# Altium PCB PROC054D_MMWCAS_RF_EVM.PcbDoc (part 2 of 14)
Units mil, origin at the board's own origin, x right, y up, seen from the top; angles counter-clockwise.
Board outline 6299.21 x 5370.07 mil, 8 copper layers (L1 TOP, L2 GND, L3 SIGNAL 1, L4 GND, L5 SIGNAL 2, L6 SIGNAL 3, L7 GND, L8 BOTTOM), stack 53.5 mil thick; 775 components, 552 nets, 2648 pads, 7845 vias.

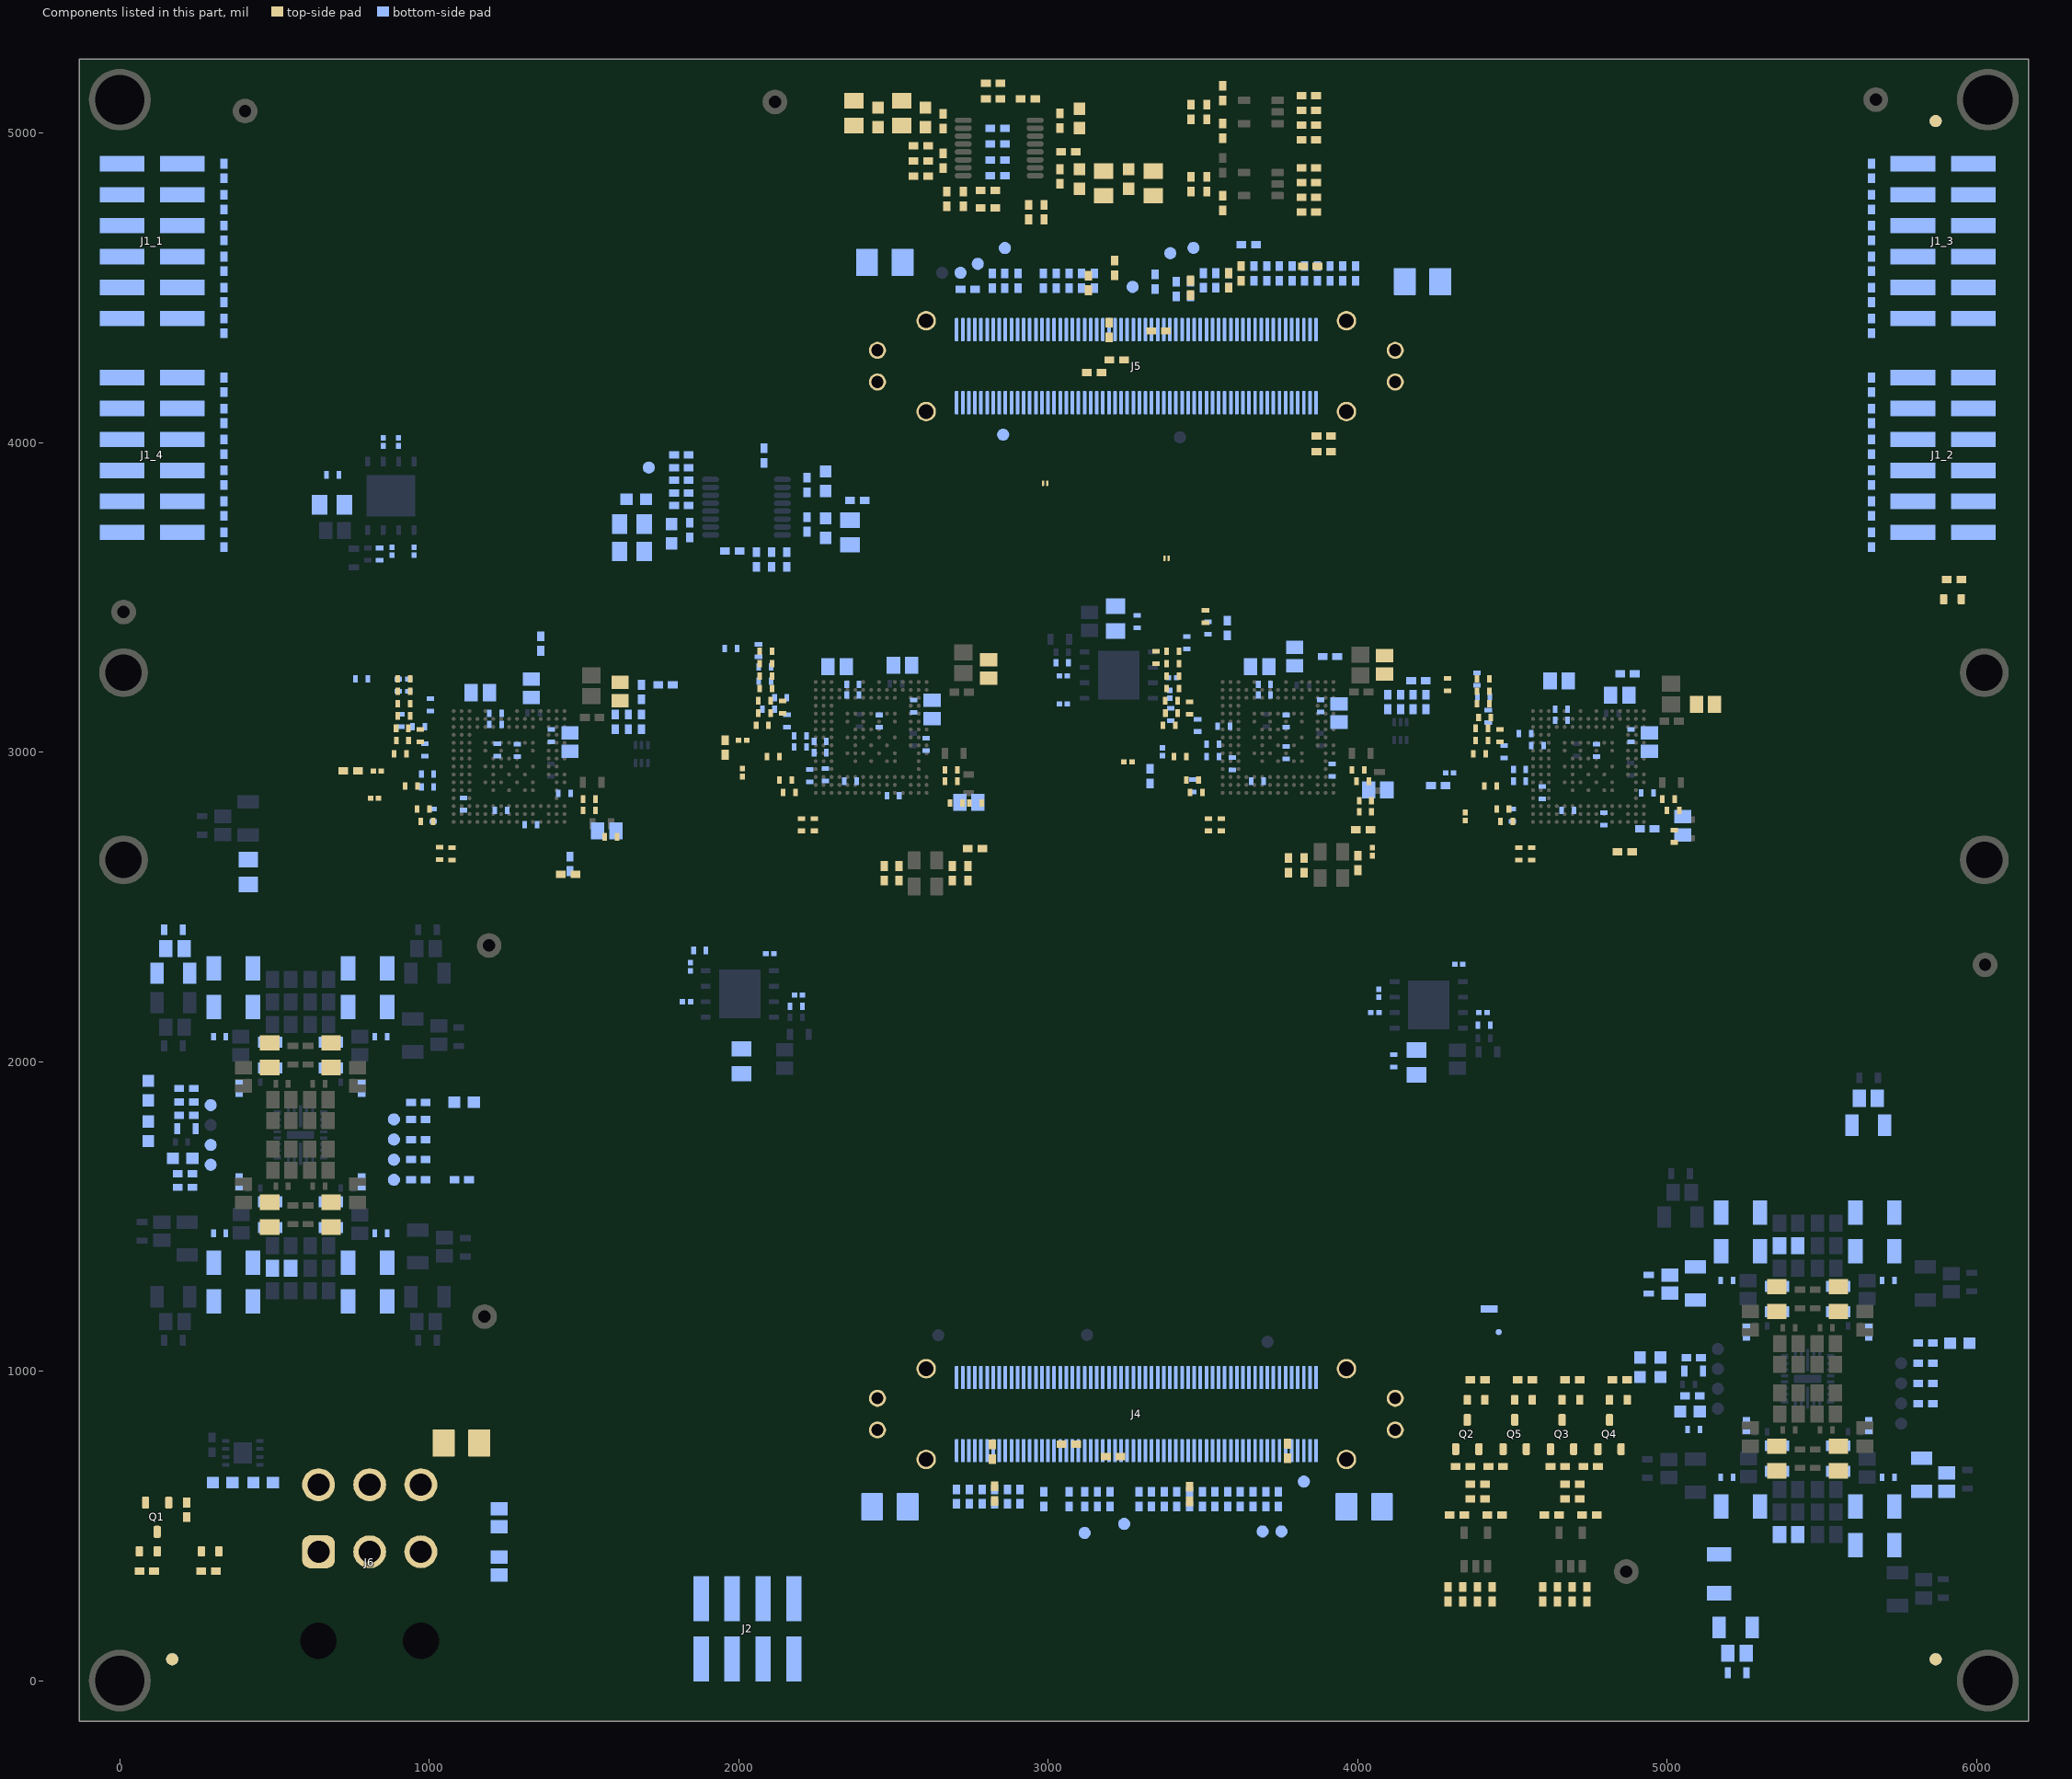
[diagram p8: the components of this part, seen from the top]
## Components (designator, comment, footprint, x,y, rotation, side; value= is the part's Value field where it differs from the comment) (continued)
C129_4 "GCM155R71C224KE02D" 0402S 1219.89,3007.69 r270 bottom locked value=0.22uF (schematic designator C129)
C130_1 "GCM21BR71A106KE22L" 0805L 2529.43,3280.8 r0 bottom locked value=10uF (schematic designator C130)
C130_2 "GCM21BR71A106KE22L" 0805L 4847.43,3183.8 r0 bottom locked value=10uF (schematic designator C130)
C130_3 "GCM21BR71A106KE22L" 0805L 3796.42,3308.91 r90 bottom locked value=10uF (schematic designator C130)
C130_4 "GCM21BR71A106KE22L" 0805L 1329.9,3206.33 r90 bottom locked value=10uF (schematic designator C130)
C131_1 "GCM155R71C224KE02D" 0402S 2686.84,2942.02 r0 top locked value=0.22uF (schematic designator C131)
C131_2 "GCM155R71C224KE02D" 0402S 5004.84,2848.02 r0 top locked value=0.22uF (schematic designator C131)
C131_3 "GCM155R71C224KE02D" 0402S 4016.84,2906.06 r0 top locked value=0.22uF (schematic designator C131)
C131_4 "GCM155R71C224KE02D" 0402S 1516.84,2848.02 r0 top locked value=0.22uF (schematic designator C131)
C132_1 "GCM155R71C224KE02D" 0402S 2686.84,2906.06 r0 top locked value=0.22uF (schematic designator C132)
C132_2 "GCM155R71C224KE02D" 0402S 5019.84,2812.06 r0 top locked value=0.22uF (schematic designator C132)
C132_3 "GCM155R71C224KE02D" 0402S 4001.84,2942.02 r0 top locked value=0.22uF (schematic designator C132)
C132_4 "GCM155R71C224KE02D" 0402S 1516.84,2812.06 r0 top locked value=0.22uF (schematic designator C132)
C133_1 "GCM21BR71A106KE22L" 0805L 2743.75,2837.89 r0 bottom locked value=10uF (schematic designator C133)
C133_2 "GCM21BR71A106KE22L" 0805L 5050.19,2762.16 r270 bottom locked value=10uF (schematic designator C133)
C133_3 "GCM21BR71A106KE22L" 0805L 4065.03,2878.26 r0 bottom locked value=10uF (schematic designator C133)
C133_4 "GCM21BR71A106KE22L" 0805L 1573.1,2745.99 r0 bottom locked value=10uF (schematic designator C133)
C134_1 "GCM155R71C224KE02D" 0402S 2605.98,3025.49 r90 bottom locked value=0.22uF (schematic designator C134)
C134_2 "GCM155R71C224KE02D" 0402S 4936.09,2868 r0 bottom locked value=0.22uF (schematic designator C134)
C134_3 "GCM155R71C224KE02D" 0402S 3918.09,2942 r270 bottom locked value=0.22uF (schematic designator C134)
C134_4 "GCM155R71C224KE02D" 0402S 1437.23,2867 r0 bottom locked value=0.22uF (schematic designator C134)
C135_1 "GCM155R71C224KE02D" 0402S 2361.3,2906 r180 bottom locked value=0.22uF (schematic designator C135)
C135_2 "GCM155R71C224KE02D" 0402S 4679.3,2812 r180 bottom locked value=0.22uF (schematic designator C135)
C135_3 "GCM155R71C224KE02D" 0402S 3676.3,2906 r180 bottom locked value=0.22uF (schematic designator C135)
C135_4 "GCM155R71C224KE02D" 0402S 1231.3,2812 r0 bottom locked value=0.22uF (schematic designator C135)
C136_1 "GCM155R71C224KE02D" 0402S 2454.38,3100.07 r270 bottom locked value=0.22uF (schematic designator C136)
C136_2 "GCM155R71C224KE02D" 0402S 4772.38,3006.07 r270 bottom locked value=0.22uF (schematic designator C136)
C136_3 "GCM155R71C224KE02D" 0402S 3769.38,3100.07 r270 bottom locked value=0.22uF (schematic designator C136)
C136_4 "GCM155R71C224KE02D" 0402S 1284.38,3006.07 r270 bottom locked value=0.22uF (schematic designator C136)
C137_1 "GCM155R71C224KE02D" 0402S 2369.09,3184.18 r180 bottom locked value=0.22uF (schematic designator C137)
C137_2 "GCM155R71C224KE02D" 0402S 4659,3103.53 r180 bottom locked value=0.22uF (schematic designator C137)
C137_3 "GCM155R71C224KE02D" 0402S 3699.09,3218.8 r180 bottom locked value=0.22uF (schematic designator C137)
C137_4 "GCM155R71C224KE02D" 0402S 1214.09,3090.18 r180 bottom locked value=0.22uF (schematic designator C137)
C138_1 "GCM155R71C224KE02D" 0402S 2369.09,3218.8 r180 bottom locked value=0.22uF (schematic designator C138)
C138_2 "GCM155R71C224KE02D" 0402S 4659,3138.15 r180 bottom locked value=0.22uF (schematic designator C138)
C138_3 "GCM155R71C224KE02D" 0402S 3699.09,3184.18 r180 bottom locked value=0.22uF (schematic designator C138)
C138_4 "GCM155R71C224KE02D" 0402S 1214.09,3124.8 r180 bottom locked value=0.22uF (schematic designator C138)
C139_1 "GCM21BR71A106KE22L" 0805L 2318.38,3275.59 r180 bottom locked value=10uF (schematic designator C139)
C139_2 "GCM21BR71A106KE22L" 0805L 4651.52,3229.77 r180 bottom locked value=10uF (schematic designator C139)
C139_3 "GCM21BR71A106KE22L" 0805L 3683.72,3276.04 r180 bottom locked value=10uF (schematic designator C139)
C139_4 "GCM21BR71A106KE22L" 0805L 1164.56,3192.04 r180 bottom locked value=10uF (schematic designator C139)
C140_1 "GCM155R71C224KE02D" 0402S 2564.98,3147.69 r270 bottom locked value=0.22uF (schematic designator C140)
C140_2 "GCM155R71C224KE02D" 0402S 4882.98,3053.69 r270 bottom locked value=0.22uF (schematic designator C140)
C140_3 "GCM155R71C224KE02D" 0402S 3879.98,3149.11 r270 bottom locked value=0.22uF (schematic designator C140)
C140_4 "GCM155R71C224KE02D" 0402S 1394.98,3053.69 r270 bottom locked value=0.22uF (schematic designator C140)
C141_1 "GCM21BR71A106KE22L" 0805L 2624.84,3138.16 r270 bottom locked value=10uF (schematic designator C141)
C141_2 "GCM21BR71A106KE22L" 0805L 4942.98,3032.5 r270 bottom locked value=10uF (schematic designator C141)
C141_3 "GCM21BR71A106KE22L" 0805L 3939.98,3126.5 r270 bottom locked value=10uF (schematic designator C141)
C141_4 "GCM21BR71A106KE22L" 0805L 1454.98,3032.5 r270 bottom locked value=10uF (schematic designator C141)
C142_1 "GCM155R71C224KE02D" 0402S 2141.49,3145.71 r90 top locked value=0.22uF (schematic designator C142)
C142_2 "GCM155R71C224KE02D" 0402S 4562,2671.58 r270 top locked value=0.22uF (schematic designator C142)
C142_3 "GCM155R71C224KE02D" 0402S 3457.49,3142.71 r90 top locked value=0.22uF (schematic designator C142)
C142_4 "GCM155R71C224KE02D" 0402S 971.49,3053.71 r90 top locked value=0.22uF (schematic designator C142)
C143_1 "GCM155R71C224KE02D" 0402S 2244,2765.58 r270 top locked value=0.22uF (schematic designator C143)
C143_2 "GCM155R71C224KE02D" 0402S 4459.99,3053.71 r90 top locked value=0.22uF (schematic designator C143)
C143_3 "GCM155R71C224KE02D" 0402S 3559,2765.58 r270 top locked value=0.22uF (schematic designator C143)
C143_4 "GCM155R71C224KE02D" 0402S 1074,2671.58 r270 top locked value=0.22uF (schematic designator C143)
C144_1 "GCM155R71C224KE02D" 0402S 2498.51,2859.53 r0 bottom locked value=0.22uF (schematic designator C144)
C144_2 "GCM155R71C224KE02D" 0402S 4596.3,2868.9 r270 bottom locked value=0.22uF (schematic designator C144)
C144_3 "GCM155R71C224KE02D" 0402S 3769.06,2998.27 r90 bottom locked value=0.22uF (schematic designator C144)
C144_4 "GCM155R71C224KE02D" 0402S 1110.64,2832.35 r270 bottom locked value=0.22uF (schematic designator C144)
C145_1 "GCM155R71C224KE02D" 0402S 2280.64,2926.35 r270 bottom locked value=0.22uF (schematic designator C145)
C145_2 "GCM155R71C224KE02D" 0402S 4796.51,2783.84 r270 bottom locked value=0.22uF (schematic designator C145)
C145_3 "GCM155R71C224KE02D" 0402S 3595.75,2962.9 r270 bottom locked value=0.22uF (schematic designator C145)
C145_4 "GCM155R71C224KE02D" 0402S 1328.51,2765.53 r0 bottom locked value=0.22uF (schematic designator C145)
C146_1 "GCM155R71C104KA55D" 0402S 2163.58,2870 r180 top locked value=0.1uF (schematic designator C146)
C146_2 "GCM155R71C104KA55D" 0402S 4481.58,2776 r180 top locked value=0.1uF (schematic designator C146)
C146_3 "GCM155R71C104KA55D" 0402S 3478.58,2870 r180 top locked value=0.1uF (schematic designator C146)
C146_4 "GCM155R71C104KA55D" 0402S 992.8,2776 r180 top locked value=0.1uF (schematic designator C146)
C147_1 "GCM155R71C104KA55D" 0402S 2203,2765.58 r270 top locked value=0.1uF (schematic designator C147)
C147_2 "GCM155R71C104KA55D" 0402S 4521,2671.58 r270 top locked value=0.1uF (schematic designator C147)
C147_3 "GCM155R71C104KA55D" 0402S 3518,2765.58 r270 top locked value=0.1uF (schematic designator C147)
C147_4 "GCM155R71C104KA55D" 0402S 1033,2673 r270 top locked value=0.1uF (schematic designator C147)
C148_1 "GCM155R71C224KE02D" 0402S 2229,2924.28 r270 bottom locked value=0.22uF (schematic designator C148)
C148_2 "GCM155R71C224KE02D" 0402S 4500,2795.58 r270 bottom locked value=0.22uF (schematic designator C148)
C148_3 "GCM155R71C224KE02D" 0402S 3466.95,2891 r270 bottom locked value=0.22uF (schematic designator C148)
C148_4 "GCM155R71C224KE02D" 0402S 1012,2795.58 r270 bottom locked value=0.22uF (schematic designator C148)
C149 "CGA2B3X7R1H104K050BB" 0402 3564.27,5129.3 r90 top locked value=0.1uF
C150 "GCM31CR71A226KE02" 1206_180L 173.03,2285.84 r180 bottom locked value=22uF
C151 "GCM21BR71A106KE22L" 0805L 178.04,2365.78 r180 bottom locked value=10uF
C152 "GCM188R71C105KA64J" 0603S 173.04,2425.94 r180 bottom locked value=1uF
C153 "GCM21BR71A106KE22L" 0805L 5393.06,471.95 r0 bottom locked value=10uF
C154 "GCM31CR71A226KE02" 1206_180L 5221.38,171.94 r0 bottom locked value=22uF
C155 "GCM21BR71A106KE22L" 0805L 5226.35,89.14 r0 bottom locked value=10uF
C156 "GCM188R71C105KA64J" 0603S 5226.35,25.17 r0 bottom locked value=1uF
C157 "GCM21BR71A106KE22L" 0805L 5393.06,1405.27 r0 bottom locked value=10uF
C158 "GCM31CR71A226KE02" 1206_180L 5091.39,1283.32 r270 bottom locked value=22uF
C159 "GCM21BR71A106KE22L" 0805L 5009.39,1281.05 r270 bottom locked value=10uF
C160 "GCM188R71C105KA64J" 0603S 4940.6,1280.76 r270 bottom locked value=1uF
C161 "GCM21BR71A106KE22L" 0805L 522.33,1332.8 r0 bottom locked value=10uF
C162 "GCM155R71C104KA55D" 0402 4320.97,535.63 r180 top locked value=0.1uF
C163 "GCM155R71C104KA55D" 0402 4627.42,535.63 r180 top locked value=0.1uF
C164 "GCM155R71C104KA55D" 0402 3564.27,4774.2 r270 top locked value=0.1uF
C165 "GCM155R71C104KA55D" 0402 3564.27,5007.25 r270 top locked value=0.1uF
C166 "GCM31CR71A226KE02" 1206_180L 5822.48,664.93 r90 bottom locked value=22uF
C167 "GJM1555C1H4R7BB01D" 0402 2690.4,2608.27 r90 top locked value=4.7pF
C168 "GJM1555C1H4R7BB01D" 0402 2518.3,2608.27 r90 top locked value=4.7pF
C169 "GCM21BR71A106KE22L" 0805_HV 2372.39,5064.49 r270 top locked value=10uF
C170 "GCM155R71C224KE02D" 0402 2660.57,5038.49 r90 top locked value=0.22uF
C171 "GCM188R70J225KE22D" 0603 2603.2,5050.47 r270 top locked value=2.2uF
C172 "GCM21BR71A106KE22L" 0805_HV 2526.41,5064.49 r90 top locked value=10uF
C173 "GJM1555C1H4R7BB01D" 0402 4001.11,2642 r90 top locked value=4.7pF
C174 "GJM1555C1H4R7BB01D" 0402 3826.93,2634.28 r270 top locked value=4.7pF
C175 "GCM21BR71A106KE22L" 0805_HV 3339.25,4837.72 r90 top locked value=10uF
C176 "GCM21BR71A106KE22L" 0805_HV 3178.88,4837.72 r270 top locked value=10uF
C177 "GCM155R71C224KE02D" 0402 3038.3,4859.61 r270 top locked value=0.22uF
C178 "GCM188R70J225KE22D" 0603 3100.57,5047.4 r270 top locked value=2.2uF
C179 "GCM155R71C224KE02D" 0402 3038.3,5039.53 r90 top locked value=0.22uF
C180 "GCM188R70J225KE22D" 0603 3100.57,4851.73 r90 top locked value=2.2uF
C181 "GCM21BR71A106KE22L" 0805_HV 1655.02,3648.2 r180 bottom locked value=10uF
C182 "GCM155R71C224KE02D" 0402 1841.77,3717.5 r270 bottom locked value=0.22uF
C183 "GCM188R70J225KE22D" 0603 1783.09,3705.52 r90 bottom locked value=2.2uF
C184 "GCM21BR71A106KE22L" 0805_HV 1655.02,3737.01 r180 bottom locked value=10uF
C185 "GCM21BR71A106KE22L" 0805_HV 2359.46,3709.7 r90 bottom locked value=10uF
C186 "GCM155R71C224KE02D" 0402 2220.98,3735.85 r90 bottom locked value=0.22uF
C187 "GCM188R70J225KE22D" 0603 2280.22,3723.87 r270 bottom locked value=2.2uF
C188 "GCM155R71C224KE02D" 0402 2220.98,3863.05 r90 bottom locked value=0.22uF
C189 "GCM188R70J225KE22D" 0603 2280.22,3875.03 r270 bottom locked value=2.2uF
C190 "T491B476K010AT" 3528-21 4021.54,561.82 r0 bottom locked value=47uF
C191 "T491B476K010AT" 3528-21 2488.3,561.82 r180 bottom locked value=47uF
C192 "T491B476K010AT" 3528-21 2472.09,4582.18 r180 bottom value=47uF
C193 "T491B476K010AT" 3528-21 4209.7,4520.2 r0 bottom value=47uF
C194 "T491B476K010AT" 3528-21 1103.88,767.73 r0 top locked value=47uF
C195 "C0402C103K4RACTU" 0402 1686.31,3097.83 r90 bottom locked value=0.01uF
C196 "CGA2B3X7R1H104K050BB" 0402 1643.31,3097.84 r90 bottom locked value=0.1uF
C197 "CGA2B3X7R1H104K050BB" 0402 1762.95,3217.44 r0 bottom locked value=0.1uF
C198 "CGA2B3X7R1H104K050BB" 0402 4196.84,3230.71 r180 bottom locked value=0.1uF
C199 "C0402C103K4RACTU" 0402 4138.47,3162.21 r90 bottom locked value=0.01uF
C200 "CGA2B3X7R1H104K050BB" 0402 4179.47,3162.21 r90 bottom locked value=0.1uF
C201 "GCM21BR71A106KE22L" 0805L 5904.25,641.77 r90 bottom locked value=10uF
C202 "GCM188R71C105KA64J" 0603 463.3,640.08 r180 bottom locked value=1uF
C203 "GCM188R71C105KA64J" 0603 332.14,640.15 r0 bottom locked value=1uF
C204 "GCM31CR71A226KE02" 1206_180L 5650.52,1794.57 r180 bottom locked value=22uF
C205 "CGA2B3X7R1H104K050BB" 0402 4443.02,535.63 r0 top locked value=0.1uF
C206 "CGA2B3X7R1H104K050BB" 0402 4749.46,535.63 r0 top locked value=0.1uF
C207 "GCM21BR71A106KE22L" 0805L 5650.43,1881.43 r180 bottom locked value=10uF
DS1 "TLMS1000-GS08" TLMx1000_Red 291.9,417.61 r0 top locked value=Red
DS2 "TLMS1000-GS08" TLMx1000_Red 5922.6,3493.76 r180 top locked value=Red
DS3 "TLMY1000-GS08" TLMx1000_Yellow 91.9,417.61 r0 top locked value=Yellow
DS4 "TLMY1000-GS08" TLMx1000_Yellow 4382.93,906.78 r180 top locked value=Yellow
DS5 "TLMY1000-GS08" TLMx1000_Yellow 4689.38,906.78 r180 top locked value=Yellow
DS6 "TLMY1000-GS08" TLMx1000_Yellow 4842.6,906.78 r180 top locked value=Yellow
DS7 "TLMY1000-GS08" TLMx1000_Yellow 4536.15,906.78 r180 top locked value=Yellow
FID1 "Fiducial" Fiducial10-20 5868,5039 r90 top locked
FID2 "Fiducial" Fiducial10-20 169,69 r90 top locked
FID3 "Fiducial" Fiducial10-20 5868,69 r90 top locked
FID4 "Fiducial" Fiducial10-20 169,69 r90 bottom locked
FID5 "Fiducial" Fiducial10-20 5868,69 r90 bottom locked
FID6 "Fiducial" Fiducial10-20 5868,5039 r90 bottom locked
J1_1 "TSM-106-01-L-DV" Samtec_TSM-106-01-x-DV 104.76,4650.95 r180 bottom locked (schematic designator J1)
J1_2 "TSM-106-01-L-DV" Samtec_TSM-106-01-x-DV 5892.24,3960.13 r0 bottom locked (schematic designator J1)
J1_3 "TSM-106-01-L-DV" Samtec_TSM-106-01-x-DV 5892.24,4650.95 r0 bottom locked (schematic designator J1)
J1_4 "TSM-106-01-L-DV" Samtec_TSM-106-01-x-DV 104.76,3960.13 r180 bottom locked (schematic designator J1)
J2 "TSM-104-01-L-DV" Samtec_TSM-104-01-x-DV 2028.45,167.06 r270 bottom locked
J3 "19S101-40ML5" 19S101_40ML5 4534.87,1201.17 r90 bottom locked
J4 "FX23-120P-0.5SV15" Hirose_FX23-120P-0_5SV15 3284.92,861.13 r270 bottom locked
J5 "FX23-120P-0.5SV15" Hirose_FX23-120P-0_5SV15 3284.92,4246.95 r270 bottom locked
J6 "0039300060" Molex_0039300060 807.36,128.84 r270 bottom locked
L1 "NLCV32T-R10M-EFRD" NLCV32 366.61,1225.32 r180 bottom locked value=100nH
L2 "NLCV32T-R10M-EFRD" NLCV32 366.61,2175.82 r180 bottom locked value=100nH
L3 "NLCV32T-R10M-EFRD" NLCV32 366.61,1350.1 r180 bottom locked value=100nH
L4 "NLCV32T-R10M-EFRD" NLCV32 800.47,1350.1 r0 bottom locked value=100nH
L5 "NLCV32T-R10M-EFRD" NLCV32 800.47,1225.32 r0 bottom locked value=100nH
L6 "NLCV32T-R10M-EFRD" NLCV32 366.61,2300.61 r180 bottom locked value=100nH
L7 "NLCV32T-R10M-EFRD" NLCV32 800.47,2300.61 r0 bottom locked value=100nH
L8 "NLCV32T-R10M-EFRD" NLCV32 800.47,2175.82 r0 bottom locked value=100nH
L9 "BLM21PG300SH1D" 0805_HV 682.81,1505.28 r90 top locked value="30 ohm"
L10 "BLM21PG300SH1D" 0805_HV 484.26,1505.28 r90 top locked value="30 ohm"
L11 "BLM21PG300SH1D" 0805_HV 682.81,2020.65 r270 top locked value="30 ohm"
L12 "BLM21PG300SH1D" 0805_HV 484.26,2020.65 r270 top locked value="30 ohm"
L13 "DFE252012PD-R47M" DFE252012P 681.93,1505.16 r270 bottom locked value=470nH
L14 "DFE252012PD-R47M" DFE252012P 485.15,1505.16 r270 bottom locked value=470nH
L15 "DFE252012PD-R47M" DFE252012P 681.93,2020.76 r90 bottom locked value=470nH
L16 "DFE252012PD-R47M" DFE252012P 485.15,2020.76 r90 bottom locked value=470nH
L17 "NLCV32T-R10M-EFRD" NLCV32 5237.33,562.25 r180 bottom locked value=100nH
L18 "NLCV32T-R10M-EFRD" NLCV32 5237.33,1512.75 r180 bottom locked value=100nH
L19 "NLCV32T-R10M-EFRD" NLCV32 5168.15,344.97 r270 bottom locked value=100nH
L20 "NLCV32T-R10M-EFRD" NLCV32 5671.19,437.46 r0 bottom locked value=100nH
L21 "NLCV32T-R10M-EFRD" NLCV32 5671.19,562.25 r0 bottom locked value=100nH
L22 "NLCV32T-R10M-EFRD" NLCV32 5237.33,1387.96 r180 bottom locked value=100nH
L23 "NLCV32T-R10M-EFRD" NLCV32 5671.19,1387.96 r0 bottom locked value=100nH
L24 "NLCV32T-R10M-EFRD" NLCV32 5671.19,1512.75 r0 bottom locked value=100nH
L25 "BLM21PG300SH1D" 0805_HV 5553.54,717.42 r90 top locked value="30 ohm"
L26 "BLM21PG300SH1D" 0805_HV 5354.99,717.42 r90 top locked value="30 ohm"
L27 "BLM21PG300SH1D" 0805_HV 5553.54,1232.79 r270 top locked value="30 ohm"
L28 "BLM21PG300SH1D" 0805_HV 5354.99,1232.79 r270 top locked value="30 ohm"
L29 "DFE252012PD-R47M" DFE252012P 5552.65,717.3 r270 bottom locked value=470nH
L30 "DFE252012PD-R47M" DFE252012P 5355.87,717.3 r270 bottom locked value=470nH
L31 "DFE252012PD-R47M" DFE252012P 5552.65,1232.91 r90 bottom locked value=470nH
L32 "DFE252012PD-R47M" DFE252012P 5355.87,1232.91 r90 bottom locked value=470nH
L33 "BLM18SG121TN1D" 0603 2450.31,5050.47 r270 top locked value="120 ohm"
L34 "BLM18SG121TN1D" 0603 3260.01,4851.73 r90 top locked value="120 ohm"
L35 "BLM18SG121TN1D" 0603 1669.04,3816.87 r0 bottom locked value="120 ohm"
Logo1 "CE MAWRk" CE_Mark_5mm 5859.14,4655.58 r0 top locked
Logo2 "Texas Instruments" TI_Stacked_Overlay_Small 3704.87,99.62 r0 top locked
Logo3 "FCC disclaimer" FCC_disclaimer 4988.06,6271.78 r0 top locked
Logo4 "WEEE logo" WEEE_Minimum 5859.14,4323.69 r0 top locked
Logo5 "ESD Susceptible" ESD_Overlay_Large 1902.61,792.81 r0 top locked
LOGO6 "CAUTION HOT SURFACE" IEC_HotSurface_Large 5623.06,1848.13 r0 top locked
Q1 "BSS123" SOT-23 120.44,527.89 r270 top locked value=100V
Q2 "BSS123" SOT-23 4354.39,795.2 r90 top locked value=100V
Q3 "BSS123" SOT-23 4660.83,795.2 r90 top locked value=100V
Q4 "BSS123" SOT-23 4814.06,795.2 r90 top locked value=100V
Q5 "BSS123" SOT-23 4507.61,795.2 r90 top locked value=100V
R1_1 "CRCW040233R2FKED" 0402S 2111.9,2985 r0 top locked value=33.2 (schematic designator R1)
R1_2 "CRCW040233R2FKED" 0402S 4429.9,2891 r0 top locked value=33.2 (schematic designator R1)
R1_3 "CRCW040233R2FKED" 0402S 3426.9,2985 r0 top locked value=33.2 (schematic designator R1)
R1_4 "CRCW040233R2FKED" 0402S 941.9,2891 r0 top locked value=33.2 (schematic designator R1)
R2_1 "CRCW040233R2FKED" 0402S 2702.88,2834.89 r180 top locked value=33.2 (schematic designator R2)
R2_2 "CRCW040233R2FKED" 0402S 5022.77,2728.4 r90 top locked value=33.2 (schematic designator R2)
R2_3 "CRCW040233R2FKED" 0402S 4024.71,2842.4 r180 top locked value=33.2 (schematic designator R2)
R2_4 "CRCW040233R2FKED" 0402S 1587.14,2726.23 r180 top locked value=33.2 (schematic designator R2)
R3_1 "CRCW040247K5FKED" 0402 1955.47,3015.03 r270 top locked value=47.5k (schematic designator R3)
R3_2 "CRCW040247K5FKED" 0402 4260.87,2891.34 r180 bottom locked value=47.5k (schematic designator R3)
R3_3 "CRCW040247K5FKED" 0402 3328.84,2922.71 r270 bottom locked value=47.5k (schematic designator R3)
R3_4 "CRCW040247K5FKED" 0402 745.96,2938.96 r180 top locked value=47.5k (schematic designator R3)
R4_1 "CRCW040233R2FKED" 0402S 2151,2910 r0 top locked value=33.2 (schematic designator R4)
R4_2 "CRCW040233R2FKED" 0402S 4469,2816 r0 top locked value=33.2 (schematic designator R4)
R4_3 "CRCW040233R2FKED" 0402S 3466,2910 r0 top locked value=33.2 (schematic designator R4)
R4_4 "CRCW040233R2FKED" 0402S 981,2816 r0 top locked value=33.2 (schematic designator R4)
R5_1 "CRCW040233R2FKED" 0402S 2263.7,3034.15 r0 bottom locked value=33.2 (schematic designator R5)
R5_2 "CRCW040233R2FKED" 0402S 4523.9,2943.53 r0 bottom locked value=33.2 (schematic designator R5)
R5_3 "CRCW040233R2FKED" 0402S 3531.46,3026.2 r0 bottom locked value=33.2 (schematic designator R5)
R5_4 "CRCW040233R2FKED" 0402S 994.55,2928.78 r0 bottom locked value=33.2 (schematic designator R5)
R6_1 "CRCW02010000Z0ED" 0201 2012.51,3038.66 r180 top locked value=0 (schematic designator R6)
R6_2 "CRCW02010000Z0ED" 0201 4297.49,2932.79 r180 bottom locked value=0 (schematic designator R6)
R6_3 "CRCW02010000Z0ED" 0201 3369.29,3001.01 r270 bottom locked value=0 (schematic designator R6)
R6_4 "CRCW02010000Z0ED" 0201 831.79,2938.96 r180 top locked value=0 (schematic designator R6)
R7_1 "CRCW02010000Z0ED" 0201 2012.41,2934.01 r270 top locked value=0 (schematic designator R7)
R7_2 "CRCW02010000Z0ED" 0201 4347.63,2791.93 r270 top locked value=0 (schematic designator R7)
R7_3 "CRCW02010000Z0ED" 0201 3258.01,2969 r180 top locked value=0 (schematic designator R7)
R7_4 "CRCW02010000Z0ED" 0201 823.23,2851.34 r180 top locked value=0 (schematic designator R7)
R8_1 "CRCW040233R2FKED" 0402S 2263.7,2998.15 r180 bottom locked value=33.2 (schematic designator R8)
R8_2 "CRCW040233R2FKED" 0402S 4523.9,2906 r180 bottom locked value=33.2 (schematic designator R8)
R8_3 "CRCW040233R2FKED" 0402S 3531.46,2985.2 r180 bottom locked value=33.2 (schematic designator R8)
R8_4 "CRCW040233R2FKED" 0402S 994.55,2887.78 r180 bottom locked value=33.2 (schematic designator R8)
R9_1 "ERJ-2GE0R00X" 0402S 2135.9,3176 r0 bottom locked value=0 (schematic designator R9)
R9_2 "ERJ-2GE0R00X" 0402S 4580.6,3020.95 r0 bottom locked value=0 (schematic designator R9)
R9_3 "ERJ-2GE0R00X" 0402S 3567.22,3084.16 r0 bottom locked value=0 (schematic designator R9)
R9_4 "ERJ-2GE0R00X" 0402S 965.9,3082 r0 bottom locked value=0 (schematic designator R9)
R10_1 "CRCW040233R2FKED" 0402S 2083,3126 r180 top locked value=33.2 (schematic designator R10)
R10_2 "CRCW040233R2FKED" 0402S 4400.91,3037 r180 top locked value=33.2 (schematic designator R10)
R10_3 "CRCW040233R2FKED" 0402S 3398.91,3126 r180 top locked value=33.2 (schematic designator R10)
R10_4 "CRCW040233R2FKED" 0402S 913,3037 r180 top locked value=33.2 (schematic designator R10)
R11_1 "CRCW040233R2FKED" 0402S 2084.31,3229 r0 bottom locked value=33.2 (schematic designator R11)
R11_2 "CRCW040233R2FKED" 0402S 4422.06,3115 r90 bottom locked value=33.2 (schematic designator R11)
R11_3 "CRCW040233R2FKED" 0402S 3516,3400.34 r270 bottom locked value=33.2 (schematic designator R11)
R11_4 "CRCW040233R2FKED" 0402S 1003.91,3152.94 r270 bottom value=33.2 (schematic designator R11)
R12_1 "CRCW040233R2FKED" 0402S 2083,3166 r180 top locked value=33.2 (schematic designator R12)
R12_2 "CRCW040233R2FKED" 0402S 4400.89,3077 r180 top locked value=33.2 (schematic designator R12)
R12_3 "CRCW040233R2FKED" 0402S 3398.89,3166 r180 top locked value=33.2 (schematic designator R12)
R12_4 "CRCW040233R2FKED" 0402S 912.89,3077 r180 top locked value=33.2 (schematic designator R12)
R13_1 "CRCW040233R2FKED" 0402S 2088,3326 r0 top locked value=33.2 (schematic designator R13)
R13_2 "CRCW040233R2FKED" 0402S 4405.9,3237 r0 top locked value=33.2 (schematic designator R13)
R13_3 "CRCW040233R2FKED" 0402S 3402.9,3326 r0 top locked value=33.2 (schematic designator R13)
R13_4 "CRCW040233R2FKED" 0402S 917.9,3237 r0 top locked value=33.2 (schematic designator R13)
R14_1 "CRCW040233R2FKED" 0402S 2088,3246 r0 top locked value=33.2 (schematic designator R14)
R14_2 "CRCW040233R2FKED" 0402S 4405.89,3157 r0 top locked value=33.2 (schematic designator R14)
R14_3 "CRCW040233R2FKED" 0402S 3402.89,3246 r0 top locked value=33.2 (schematic designator R14)
R14_4 "CRCW040233R2FKED" 0402S 917.89,3157 r0 top locked value=33.2 (schematic designator R14)
R15_1 "CRCW040233R2FKED" 0402S 2088,3206 r0 top locked value=33.2 (schematic designator R15)
R15_2 "CRCW040233R2FKED" 0402S 4410.9,3112 r0 top locked value=33.2 (schematic designator R15)
R15_3 "CRCW040233R2FKED" 0402S 3402.9,3206 r0 top locked value=33.2 (schematic designator R15)
R15_4 "CRCW040233R2FKED" 0402S 917.9,3117 r0 top locked value=33.2 (schematic designator R15)
R16_1 "CRCW040210K0FKED" 0402 2704.21,594.52 r90 bottom locked value=10.0k (schematic designator R16)
R16_2 "CRCW040210K0FKED" 0402 3539,586.8 r90 bottom locked value=10.0k (schematic designator R16)
R16_3 "CRCW040210K0FKED" 0402 3993,4546.63 r270 bottom locked value=10.0k (schematic designator R16)
R16_4 "CRCW040210K0FKED" 0402 3067,4522.59 r270 bottom locked value=10.0k (schematic designator R16)
R17_1 "CRCW040210K0FKED" 0402 2745.21,594.52 r90 bottom locked value=10.0k (schematic designator R17)
R17_2 "CRCW040210K0FKED" 0402 3580,586.8 r90 bottom locked value=10.0k (schematic designator R17)
R17_3 "CRCW040210K0FKED" 0402 3952,4546.63 r270 bottom locked value=10.0k (schematic designator R17)
R17_4 "CRCW040210K0FKED" 0402 3026,4522.59 r270 bottom locked value=10.0k (schematic designator R17)
R18_1 "CRCW040210K0FKED" 0402 2786.21,594.52 r90 bottom locked value=10.0k (schematic designator R18)
R18_2 "CRCW040210K0FKED" 0402 3621,586.8 r90 bottom locked value=10.0k (schematic designator R18)
R18_3 "CRCW040210K0FKED" 0402 3911,4546.63 r270 bottom locked value=10.0k (schematic designator R18)
R18_4 "CRCW040210K0FKED" 0402 2985,4522.59 r270 bottom locked value=10.0k (schematic designator R18)
R19 "PMR10EZPJ000" 0805L 1226.16,526.12 r270 bottom locked value=0
R20 "PMR10EZPJ000" 0805L 1226.16,370.14 r270 bottom locked value=0
R21_1 "CRCW04020000Z0ED" 0402 335.85,4877.33 r90 bottom locked value=0 (schematic designator R21)
R21_2 "CRCW04020000Z0ED" 0402 5661.15,3686.51 r90 bottom locked value=0 (schematic designator R21)
R21_3 "CRCW04020000Z0ED" 0402 5661.15,4377.33 r90 bottom locked value=0 (schematic designator R21)
R21_4 "CRCW04020000Z0ED" 0402 335.85,4186.51 r90 bottom locked value=0 (schematic designator R21)
R22_1 "CRCW04020000Z0ED" 0402 335.85,4777.33 r90 bottom locked value=0 (schematic designator R22)
R22_2 "CRCW04020000Z0ED" 0402 5661.15,3786.51 r90 bottom locked value=0 (schematic designator R22)
R22_3 "CRCW04020000Z0ED" 0402 5661.15,4477.33 r90 bottom locked value=0 (schematic designator R22)
R22_4 "CRCW04020000Z0ED" 0402 335.85,4086.51 r90 bottom locked value=0 (schematic designator R22)
R23_1 "CRCW04020000Z0ED" 0402 335.85,4677.33 r90 bottom locked value=0 (schematic designator R23)
R23_2 "CRCW04020000Z0ED" 0402 5661.15,3886.51 r90 bottom locked value=0 (schematic designator R23)
R23_3 "CRCW04020000Z0ED" 0402 5661.15,4577.33 r90 bottom locked value=0 (schematic designator R23)
R23_4 "CRCW04020000Z0ED" 0402 335.85,3986.51 r90 bottom locked value=0 (schematic designator R23)
R24_1 "CRCW04020000Z0ED" 0402 335.85,4577.33 r90 bottom locked value=0 (schematic designator R24)
R24_2 "CRCW04020000Z0ED" 0402 5661.15,3986.51 r90 bottom locked value=0 (schematic designator R24)
R24_3 "CRCW04020000Z0ED" 0402 5661.15,4677.33 r90 bottom locked value=0 (schematic designator R24)
R24_4 "CRCW04020000Z0ED" 0402 335.85,3886.51 r90 bottom locked value=0 (schematic designator R24)
R25_1 "CRCW04020000Z0ED" 0402 335.85,4477.33 r90 bottom locked value=0 (schematic designator R25)
R25_2 "CRCW04020000Z0ED" 0402 5661.15,4086.51 r90 bottom locked value=0 (schematic designator R25)
R25_3 "CRCW04020000Z0ED" 0402 5661.15,4777.33 r90 bottom locked value=0 (schematic designator R25)
R25_4 "CRCW04020000Z0ED" 0402 335.85,3786.51 r90 bottom locked value=0 (schematic designator R25)
R26_1 "CRCW04020000Z0ED" 0402 335.85,4377.33 r90 bottom locked value=0 (schematic designator R26)
R26_2 "CRCW04020000Z0ED" 0402 5661.15,4186.51 r90 bottom locked value=0 (schematic designator R26)
R26_3 "CRCW04020000Z0ED" 0402 5661.15,4877.33 r90 bottom locked value=0 (schematic designator R26)
R26_4 "CRCW04020000Z0ED" 0402 335.85,3686.51 r90 bottom locked value=0 (schematic designator R26)
R27_1 "CRCW040210K0FKED" 0402S 1874.26,2359.18 r180 bottom locked value=10.0k (schematic designator R27)
R27_2 "CRCW040210K0FKED" 0402S 4116.64,2002.51 r270 bottom locked value=10.0k (schematic designator R27)
R27_3 "CRCW040210K0FKED" 0402S 3287.73,3421.24 r90 bottom locked value=10.0k (schematic designator R27)
R27_4 "CRCW040210K0FKED" 0402S 688.22,3895.75 r180 bottom locked value=10.0k (schematic designator R27)
R28_1 "CRCW040210K0FKED" 0402S 2185.91,2178.18 r0 bottom locked value=10.0k (schematic designator R28)
R28_2 "CRCW040210K0FKED" 0402S 4408.64,2117.67 r0 bottom locked value=10.0k (schematic designator R28)
R28_3 "CRCW040210K0FKED" 0402S 3045.36,3289.27 r180 bottom locked value=10.0k (schematic designator R28)
R28_4 "CRCW040210K0FKED" 0402S 839.38,3639.4 r270 bottom locked value=10.0k (schematic designator R28)
R29_1 "CRCW08050000Z0EAHP" 0805_HV 2009.01,2000.95 r270 bottom locked value=0 (schematic designator R29)
R29_2 "CRCW08050000Z0EAHP" 0805_HV 4190.26,1997.32 r270 bottom locked value=0 (schematic designator R29)
R29_3 "CRCW08050000Z0EAHP" 0805_HV 3218.01,3431.29 r90 bottom locked value=0 (schematic designator R29)
R29_4 "CRCW08050000Z0EAHP" 0805_HV 685.87,3799.23 r180 bottom locked value=0 (schematic designator R29)
R30_1 "CRCW02010000Z0ED" 0201 2100.55,2349.27 r0 bottom locked value=0 (schematic designator R30)
R30_2 "CRCW02010000Z0ED" 0201 4327.2,2313.99 r0 bottom locked value=0 (schematic designator R30)
R30_3 "CRCW02010000Z0ED" 0201 3048.83,3156 r0 bottom locked value=0 (schematic designator R30)
R30_4 "CRCW02010000Z0ED" 0201 950.89,3648.97 r90 bottom locked value=0 (schematic designator R30)
R31_1 "CRCW02010000Z0ED" 0201 1831.26,2193.45 r0 bottom locked value=0 (schematic designator R31)
R31_2 "CRCW02010000Z0ED" 0201 4055.83,2158.17 r0 bottom locked value=0 (schematic designator R31)
R31_3 "CRCW02010000Z0ED" 0201 3402.09,3239.82 r180 bottom locked value=0 (schematic designator R31)
R31_4 "CRCW02010000Z0ED" 0201 850.89,4002.22 r270 bottom locked value=0 (schematic designator R31)
R32_1 "CRCW02010000Z0ED" 0201 1844.26,2306.44 r270 bottom locked value=0 (schematic designator R32)
R32_2 "CRCW02010000Z0ED" 0201 4068.82,2221.16 r270 bottom locked value=0 (schematic designator R32)
R32_3 "CRCW02010000Z0ED" 0201 3393.01,3186.88 r90 bottom locked value=0 (schematic designator R32)
R32_4 "CRCW02010000Z0ED" 0201 900.89,4002.22 r270 bottom locked value=0 (schematic designator R32)
R33_1 "CRCW02010000Z0ED" 0201 2192.91,2215.45 r180 bottom locked value=0 (schematic designator R33)
R33_2 "CRCW02010000Z0ED" 0201 4405.09,2158.17 r180 bottom locked value=0 (schematic designator R33)
R33_3 "CRCW02010000Z0ED" 0201 3048.83,3246 r0 bottom locked value=0 (schematic designator R33)
R33_4 "CRCW02010000Z0ED" 0201 878.89,3648.97 r90 bottom locked value=0 (schematic designator R33)
R34 "CRCW06031R00FKEA" 0603 92.28,1906.59 r90 bottom locked value=1.00
R35 "PMR10EZPJ000" 0805_HV 414.97,2612.47 r90 bottom locked value=0
R36 "CRCW06031K96FKEA" 0603 92.28,1774.54 r90 bottom locked value=1.96k
R37 "CRCW040210K0FKED" 0402 3512.69,4835.24 r270 top locked value=10.0k
R38 "MCS0402MD1000BE100" 0402 3841.88,4792.82 r180 top locked value=100
R39 "CRCW04023R90JNED" 0402S 781.41,1611.98 r270 bottom locked value=3.9
R40 "CRCW04023R90JNED" 0402S 385.66,1611.98 r270 bottom locked value=3.9
R41 "CRCW04023R90JNED" 0402S 781.41,1913.94 r90 bottom locked value=3.9
R42 "CRCW04023R90JNED" 0402S 385.66,1913.94 r90 bottom locked value=3.9
R43 "CRCW04020000Z0ED" 0402S 844.21,1445.28 r0 bottom locked value=0
R44 "MCT06030Z0000ZP500" 0603S 215.28,1783.21 r0 bottom locked value=0
R45 "CRCW04020000Z0ED" 0402S 322.87,1445.28 r180 bottom locked value=0
R46 "CRCW04024K70JNED" 0402 964.66,1683.21 r180 bottom locked value=4.7k
R47 "CRCW04024K70JNED" 0402 964.66,1748.23 r0 bottom locked value=4.7k
R48 "CRCW04020000Z0ED" 0402S 844.21,2080.64 r0 bottom locked value=0
R49 "CRCW040210K0FKED" 0402 964.66,1618.2 r0 bottom locked value=10.0k
R50 "CRCW040210K0FKED" 0402 215.19,1826.79 r180 bottom locked value=10.0k
R51 "CRCW040210K0FKED" 0402 215.19,1870.1 r180 bottom locked value=10.0k
R52 "CRCW04020000Z0ED" 0402S 322.87,2080.64 r180 bottom locked value=0
R53 "MCS0402MD1000BE100" 0402 3841.88,4840.22 r180 top locked value=100
R54 "CRCW040210K0FKED" 0402 211.08,1593.92 r180 bottom locked value=10.0k
R55 "CRCW040210K0FKED" 0402 1104.71,1618.2 r180 bottom locked value=10.0k
R56 "CRCW040210K0FKED" 0402 211.08,1637.22 r180 bottom locked value=10.0k
R57 "CRCW040210K0FKED" 0402 964.66,1813.25 r180 bottom locked value=10.0k
R58 "CRCW040210K0FKED" 0402 215.19,1913.4 r0 bottom locked value=10.0k
R59 "CRCW06031R00FKEA" 0603 4978.78,1012.69 r270 bottom locked value=1.00
R60 "CRCW06031K96FKEA" 0603 4912.9,1012.69 r90 bottom locked value=1.96k
R61 "CRCW040210K0FKED" 0402 3512.69,5068.29 r270 top locked value=10.0k
R62 "MCS0402MD1000BE100" 0402 3841.88,5025.87 r180 top locked value=100
R63 "CRCW04023R90JNED" 0402S 5652.14,824.13 r270 bottom locked value=3.9
R64 "CRCW04023R90JNED" 0402S 5256.39,824.13 r270 bottom locked value=3.9
R65 "CRCW04023R90JNED" 0402S 5652.14,1126.09 r90 bottom locked value=3.9
R66 "CRCW04023R90JNED" 0402S 5256.39,1126.09 r90 bottom locked value=3.9
R67 "CRCW04020000Z0ED" 0402S 5714.93,657.42 r0 bottom locked value=0
R68 "MCT06030Z0000ZP500" 0603S 5086.01,1000.35 r0 bottom locked value=0
R69 "CRCW04020000Z0ED" 0402S 5193.59,657.42 r180 bottom locked value=0
R70 "CRCW04024K70JNED" 0402 5835.38,895.36 r180 bottom locked value=4.7k
R71 "CRCW04024K70JNED" 0402 5835.38,960.38 r0 bottom locked value=4.7k
R72 "CRCW04020000Z0ED" 0402S 5714.93,1292.79 r0 bottom locked value=0
R73 "MCT06030Z0000ZP500" 0603 1112.58,1868.27 r180 bottom locked value=0
R74 "CRCW040210K0FKED" 0402 5085.91,1043.93 r180 bottom locked value=10.0k
R75 "MCT06030Z0000ZP500" 0603 5946.04,1090.42 r180 bottom locked value=0
R76 "CRCW04020000Z0ED" 0402S 5193.59,1292.79 r180 bottom locked value=0
R77 "MCS0402MD1000BE100" 0402 3841.88,5073.27 r180 top locked value=100
R78 "CRCW040210K0FKED" 0402S 5085.83,811.98 r180 bottom locked value=10.0k
R79 "CRCW040249R9FKED" 0402 4935.79,2752.44 r180 bottom locked value=49.9
R80 "CRCW040210K0FKED" 0402 5081.8,919.56 r180 bottom locked value=10.0k
R81 "CRCW040210K0FKED" 0402 5835.38,1025.4 r180 bottom locked value=10.0k
R82 "CRCW040249R9FKED" 0402 4871.88,3253.5 r0 bottom locked value=49.9
R83 "CRCW040249R9FKED" 0402 3910.28,3308.75 r0 bottom locked value=49.9
R84 "CRCW040249R9FKED" 0402 1454.53,2639.22 r270 bottom locked value=49.9
R85 "CRCW040249R9FKED" 0402 1360.26,3350.83 r90 bottom locked value=49.9
R86 "CRCW040210K0FKED" 0402 4434.39,279.21 r270 top locked value=10.0k
R87 "CRCW040210K0FKED" 0402 4292.19,279.21 r270 top locked value=10.0k
R88 "CRCW040210K0FKED" 0402 4740.84,279.21 r270 top locked value=10.0k
R89 "CRCW040210K0FKED" 0402 4598.64,279.21 r270 top locked value=10.0k
R90 "CRCW040210K0FKED" 0402 3841.88,4887.63 r0 top locked value=10.0k
R91 "CRCW040210K0FKED" 0402 3841.88,4745.42 r0 top locked value=10.0k
R92 "CRCW040210K0FKED" 0402 3841.88,5120.67 r0 top locked value=10.0k
R93 "CRCW040210K0FKED" 0402 3841.88,4978.47 r0 top locked value=10.0k
R94 "CRCW040210K0FKED" 0402 964.66,1868.27 r0 bottom locked value=10.0k
R95 "CRCW040210K0FKED" 0402 5835.38,1090.42 r0 bottom locked value=10.0k
R96 "MCT06030Z0000ZP500" 0603 203.2,1687.42 r0 bottom locked value=0
R97 "MCT06030Z0000ZP500" 0603 5073.93,869.37 r0 bottom locked value=0
R98 "CRCW04020000Z0EDHP" 0402S 2084.31,3275.06 r0 bottom locked value=0
R99 "CRCW04020000Z0EDHP" 0402S 1974.65,3335.1 r0 bottom locked value=0
R100 "CRCW04020000Z0EDHP" 0402S 4406.98,3179.22 r0 bottom locked value=0
R101 "CRCW04020000Z0EDHP" 0402S 4291.06,3218 r90 top locked value=0
R102 "CRCW04020000Z0EDHP" 0402S 3448.24,3353.71 r270 bottom locked value=0
R103 "CRCW040243R0JNED" 0402 2934.5,5110.83 r180 top locked value=43
R104 "CRCW040243R0JNED" 0402 2936.49,4744.94 r270 top locked value=43
R105 "ERJ-2RKF1152X" 0402 2837,4913.54 r0 bottom locked value=11.5k
R106 "CRCW040243R0JNED" 0402 3065.57,4939.13 r0 top locked value=43
R107 "ERJ-2GE0R00X" 0402 2588.37,4958.61 r0 top locked value=0
R108 "CRCW040243R0JNED" 0402 2986.58,4744.94 r270 top locked value=43
R109 "ERJ-2GE0R00X" 0402 2588.37,4909.65 r0 top locked value=0
R110 "ERJ-2RKF3091X" 0402 2837,4862.36 r180 bottom locked value=3.09k
R111 "ERJ-2RKF49R9X" 0402 2588.37,4860.7 r0 top locked value=49.9
R112 "CRCW04020000Z0EDHP" 0402S 3508.27,3437.99 r270 top locked value=0
R113 "CRCW04021K00FKED" 0402 2660.57,4910.51 r90 top locked value=1.00k
R114 "CRCW04020000Z0EDHP" 0402S 933.88,3215.9 r270 bottom locked value=0
R115 "ERJ-2GE0R00X" 0402 2822.43,5161.63 r180 top locked value=0
R116 "ERJ-2GE0R00X" 0402 2763.77,2687.68 r180 top locked value=0
R117 "ERJ-2GE0R00X" 0402 2822.43,5110.83 r180 top locked value=0
R118 "CRCW040210K0FKED" 0402 2805.64,4814.5 r0 top locked value=10.0k
R119 "CRCW040210K0FKED" 0402 2837,4964.72 r0 bottom locked value=10.0k
R120 "CRCW040210K0FKED" 0402 2837,5015.9 r0 bottom locked value=10.0k
R121 "ERJ-2GE0R00X" 0402 2740.15,2608.27 r90 top locked value=0
R122 "ERJ-2GE0R00X" 0402 2672.94,4787 r90 top locked value=0
R123 "ERJ-2GE0R00X" 0402 2725.57,4787 r90 top locked value=0
R124 "CRCW040210K0FKED" 0402 2805.64,4758.04 r180 top locked value=10.0k
R125 "CRCW04020000Z0EDHP" 0402S 781.74,3236.1 r0 bottom locked value=0
R126 "ERJ-2GE0R00X" 0402 4017.56,2749.57 r180 top locked value=0
R127 "CRCW02010000Z0ED" 0201 4047.24,2678.3 r90 top locked value=0
R128 "ERJ-2GE0R00X" 0402 2470.68,2608.27 r270 top locked value=0
R129 "ERJ-2GE0R00X" 0402 4863.64,2678.08 r180 top locked value=0
R130 "ERJ-2GE0R00X" 0402 3776.7,2634.28 r90 top locked value=0
R131 "ERJ-2GE0R00X" 0402 1448.73,2604.99 r180 top locked value=0
R132 "CRCW040243R0JNED" 0402 2106.16,3622.08 r270 bottom locked value=43
R133 "CRCW040243R0JNED" 0402 2155.48,3622.08 r270 bottom locked value=43
R134 "CRCW040243R0JNED" 0402 2382.92,3813.05 r0 bottom locked value=43
R135 "CRCW040243R0JNED" 0402 2081.68,3958.03 r90 bottom locked value=43
R136 "CH02016-100RGFT" 02016 3382.46,3626.25 r0 top locked value=100
R137 "CRCW040210K0FKED" 0402 2056.85,3622.08 r270 bottom locked value=10.0k
R138 "CRCW040210K0FKED" 0402 1979.32,3649.64 r0 bottom locked value=10.0k
R139 "CRCW040210K0FKED" 0402 1814.76,3878.29 r0 bottom locked value=10.0k
R140 "CH02016-100RGFT" 02016 2990.1,3868.26 r0 top locked value=100
R141 "CRCW040210K0FKED" 0402 1814.76,3796.29 r180 bottom locked value=10.0k
R142 "ERJ-2GE0R00X" 0402 1814.76,3960.29 r0 bottom locked value=0
R143 "ERJ-2GE0R00X" 0402 1814.76,3919.29 r0 bottom locked value=0
R144 "CRCW040210K0FKED" 0402 1814.76,3837.29 r0 bottom locked value=10.0k
R145 "ERJ-2GE0R00X" 0402 3501,4523.72 r270 bottom locked value=0
R146 "ERJ-2GE0R00X" 0402 3542,4523.72 r270 bottom locked value=0
R147 "CRCW040210K0FKED" 0402 3210.28,724 r180 top locked value=10.0k
R148 "CRCW040210K0FKED" 0402 3159,586.8 r90 bottom locked value=10.0k
R149 "CRCW040210K0FKED" 0402 3118,586.8 r90 bottom locked value=10.0k
R150 "CRCW040210K0FKED" 0402 2986,586.8 r270 bottom locked value=10.0k
R151 "CRCW040210K0FKED" 0402 3773.1,741.83 r270 top locked value=10.0k
R152 "CRCW040210K0FKED" 0402 3744,586.8 r90 bottom locked value=10.0k
R153 "CRCW040210K0FKED" 0402 3703,586.8 r90 bottom locked value=10.0k
R154 "CRCW04020000Z0EDHP" 0402S 2095.9,3139.1 r180 bottom locked value=0
R155 "CRCW040210K0FKED" 0402 3356.72,4360.87 r0 top locked value=10.0k
R156 "CRCW04020000Z0EDHP" 0402S 4540.6,3059.85 r180 bottom locked value=0
R157 "CRCW040210K0FKED" 0402 3414,4496.05 r270 bottom locked value=10.0k
R158 "CRCW04020000Z0EDHP" 0402S 3396.01,3122 r270 bottom locked value=0
R159 "CRCW040210K0FKED" 0402 3460,4499.97 r270 top locked value=10.0k
R160 "CRCW04020000Z0EDHP" 0402S 909,3102 r90 bottom locked value=0
R161 "CRCW040210K0FKED" 0402 2740.5,4495.09 r0 bottom locked value=10.0k
R162 "CRCW040210K0FKED" 0402 2819,4522.59 r270 bottom locked value=10.0k
R163 "CRCW040210K0FKED" 0402 2860,4522.59 r270 bottom locked value=10.0k
R164 "CRCW040210R0FKED" 0402 1686.31,3193.83 r270 bottom locked value=10.0
R165 "ERJ-2GE0R00X" 0402 1600.31,3097.85 r270 bottom locked value=0
R166 "CRCW04025K11FKED" 0402 3846.37,4570.25 r180 top locked value=5.11k
R167 "CRCW04025K11FKED" 0402 3647.62,4640.08 r0 bottom locked value=5.11k
R168 "CRCW04025K11FKED" 0402 3583,4523.63 r270 top locked value=5.11k
R169 "ERJ-2GE0R00X" 0402 3583,4523.63 r270 bottom locked value=0
R170 "ERJ-2GE0R00X" 0402 3624,4546.63 r270 top locked value=0
R171 "ERJ-2GE0R00X" 0402 3870,4546.63 r270 bottom locked value=0
R172 "ERJ-2GE0R00X" 0402 4097.47,3162.21 r270 bottom locked value=0
R173 "CRCW040210R0FKED" 0402 4220.47,3162.21 r270 bottom locked value=10.0
R174_1 "CRCW040210K0FKED" 0402 3200,586.8 r270 bottom locked value=10.0k (schematic designator R174)
R174_2 "CRCW040210K0FKED" 0402 3662,586.8 r270 bottom locked value=10.0k (schematic designator R174)
R174_3 "CRCW040210K0FKED" 0402 3346,4519.62 r90 bottom locked value=10.0k (schematic designator R174)
R174_4 "CRCW040210K0FKED" 0402 2903,4522.59 r90 bottom locked value=10.0k (schematic designator R174)
R175_1 "CRCW0402100KFKED" 0402 2827.21,594.52 r270 bottom locked value=100k (schematic designator R175)
R175_2 "CRCW0402100KFKED" 0402 3457,602.84 r270 top locked value=100k (schematic designator R175)
R175_3 "CRCW0402100KFKED" 0402 3747,4546.63 r90 bottom locked value=100k (schematic designator R175)
R175_4 "CRCW0402100KFKED" 0402 3130.51,4516.07 r90 top locked value=100k (schematic designator R175)
R176_1 "CRCW040210K0FKED" 0402 2827.21,604.52 r270 top locked value=10.0k (schematic designator R176)
R176_2 "CRCW040210K0FKED" 0402 3293,586.8 r270 bottom locked value=10.0k (schematic designator R176)
R176_3 "CRCW040210K0FKED" 0402 3829,4546.63 r90 bottom locked value=10.0k (schematic designator R176)
R176_4 "CRCW040210K0FKED" 0402 3215.4,4563.99 r90 top locked value=10.0k (schematic designator R176)
R177_1 "CRCW040210K0FKED" 0402S 2076.4,3086 r180 top locked value=10.0k (schematic designator R177)
R177_2 "CRCW040210K0FKED" 0402S 4394.4,2995 r180 top locked value=10.0k (schematic designator R177)
R177_3 "CRCW040210K0FKED" 0402S 3391.4,3086 r180 top locked value=10.0k (schematic designator R177)
R177_4 "CRCW040210K0FKED" 0402S 906.4,2995 r180 top locked value=10.0k (schematic designator R177)
R178_1 "CRCW0402100KFKED" 0402 3066.72,764 r0 top locked value=100k (schematic designator R178)
R178_2 "CRCW0402100KFKED" 0402 3498,586.8 r270 bottom locked value=100k (schematic designator R178)
R178_3 "CRCW0402100KFKED" 0402 3460,4496.05 r90 bottom locked value=100k (schematic designator R178)
R178_4 "CRCW0402100KFKED" 0402 3108,4522.59 r90 bottom locked value=100k (schematic designator R178)
R179_1 "CRCW0402100KFKED" 0402 3067,586.8 r270 bottom locked value=100k (schematic designator R179)
R179_2 "CRCW0402100KFKED" 0402 3457,586.8 r270 bottom locked value=100k (schematic designator R179)
R179_3 "CRCW0402100KFKED" 0402 3578.91,3400.96 r90 bottom locked value=100k (schematic designator R179)
R179_4 "CRCW0402100KFKED" 0402 3149,4522.59 r90 bottom locked value=100k (schematic designator R179)
R180_1 "CRCW04024K70JNED" 0402S 2088,3286 r180 top locked value=4.7k (schematic designator R180)
R180_2 "CRCW04024K70JNED" 0402S 4405.91,3197 r180 top locked value=4.7k (schematic designator R180)
R180_3 "CRCW04024K70JNED" 0402S 3402.91,3286 r180 top locked value=4.7k (schematic designator R180)
R180_4 "CRCW04024K70JNED" 0402S 917.91,3197 r180 top locked value=4.7k (schematic designator R180)
R181_1 "CRCW04024K70JNED" 0402S 2063.84,3328.23 r270 bottom locked value=4.7k (schematic designator R181)
R181_2 "CRCW04024K70JNED" 0402S 4386.19,3236.41 r270 bottom locked value=4.7k (schematic designator R181)
R181_3 "CRCW04024K70JNED" 0402S 3349.08,3306 r270 top locked value=4.7k (schematic designator R181)
R181_4 "CRCW04024K70JNED" 0402S 899.06,3215.9 r270 bottom locked value=4.7k (schematic designator R181)
R182_1 "CRCW0402100KFKED" 0402 2909.21,594.52 r90 bottom locked value=100k (schematic designator R182)
R182_2 "CRCW0402100KFKED" 0402 3416,586.8 r90 bottom locked value=100k (schematic designator R182)
R182_3 "CRCW0402100KFKED" 0402 3665,4546.63 r270 bottom locked value=100k (schematic designator R182)
R182_4 "CRCW0402100KFKED" 0402 3148.67,4226.15 r180 top locked value=100k (schematic designator R182)
R183_1 "CRCW0402100KFKED" 0402 2868.21,594.52 r90 bottom locked value=100k (schematic designator R183)
R183_2 "CRCW0402100KFKED" 0402 3375,586.8 r90 bottom locked value=100k (schematic designator R183)
R183_3 "CRCW0402100KFKED" 0402 3706,4546.63 r270 bottom locked value=100k (schematic designator R183)
R183_4 "CRCW0402100KFKED" 0402 3221.67,4267.15 r180 top locked value=100k (schematic designator R183)
R184_1 "CRCW040210K0FKED" 0402 2820,739.62 r270 top locked value=10.0k (schematic designator R184)
R184_2 "CRCW040210K0FKED" 0402 3334,586.8 r90 bottom locked value=10.0k (schematic designator R184)
R184_3 "CRCW040210K0FKED" 0402 3788,4546.63 r270 bottom locked value=10.0k (schematic designator R184)
R184_4 "CRCW040210K0FKED" 0402 3196.34,4363.65 r90 top locked value=10.0k (schematic designator R184)
R185_1 "CRCW040210K0FKED" 0402S 2155.9,3101 r270 bottom locked value=10.0k (schematic designator R185)
R185_2 "CRCW040210K0FKED" 0402S 4473.9,3001.05 r270 bottom locked value=10.0k (schematic designator R185)
R185_3 "CRCW040210K0FKED" 0402S 3482.96,3086.54 r270 bottom locked value=10.0k (schematic designator R185)
R185_4 "CRCW040210K0FKED" 0402S 985.9,3007 r270 bottom locked value=10.0k (schematic designator R185)
R186 "ERJ-2GE0R00X" 0402S 2765.21,2834.89 r0 top locked value=0
R187 "ERJ-2GE0R00X" 0402S 4024.71,2807.84 r180 top locked value=0
R188_1 "PMR10EZPJ000" 0805L 2807.55,3268.2 r270 top locked value=0 (schematic designator R188)
R188_2 "PMR10EZPJ000" 0805L 5124.3,3154.07 r0 top locked value=0 (schematic designator R188)
R188_3 "PMR10EZPJ000" 0805L 4087.03,3282.1 r90 top locked value=0 (schematic designator R188)
R188_4 "PMR10EZPJ000" 0805L 1616.77,3195.6 r270 top locked value=0 (schematic designator R188)
R189 "MCS0402MD1000BE100" 0402 4339.59,279.21 r90 top locked value=100
R190 "MCS0402MD1000BE100" 0402 4693.44,279.21 r90 top locked value=100
R191 "MCS0402MD1000BE100" 0402 4386.99,279.21 r90 top locked value=100
R192 "ERJ-2GEJ511X" 0402 286.98,353.83 r0 top locked value=510
R193 "ERJ-2GEJ361X" 0402 5927.52,3557.54 r180 top locked value=360
R194 "ERJ-2GEJ511X" 0402 86.98,353.83 r0 top locked value=510
R195 "ERJ-2GEJ511X" 0402 216.13,551.51 r270 top locked value=510
R196 "ERJ-2GEJ511X" 0402 4387.85,971.8 r180 top locked value=510
R197 "ERJ-2GEJ511X" 0402 4694.3,971.8 r180 top locked value=510
R198 "ERJ-2GEJ511X" 0402 4340.61,691.84 r0 top locked value=510
R199 "ERJ-2GEJ511X" 0402 4647.06,691.84 r0 top locked value=510
R200 "ERJ-2GEJ511X" 0402 4847.52,971.8 r180 top locked value=510
R201 "ERJ-2GEJ511X" 0402 4541.07,971.8 r180 top locked value=510
R202 "ERJ-2GEJ511X" 0402 4753.04,691.84 r180 top locked value=510
R203 "ERJ-2GEJ511X" 0402 4446.59,691.84 r180 top locked value=510
R204 "ERJ-2GE0R00X" 0402 3890.62,4020.74 r0 top locked value=0
R205 "ERJ-2GE0R00X" 0402 3890.62,3971.03 r0 top locked value=0
R206 "CRCW040210K0FKED" 0402 4387.85,587.15 r180 top locked value=10.0k
R207 "CRCW040210K0FKED" 0402 4694.3,587.15 r180 top locked value=10.0k
R208 "ERJ-2GE0R00X" 0402 4387.85,634.4 r180 top locked value=0
R209 "ERJ-2GE0R00X" 0402 4694.3,634.4 r180 top locked value=0
R210 "ERJ-2GE0R00X" 0402 3461.75,5068.29 r270 top locked value=0
R211 "ERJ-2GE0R00X" 0402 3461.75,4835.24 r270 top locked value=0
R212 "MCS0402MD1000BE100" 0402 4646.04,279.21 r90 top locked value=100
R213 "ERJ-2GE0R00X" 0402S 2198.59,3052.15 r180 bottom locked value=0
R214 "ERJ-2GE0R00X" 0402S 2198.59,3016.15 r180 bottom locked value=0
TP1_1 "TP_SM_1MM" TP_SM_1MM 1709.4,3919.29 r270 bottom locked (schematic designator TP1)
TP1_2 "TP_SM_1MM" TP_SM_1MM 3754,481.94 r90 bottom locked (schematic designator TP1)
TP1_3 "TP_SM_1MM" TP_SM_1MM 3394.61,4611.81 r270 bottom locked (schematic designator TP1)
TP1_4 "TP_SM_1MM" TP_SM_1MM 2772.45,4577.44 r90 bottom locked (schematic designator TP1)
TP2_1 "TP_SM_1MM" TP_SM_1MM 885.78,1813.25 r90 bottom locked (schematic designator TP2)
TP2_2 "TP_SM_1MM" TP_SM_1MM 3693,481.94 r90 bottom locked (schematic designator TP2)
TP2_3 "TP_SM_1MM" TP_SM_1MM 3469.4,4629.14 r90 bottom locked (schematic designator TP2)
TP2_4 "TP_SM_1MM" TP_SM_1MM 2860,4628.72 r90 bottom locked (schematic designator TP2)
TP3_1 "TP_SM_1MM" TP_SM_1MM 3245.73,506.43 r90 bottom locked (schematic designator TP3)
TP3_2 "TP_SM_1MM" TP_SM_1MM 3826.26,643.17 r90 bottom locked (schematic designator TP3)
TP3_3 "TP_SM_1MM" TP_SM_1MM 3272.86,4503.14 r90 bottom locked (schematic designator TP3)
TP3_4 "TP_SM_1MM" TP_SM_1MM 2716.88,4548.68 r90 bottom locked (schematic designator TP3)
TP4 "TP_SM_1MM" TP_SM_1MM 293.43,1859.32 r0 bottom locked
TP5 "TP_SM_1MM" TP_SM_1MM 3118,477.19 r270 bottom locked
TP6 "TP_SM_1MM" TP_SM_1MM 885.78,1618.2 r180 bottom locked
TP7 "TP_SM_1MM" TP_SM_1MM 293.43,1666.6 r0 bottom locked
TP8 "TP_SM_1MM" TP_SM_1MM 2854.35,4025.61 r90 bottom locked
TP9 "TP_SM_1MM" TP_SM_1MM 885.78,1748.23 r180 bottom locked
TP10 "TP_SM_1MM" TP_SM_1MM 885.78,1683.21 r180 bottom locked
TP11 "TP_SM_1MM" TP_SM_1MM 293.43,1730.84 r0 bottom locked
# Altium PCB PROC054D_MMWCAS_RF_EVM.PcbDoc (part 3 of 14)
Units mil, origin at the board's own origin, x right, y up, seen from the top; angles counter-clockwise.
Board outline 6299.21 x 5370.07 mil, 8 copper layers (L1 TOP, L2 GND, L3 SIGNAL 1, L4 GND, L5 SIGNAL 2, L6 SIGNAL 3, L7 GND, L8 BOTTOM), stack 53.5 mil thick; 775 components, 552 nets, 2648 pads, 7845 vias.

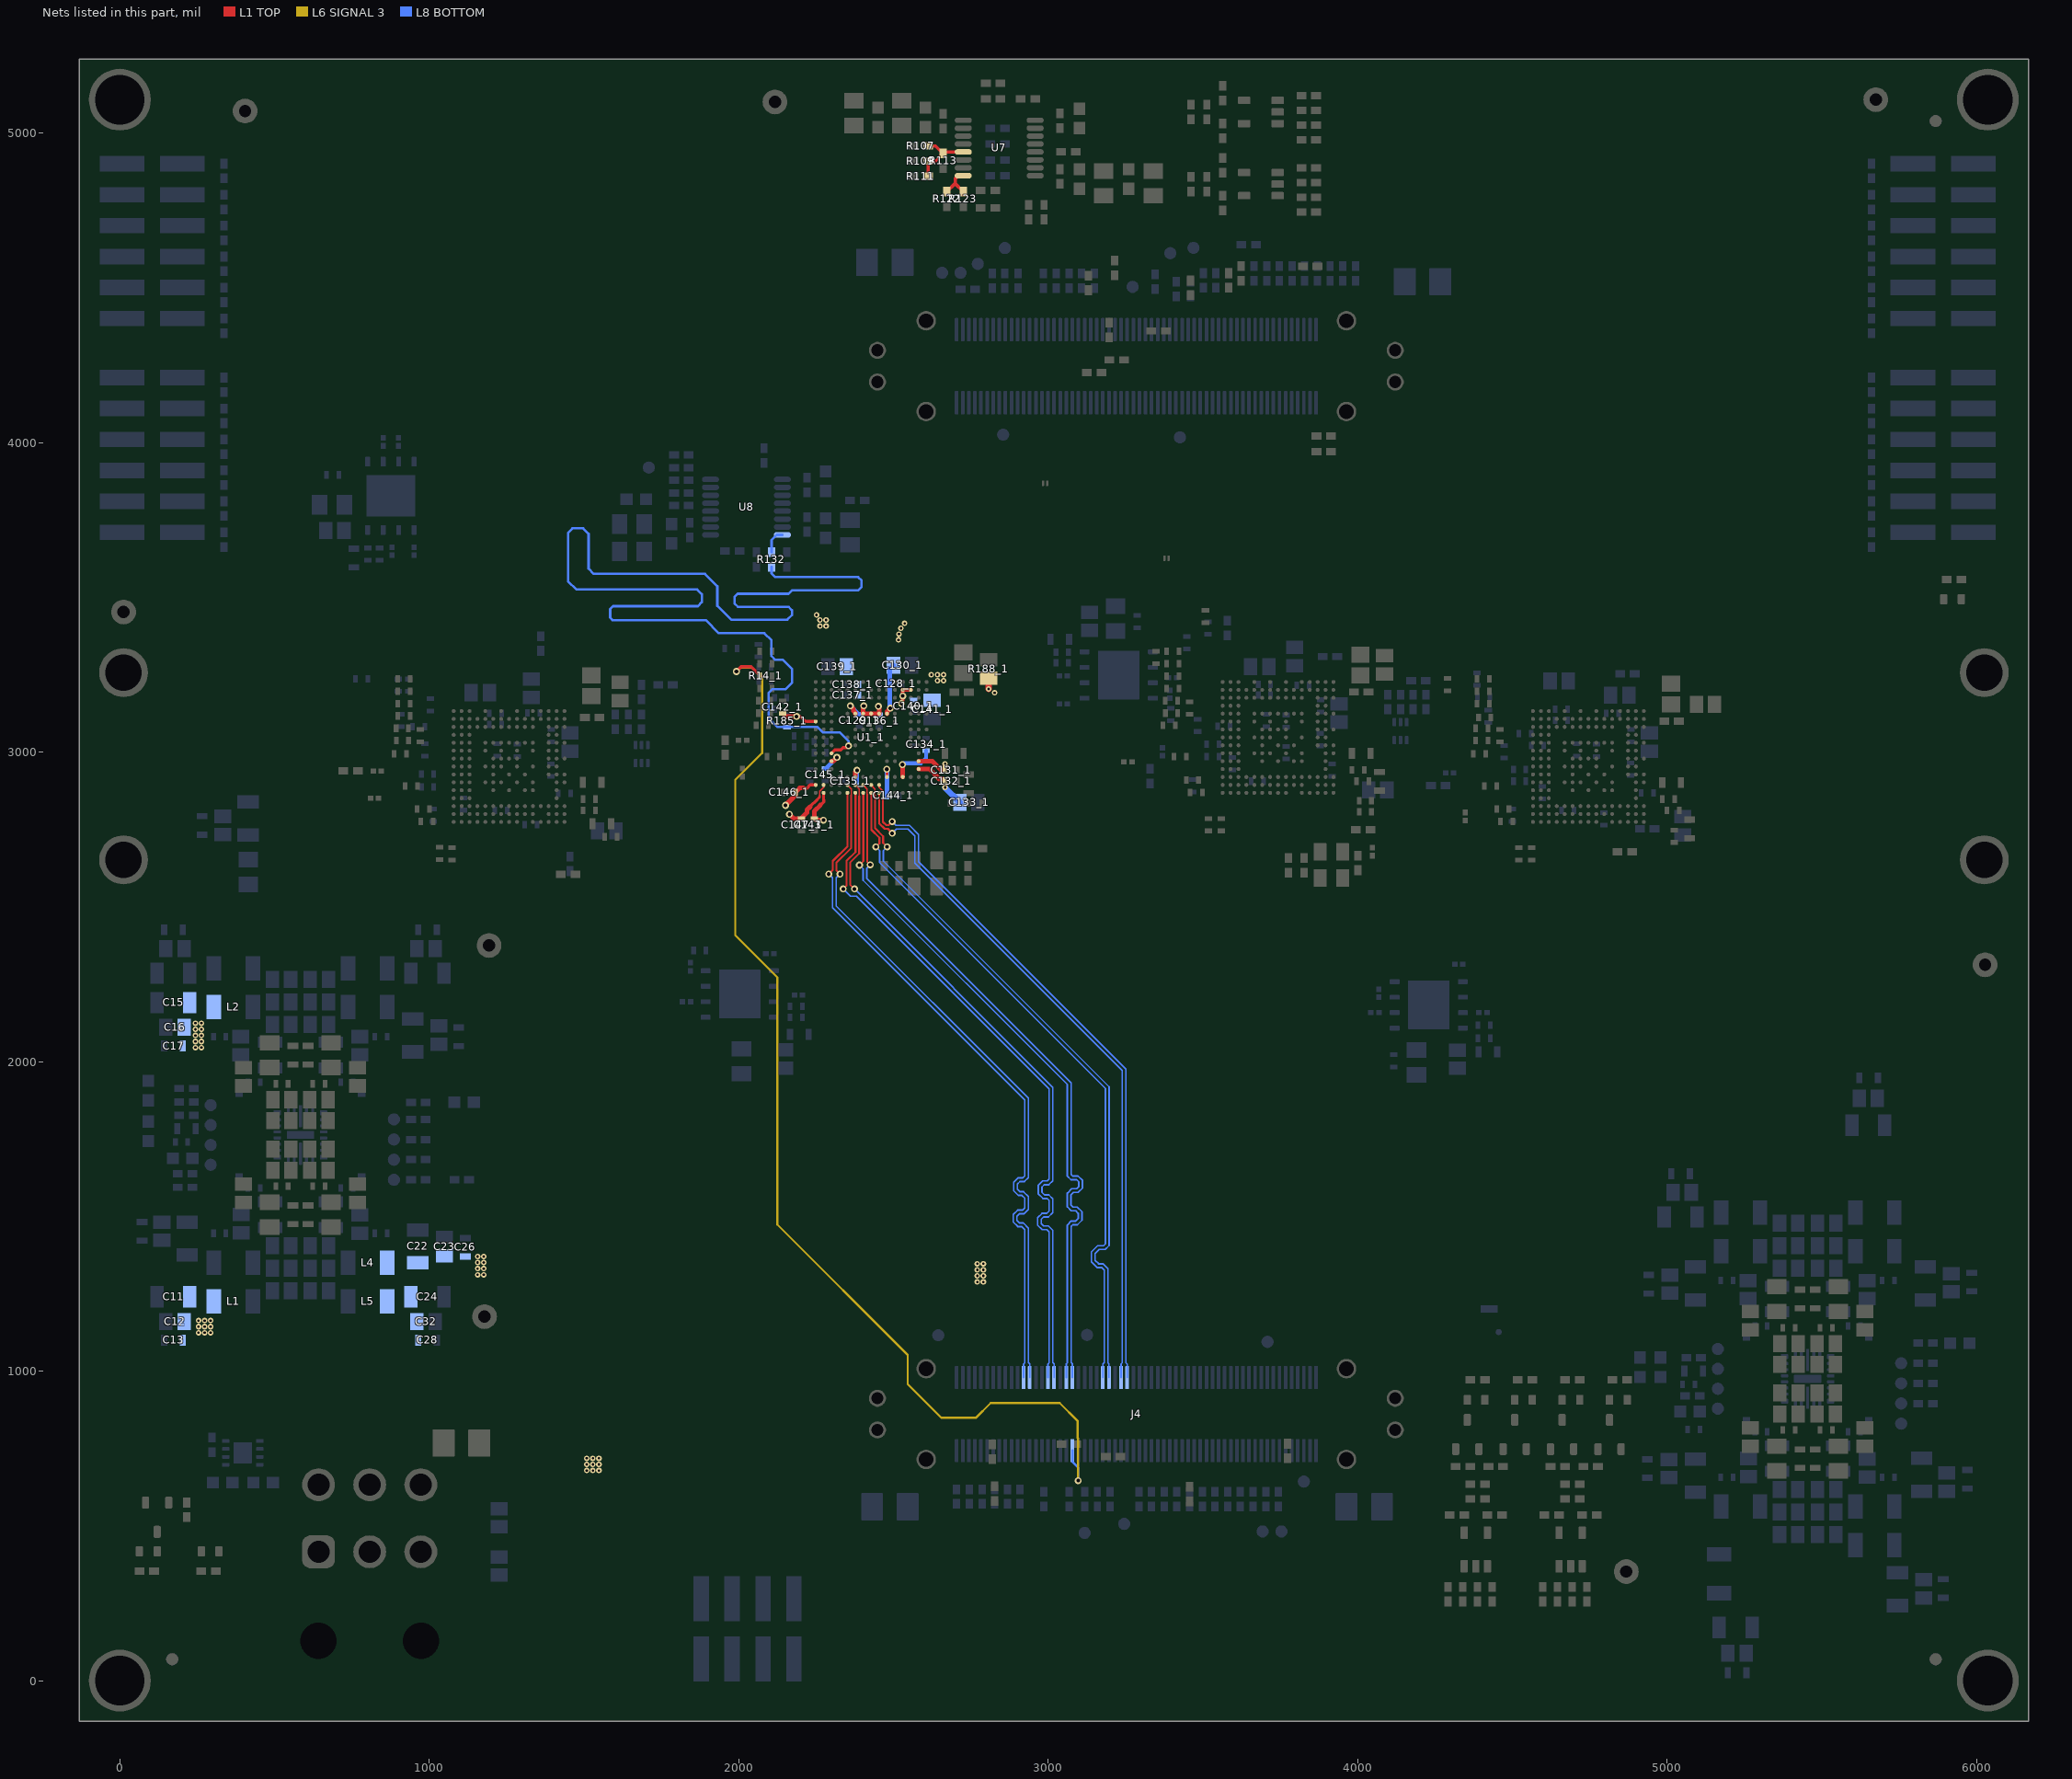
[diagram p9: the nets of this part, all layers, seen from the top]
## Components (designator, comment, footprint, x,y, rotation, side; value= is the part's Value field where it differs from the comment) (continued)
TP12 "TP_SM_1MM" TP_SM_1MM 3125.61,1116.7 r90 bottom locked
TP13 "TP_SM_1MM" TP_SM_1MM 3425.79,4016.95 r90 bottom locked
TP14 "TP_SM_1MM" TP_SM_1MM 293.43,1795.08 r90 bottom locked
TP15 "TP_SM_1MM" TP_SM_1MM 3709,1094.73 r90 bottom locked
TP16 "5001" Keystone5001 12.11,3452.63 r90 bottom
TP17 "5001" Keystone5001 2117.05,5100.49 r90 bottom
TP18 "5001" Keystone5001 6027.77,2312.91 r90 bottom
TP19 "5001" Keystone5001 1193.1,2375.16 r180 bottom locked
TP20 "5001" Keystone5001 4868.23,352.27 r90 bottom locked
TP21 "TP_SM_1MM" TP_SM_1MM 5164.16,1071.47 r0 bottom locked
TP22 "TP_SM_1MM" TP_SM_1MM 5756.51,1025.4 r180 bottom locked
TP23 "TP_SM_1MM" TP_SM_1MM 5756.51,830.34 r0 bottom locked
TP24 "TP_SM_1MM" TP_SM_1MM 5164.16,878.74 r0 bottom locked
TP25 "5001" Keystone5001 1178.5,1176.1 r90 bottom locked
TP26 "TP_SM_1MM" TP_SM_1MM 5756.51,960.38 r0 bottom locked
TP27 "TP_SM_1MM" TP_SM_1MM 5756.51,895.36 r90 bottom locked
TP28 "TP_SM_1MM" TP_SM_1MM 5164.16,942.99 r180 bottom locked
TP29 "5001" Keystone5001 404.68,5071.3 r90 bottom locked
TP30 "5001" Keystone5001 5674.54,5108 r90 bottom locked
TP31 "TP_SM_1MM" TP_SM_1MM 5164.16,1007.23 r0 bottom locked
TP32 "TP_SM_1MM" TP_SM_1MM 2645.03,1115.91 r90 bottom locked
TP33 "TP_SM_1MM" TP_SM_1MM 2657.29,4548.68 r270 bottom locked
U1_1 "XA2243PBGABL" ABL0161A 2427.89,3047.5 r270 top locked (schematic designator U1)
U1_2 "XA2243PBGABL" ABL0161A 4745.89,2953.5 r270 top locked (schematic designator U1)
U1_3 "XA2243PBGABL" ABL0161A 3742.89,3047.5 r270 top locked (schematic designator U1)
U1_4 "XA2243PBGABL" ABL0161A 1257.89,2953.5 r270 top locked (schematic designator U1)
U2_1 "MX25V1635FZNQ" WSON-8L_6x5MM_EP 2003.3,2218.45 r0 bottom locked (schematic designator U2)
U2_2 "MX25V1635FZNQ" WSON-8L_6x5MM_EP 4229.96,2183.17 r0 bottom locked (schematic designator U2)
U2_3 "MX25V1635FZNQ" WSON-8L_6x5MM_EP 3227.96,3249 r180 bottom locked (schematic designator U2)
U2_4 "MX25V1635FZNQ" WSON-8L_6x5MM_EP 875.89,3828.1 r270 bottom locked (schematic designator U2)
U3 "LP87524PRNFTQ1" RNF0026C 583.54,1762.96 r180 bottom locked
U4 "LP87524PRNFTQ1" RNF0026C 5454.26,975.11 r180 bottom locked
U5 "TPS73733QDRBRQ1" DRB0008A 397.12,735.77 r0 bottom locked
U6 "SN74LVC1G08QDBVRQ1" DBV0005A_N 4381.99,423.71 r90 top locked
U7 "LMK00804BPW" PW0016A_N 2841.71,4951.93 r0 top locked
U8 "LMK00804BPW" PW0016A_N 2025.04,3791.39 r0 bottom locked
U9 "TMP112AIDRLR" DRL0006A 1686.3,2993.69 r90 bottom locked
U10 "TMP112AIDRLR" DRL0006A 4138.46,3067.69 r90 bottom locked
U11 "SN74LVC1G08QDBVRQ1" DBV0005A_N 4688.44,423.71 r90 top locked
U12 "SN74LVC1G08QDBVRQ1" DBV0005A_N 3687.37,4835.22 r180 top locked
U13 "SN74LVC1G08QDBVRQ1" DBV0005A_N 3687.37,5068.27 r180 top locked
Y1 "CX3225SA40000D0PTWCC" Kyocera_CX3225SA 2603.53,2608 r0 top locked
Y2 "CX3225SA40000D0PTWCC" Kyocera_CX3225SA 3915.34,2635.31 r0 top locked
ZZ1 "These assemblies AWRe ESD sensitive, ESD precautions shall be observed." AssemblyNote 450,6075 r0 top
ZZ2 "These assemblies must be clean and free from flux and all contaminants. Use of no clean flux is not acceptable." AssemblyNote 450,5975 r0 top
ZZ3 "These assemblies must comply with workmanship standAWRds IPC-A-610 Class 2, unless otherwise specified." AssemblyNote 450,5875 r0 top
ZZ4 "R136/R140 require special attention due to no solder-mask RF construction. For any questions, please contact TI design team." AssemblyNote 450,5775 r0 top

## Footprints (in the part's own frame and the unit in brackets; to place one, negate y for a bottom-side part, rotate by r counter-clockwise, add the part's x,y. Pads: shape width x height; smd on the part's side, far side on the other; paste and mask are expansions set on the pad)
19S101_40ML5 [mil] "Connector, RF 50 Ohm Impedance"
  rect 23.62x55.12 smd: 1(0,-110.24)
  round 20 smd: 2(-75,-79)
  L1 TOP region: -102.36,102.36 102.36,102.36 102.36,-102.36 39.37,-102.36 39.37,-69.5 39.04,-69.08 66.35,-43.44 78.82,-8.13 73.67,28.97 52.05,59.55 18.79,76.77 -18.66,76.79 -51.93,59.59 -73.58,29.03 -78.76,-8.07 -66.31,-43.39 -39.03,-69.05 -39.03,-69.05 -39.37,-69.05 -39.37,-102.36 -102.36,-102.36
  body extent -98,-98 98,98, height 161
0201 [mm] "Data from Kemet datasheet CC101_COM dated 7/28/11"
  rect 0.46x0.42 smd: 1(-0.33,0) 2(0.33,0)
  body extent -0.31,-0.16 0.31,0.16, height 0.26
0402 [mm] "0402 from SM-752 data"
  rect 0.8x0.6 smd: 1(-0.6,0) 2(0.6,0)
  silkscreen extent -1.22,-0.52 1.22,0.52, body extent -0.55,-0.3 0.55,0.3, height 0.6
0402S [mil] "Based on C0402S footprint from PADS legacy"
  rect 15x24 smd: 1(-20,0) 2(20,0)
  body extent -22,-12 22,12, height 24
0603 [mm] "0603 from SM-752 data"
  rect 1x0.95 smd: 1(-0.8,0) 2(0.8,0)
  silkscreen extent -1.52,-0.69 1.52,0.69, body extent -0.87,-0.47 0.87,0.47, height 1
0603S [mil]
  rect 20x35 smd: 1(-30,0) 2(30,0)
  body extent -34,-19 34,19, height 39
0805 [mm] "0805 from SM-752 data"
  rect 1.3x1.5 smd: 1(-0.85,0) 2(0.85,0)
  silkscreen extent -1.72,-0.97 1.72,0.97, body extent -1.1,-0.72 1.1,0.72, height 1.45
0805_HV [mil] "0805 with 30mil clearance between pads"
  rect 50x63 smd: 1(-40,0) 2(40,0)
  silkscreen extent -74,-40 74,40, body extent -43,-29 43,29, height 57
0805L [mm] "0805 from SM-752 data"
  rect 1.1x1.4 smd: 1(-0.75,0) 2(0.75,0)
  body extent -1.1,-0.72 1.1,0.72, height 1.45
1206_180L [mm] "1206_180"
  rect 1.1x1.75 smd: 1(-1.35,0) 2(1.35,0)
  silkscreen extent -0.4,-0.77 0.4,0.77, body extent -1.75,-0.95 1.75,0.95, height 1.8
02016 [mm] "SMD, 2-Leads, Body 0.48x0.39mm"
  rrect53% 0.19x0.44 smd: 1(-0.17,0) 2(0.17,0)
  body extent -0.29,-0.25 0.29,0.25, height 0.55
3528-21 [mm] "Medium Density IPC, based on Kemet datasheet 2016-10-20"
  rrect6% 1.8x2.23 smd: 1(-1.46,0) 2(1.46,0)
  silkscreen extent -2.29,-1.5 0.76,1.5, body extent -1.85,-1.5 1.85,1.5, height 2.12
ABL0161A [mm] "BGA, 161-Balls, Body 10.4x10.4mm, Pitch 0.65mm"
  round 0.32 smd mask+0.05: A1(-4.55,4.55) A2(-3.9,4.55) A3(-3.25,4.55) A5(-1.95,4.55) A7(-0.65,4.55) A9(0.65,4.55) A10(1.3,4.55) A13(3.25,4.55) A14(3.9,4.55) A15(4.55,4.55) B1(-4.55,3.9) B2(-3.9,3.9) B3(-3.25,3.9) B4(-2.6,3.9) B5(-1.95,3.9) B6(-1.3,3.9) B7(-0.65,3.9) B8(0,3.9) B9(0.65,3.9) B10(1.3,3.9) B11(1.95,3.9) B12(2.6,3.9) B13(3.25,3.9) B14(3.9,3.9) B15(4.55,3.9) C1(-4.55,3.25) C2(-3.9,3.25) C3(-3.25,3.25) C4(-2.6,3.25) C5(-1.95,3.25) C6(-1.3,3.25) C7(-0.65,3.25) C8(0,3.25) C9(0.65,3.25) C13(3.25,3.25) C14(3.9,3.25) C15(4.55,3.25) D1(-4.55,2.6) D2(-3.9,2.6) D13(3.25,2.6) D15(4.55,2.6) E1(-4.55,1.95) E2(-3.9,1.95) E3(-3.25,1.95) E5(-1.95,1.95) E6(-1.3,1.95) E8(0,1.95) E10(1.3,1.95) E11(1.95,1.95) E13(3.25,1.95) E14(3.9,1.95) E15(4.55,1.95) F2(-3.9,1.3) F3(-3.25,1.3) F5(-1.95,1.3) F9(0.65,1.3) F11(1.95,1.3) F13(3.25,1.3) F14(3.9,1.3) G1(-4.55,0.65) G2(-3.9,0.65) G3(-3.25,0.65) G5(-1.95,0.65) G6(-1.3,0.65) G7(-0.65,0.65) G8(0,0.65) G10(1.3,0.65) G13(3.25,0.65) G14(3.9,0.65) G15(4.55,0.65) H2(-3.9,0) H3(-3.25,0) H5(-1.95,0) H7(-0.65,0) H9(0.65,0) H11(1.95,0) H13(3.25,0) H14(3.9,0) H15(4.55,0) J1(-4.55,-0.65) J2(-3.9,-0.65) J3(-3.25,-0.65) J5(-1.95,-0.65) J6(-1.3,-0.65) J7(-0.65,-0.65) J8(0,-0.65) J10(1.3,-0.65) J13(3.25,-0.65) J14(3.9,-0.65) J15(4.55,-0.65) K2(-3.9,-1.3) K3(-3.25,-1.3) K5(-1.95,-1.3) K7(-0.65,-1.3) K8(0,-1.3) K9(0.65,-1.3) K10(1.3,-1.3) K11(1.95,-1.3) K13(3.25,-1.3) K14(3.9,-1.3) K15(4.55,-1.3) L1(-4.55,-1.95) L2(-3.9,-1.95) L3(-3.25,-1.95) L5(-1.95,-1.95) L6(-1.3,-1.95) L8(0,-1.95) L10(1.3,-1.95) L13(3.25,-1.95) L14(3.9,-1.95) L15(4.55,-1.95) M2(-3.9,-2.6) M3(-3.25,-2.6) M13(3.25,-2.6) M14(3.9,-2.6) M15(4.55,-2.6) N1(-4.55,-3.25) N2(-3.9,-3.25) N3(-3.25,-3.25) N4(-2.6,-3.25) N5(-1.95,-3.25) N6(-1.3,-3.25) N7(-0.65,-3.25) N8(0,-3.25) N9(0.65,-3.25) N10(1.3,-3.25) N11(1.95,-3.25) N12(2.6,-3.25) N13(3.25,-3.25) N14(3.9,-3.25) N15(4.55,-3.25) P1(-4.55,-3.9) P2(-3.9,-3.9) P3(-3.25,-3.9) P4(-2.6,-3.9) P5(-1.95,-3.9) P6(-1.3,-3.9) P7(-0.65,-3.9) P8(0,-3.9) P9(0.65,-3.9) P10(1.3,-3.9) P11(1.95,-3.9) P12(2.6,-3.9) P13(3.25,-3.9) P14(3.9,-3.9) P15(4.55,-3.9) R1(-4.55,-4.55) R2(-3.9,-4.55) R3(-3.25,-4.55) R4(-2.6,-4.55) R5(-1.95,-4.55) R6(-1.3,-4.55) R7(-0.65,-4.55) R8(0,-4.55) R9(0.65,-4.55) R10(1.3,-4.55) R11(1.95,-4.55) R12(2.6,-4.55) R13(3.25,-4.55) R14(3.9,-4.55) R15(4.55,-4.55)
  silkscreen extent -5.3,-5.3 5.3,5.3, body extent -5.2,-5.2 5.2,5.2, height 0.62
AssemblyNote [mil] "Assembly Note"
CE_Mark_5mm [mil] "Minimum text height for CE Mark"
  silkscreen extent -138,-98 138,98
DBV0005A_N [mm] "SOT23, 5-Leads, Body 2.9x1.6mm, Pitch 0.95mm, Lead Span 2.8mm, IPC Medium Density"
  rrect17% 1x0.6 smd: 1(-1.375,0.95) 2(-1.375,0) 3(-1.375,-0.95) 4(1.375,-0.95) 5(1.375,0.95)
  silkscreen extent -0.25,-1.55 0.25,1.55, body extent -1.42,-1.46 1.42,1.46, height 1.09
DFE252012P [mm] "TOKO, Pad sizes increased as per request"
  rect 0.9x2 smd: 1(-1.05,0) 2(1.05,0)
  silkscreen extent -0.3,-1.2 0.3,1.2, body extent -1.35,-1.1 1.35,1.1, height 1.2
DRB0008A [mm] "SON, 8-Leads, Body 3x3mm, Pitch 0.65mm, Thermal Pad 1.75x1.5mm, TI Recommended"
  rrect33% 0.6x0.3 smd: 1(-1.4,0.975) 2(-1.4,0.325) 3(-1.4,-0.325) 4(-1.4,-0.975) 5(1.4,-0.975) 6(1.4,-0.325) 7(1.4,0.325) 8(1.4,0.975)
  rrect7% 1.5x1.75 smd paste-0.75: 9(0,0)
  L1 TOP region: -0.465,-1.5 -0.465,-0.875 -0.75,-0.875 -0.75,0.875 -0.465,0.875 -0.465,1.5 -0.185,1.5 -0.185,0.875 0.185,0.875 0.185,1.5 0.465,1.5 0.465,0.875 0.75,0.875 0.75,-0.875 0.465,-0.875 0.465,-1.5 0.185,-1.5 0.185,-0.875 -0.185,-0.875 -0.185,-1.5
  silkscreen extent -1.73,-1.73 1.73,1.73, body extent -1.58,-1.57 1.57,1.58, height 1.01
DRL0006A [mm] "SOTFL, 6-Flat Leads, Body 1.2x1.6x0.6mm, Pitch 0.5mm, TI recommended"
  rrect33% 0.67x0.3 smd: 1(-0.74,0.5) 2(-0.74,0) 3(-0.74,-0.5) 4(0.74,-0.5) 5(0.74,0) 6(0.74,0.5)
  silkscreen extent -0.9,-0.95 0.5,0.95, body extent -0.8,-0.8 0.8,0.8, height 0.61
ESD_Overlay_Large [mil]
  silkscreen extent -254,-219 250,219
FCC_disclaimer [mil]
Fiducial10-20 [mm]
  round 1 smd mask+0.5: 1(0,0)
  L1 TOP keep-out circle w1.178: c0,0 r0.5
Hirose_FX23-120P-0_5SV15 [mm] "Header(shrouded), 0.5mm, 60x2, SMT"
  rrect33% 1.9x0.3 smd: 1(-3,14.75) 2(-3,14.25) 3(-3,13.75) 4(-3,13.25) 5(-3,12.75) 6(-3,12.25) 7(-3,11.75) 8(-3,11.25) 9(-3,10.75) 10(-3,10.25) 11(-3,9.75) 12(-3,9.25) 13(-3,8.75) 14(-3,8.25) 15(-3,7.75) 16(-3,7.25) 17(-3,6.75) 18(-3,6.25) 19(-3,5.75) 20(-3,5.25) 21(-3,4.75) 22(-3,4.25) 23(-3,3.75) 24(-3,3.25) 25(-3,2.75) 26(-3,2.25) 27(-3,1.75) 28(-3,1.25) 29(-3,0.75) 30(-3,0.25) 31(-3,-0.25) 32(-3,-0.75) 33(-3,-1.25) 34(-3,-1.75) 35(-3,-2.25) 36(-3,-2.75) 37(-3,-3.25) 38(-3,-3.75) 39(-3,-4.25) 40(-3,-4.75) 41(-3,-5.25) 42(-3,-5.75) 43(-3,-6.25) 44(-3,-6.75) 45(-3,-7.25) 46(-3,-7.75) 47(-3,-8.25) 48(-3,-8.75) 49(-3,-9.25) 50(-3,-9.75) 51(-3,-10.25) 52(-3,-10.75) 53(-3,-11.25) 54(-3,-11.75) 55(-3,-12.25) 56(-3,-12.75) 57(-3,-13.25) 58(-3,-13.75) 59(-3,-14.25) 60(-3,-14.75) 61(3,14.75) 62(3,14.25) 63(3,13.75) 64(3,13.25) 65(3,12.75) 66(3,12.25) 67(3,11.75) 68(3,11.25) 69(3,10.75) 70(3,10.25) 71(3,9.75) 72(3,9.25) 73(3,8.75) 74(3,8.25) 75(3,7.75) 76(3,7.25) 77(3,6.75) 78(3,6.25) 79(3,5.75) 80(3,5.25) 81(3,4.75) 82(3,4.25) 83(3,3.75) 84(3,3.25) 85(3,2.75) 86(3,2.25) 87(3,1.75) 88(3,1.25) 89(3,0.75) 90(3,0.25) 91(3,-0.25) 92(3,-0.75) 93(3,-1.25) 94(3,-1.75) 95(3,-2.25) 96(3,-2.75) 97(3,-3.25) 98(3,-3.75) 99(3,-4.25) 100(3,-4.75) 101(3,-5.25) 102(3,-5.75) 103(3,-6.25) 104(3,-6.75) 105(3,-7.25) 106(3,-7.75) 107(3,-8.25) 108(3,-8.75) 109(3,-9.25) 110(3,-9.75) 111(3,-10.25) 112(3,-10.75) 113(3,-11.25) 114(3,-11.75) 115(3,-12.25) 116(3,-12.75) 117(3,-13.25) 118(3,-13.75) 119(3,-14.25) 120(3,-14.75)
  round 1.4 hole 1: MH1(-1.3,21.25) MH1(1.3,21.25) MH2(-1.3,-21.25) MH2(1.3,-21.25)
  round 1.6 hole 1.2: P1(-3.725,17.25) P2(-3.725,-17.25) P3(3.725,17.25) P4(3.725,-17.25)
  body extent -4.6,-22 4.6,22, height 13.15
IEC_HotSurface_Large [mil]
  silkscreen extent -435,-375 435,378
Keystone5001 [mil] "For Keystone 500x miniature loop terminals"
  round 80 hole 40: 1(0,0)
  silkscreen extent -52,-52 52,52, body extent -49,-49 49,49, height 182
Kyocera_CX3225SA [mm] "SMD, 4-Leads, Body 3.2x2.5mm"
  rrect10% 1.05x1.45 smd: 1(-0.925,1.075) 2(-0.925,-1.075) 3(0.925,-1.075) 4(0.925,1.075)
  silkscreen extent -1.86,1.09 -1.74,1.21, body extent -1.3,-1.65 1.3,1.65, height 0.9
Molex_0039300060 [mm] "Header(shrouded), 4.2mm, 3x2, R/A, TH"
  rrect50% 2.7x2.7 hole 1.8: 1(-7.3,4.2)
  round 2.7 hole 1.8: 2(-7.3,0) 3(-7.3,-4.2) 4(-12.8,4.2) 5(-12.8,0) 6(-12.8,-4.2)
  round 2.7 hole 3 unplated mask+0.102: ALIGN1(0,4.2) ALIGN2(0,-4.2)
  body extent -13.33,-6.9 6.6,7.3, height 11.4
NLCV32 [mm] "TDK"
  rect 1.2x2 smd: 1(-1.6,0) 2(1.6,0)
  silkscreen extent -0.9,-1.4 0.9,1.4, body extent -1.7,-1.35 1.7,1.35, height 2.4
PW0016A_N [mm] "TSOP, 16-Leads, Body 5x4.4mm, Pitch 0.65mm, IPC Medium Density"
  oval 1.4x0.45 smd: 1(-2.95,2.275) 2(-2.95,1.625) 3(-2.95,0.975) 4(-2.95,0.325) 5(-2.95,-0.325) 6(-2.95,-0.975) 7(-2.95,-1.625) 8(-2.95,-2.275) 9(2.95,-2.275) 10(2.95,-1.625) 11(2.95,-0.975) 12(2.95,-0.325) 13(2.95,0.325) 14(2.95,0.975) 15(2.95,1.625) 16(2.95,2.275)
  silkscreen extent -3.5,-2.55 1.85,2.75, body extent -3.21,-2.5 3.21,2.5, height 1
RNF0026C [mm] "QFN, 26-Leads, Body 4x4.5mm, Pitch 0.5mm"
  rrect25% 0.6x0.4 smd paste-0.3: 1(-1.9,1.825) 8(-1.9,-1.825) 14(1.9,-1.825) 21(1.9,1.825)
  rrect40% 0.6x0.25 smd paste+0: 2(-1.9,1.25) 3(-1.9,0.75) 4(-1.9,0.25) 5(-1.9,-0.25) 6(-1.9,-0.75) 7(-1.9,-1.25) 15(1.9,-1.25) 16(1.9,-0.75) 17(1.9,-0.25) 18(1.9,0.25) 19(1.9,0.75) 20(1.9,1.25)
  rrect40% 0.25x1.82 smd paste-1: 9(-1,-1.54) 10(-0.5,-1.54) 11(0,-1.54) 12(0.5,-1.54) 13(1,-1.54) 22(1,1.54) 23(0.5,1.54) 24(0,1.54) 25(-0.5,1.54) 26(-1,1.54)
  rrect15% 2.24x0.66 smd paste-1: 27(0,0)
  rrect33% 0.6x0.3 on Bottom Paste: ""(-1.9,-1.775) ""(-1.9,1.775) ""(1.9,-1.775) ""(1.9,1.775)
  rrect33% 0.3x0.825 on Bottom Paste: ""(-1.575,-2.037) ""(-1.575,2.037) ""(1.575,-2.037) ""(1.575,2.037)
  rrect40% 0.25x0.81 on Bottom Paste: ""(-1,-2.045) ""(-1,-1.035) ""(-1,1.035) ""(-1,2.045) ""(-0.5,-2.045) ""(-0.5,-1.035) ""(-0.5,1.035) ""(-0.5,2.045) ""(0,-2.045) ""(0,-1.035) ""(0,1.035) ""(0,2.045) ""(0.5,-2.045) ""(0.5,-1.035) ""(0.5,1.035) ""(0.5,2.045) ""(1,-2.045) ""(1,-1.035) ""(1,1.035) ""(1,2.045)
  rrect15% 0.98x0.66 on Bottom Paste: ""(-0.59,0) ""(0.59,0)
  L1 TOP region: -1.775,-2.4 -1.775,-1.675 -1.771,-1.656 -1.76,-1.64 -1.744,-1.629 -1.725,-1.625 -1.725,-1.625 -1.475,-1.625 -1.456,-1.629 -1.44,-1.64 -1.429,-1.656 -1.425,-1.675 -1.425,-1.675 -1.425,-2.4 -1.429,-2.419 -1.44,-2.435 -1.456,-2.446 -1.475,-2.45 -1.475,-2.45 -1.725,-2.45 -1.744,-2.446 -1.76,-2.435 -1.771,-2.419 -1.775,-2.4
  L1 TOP region: 1.425,-2.4 1.425,-1.675 1.429,-1.656 1.44,-1.64 1.456,-1.629 1.475,-1.625 1.475,-1.625 1.725,-1.625 1.744,-1.629 1.76,-1.64 1.771,-1.656 1.775,-1.675 1.775,-1.675 1.775,-2.4 1.771,-2.419 1.76,-2.435 1.744,-2.446 1.725,-2.45 1.725,-2.45 1.475,-2.45 1.456,-2.446 1.44,-2.435 1.429,-2.419 1.425,-2.4
  L1 TOP region: 1.425,1.675 1.425,2.4 1.429,2.419 1.44,2.435 1.456,2.446 1.475,2.45 1.475,2.45 1.725,2.45 1.744,2.446 1.76,2.435 1.771,2.419 1.775,2.4 1.775,2.4 1.775,1.675 1.771,1.656 1.76,1.64 1.744,1.629 1.725,1.625 1.725,1.625 1.475,1.625 1.456,1.629 1.44,1.64 1.429,1.656 1.425,1.675
  L1 TOP region: -1.775,1.675 -1.775,2.4 -1.771,2.419 -1.76,2.435 -1.744,2.446 -1.725,2.45 -1.725,2.45 -1.475,2.45 -1.456,2.446 -1.44,2.435 -1.429,2.419 -1.425,2.4 -1.425,2.4 -1.425,1.675 -1.429,1.656 -1.44,1.64 -1.456,1.629 -1.475,1.625 -1.475,1.625 -1.725,1.625 -1.744,1.629 -1.76,1.64 -1.771,1.656 -1.775,1.675
  silkscreen extent -2.45,-2.7 2.45,2.7, body extent -2,-2.25 2,2.25, height 0.9
Samtec_TSM-104-01-x-DV [mm] "Header, 2.54mm, 4x2, SMT"
  rect 3.68x1.27 smd: 1(-2.475,3.81) 2(2.475,3.81) 3(-2.475,1.27) 4(2.475,1.27) 5(-2.475,-1.27) 6(2.475,-1.27) 7(-2.475,-3.81) 8(2.475,-3.81)
  silkscreen extent -1.65,-5.08 1.65,5.22, body extent -3.85,-5.08 3.85,5.08, height 9.65
Samtec_TSM-106-01-x-DV [mm] "Header, 2.54mm, 6x2, SMT"
  rect 3.68x1.27 smd: 1(-2.475,6.35) 2(2.475,6.35) 3(-2.475,3.81) 4(2.475,3.81) 5(-2.475,1.27) 6(2.475,1.27) 7(-2.475,-1.27) 8(2.475,-1.27) 9(-2.475,-3.81) 10(2.475,-3.81) 11(-2.475,-6.35) 12(2.475,-6.35)
  silkscreen extent -1.65,-7.62 1.65,7.76, body extent -3.85,-7.62 3.85,7.62, height 9.65
SOT-23 [mm] "SOT23, 3-Leads, Body 2.9x1.3mm, Pitch 0.95mm, Lead Span 2.5mm, IPC Medium Density"
  rrect50% 1x0.6 smd: 1(-1.2,0.95) 2(-1.2,-0.95) 3(1.2,0)
  silkscreen extent -1.62,-1.5 0.7,1.5, body extent -1.16,-1.45 1.21,1.45, height 1
TI_Stacked_Overlay_Small [mil]
  silkscreen extent -418,-98 418,98
TLMx1000_Red [mm] "SMD, 2-Leads, Body 1.6x0.8mm"
  rrect17% 0.6x0.8 smd: 1(-0.725,0) 2(0.725,0)
  silkscreen extent -0.97,-0.8 1.6,0.8, body extent -0.85,-0.45 0.85,0.45, height 0.65
TLMx1000_Yellow [mm] "SMD, 2-Leads, Body 1.6x0.8mm"
  rrect17% 0.6x0.8 smd: 1(-0.725,0) 2(0.725,0)
  silkscreen extent -0.97,-0.8 1.6,0.8, body extent -0.85,-0.45 0.85,0.45, height 0.65
TP_SM_1MM [mm] "1mm Test Point, SMT"
  round 1 smd paste-0.5: 1(0,0)
WEEE_Minimum [mil] "WEEElie bin"
  silkscreen extent -95,-172 99,104
WSON-8L_6x5MM_EP [mm] "SMD, 8-Leads, Body 6x5mm, Pitch 1.27mm"
  rrect25% 0.8x0.4 smd: 1(-2.8,1.905) 2(-2.8,0.635) 3(-2.8,-0.635) 4(-2.8,-1.905) 5(2.8,-1.905) 6(2.8,-0.635) 7(2.8,0.635) 8(2.8,1.905)
  rrect3% 3.4x4 smd paste-3: 9(0,0)
  rrect7% 1.468x1.698 on Bottom Paste: ""(-0.834,-0.949) ""(-0.834,0.949) ""(0.834,-0.949) ""(0.834,0.949)
  silkscreen extent -3.2,-2.7 3.2,2.7, body extent -3.05,-2.55 3.05,2.55, height 0.8

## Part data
C1_1 C1_2 C1_3 C1_4 C3_1 C3_2 C3_3 C3_4 C7_1 C7_2 C7_3 C7_4: library part CMP-0007136-5, "CAP, CERM, 1 uF, 16 V, +/- 10%, X7R, AEC-Q200 Grade 1, 0603", Cap_Case=0603, Manufacturer=MuRata, Supplier Part Number 1=490-5241-6-ND, TempCo=X7R, Tolerance_%=10%, Value1=Unknown, Value2=16V, ValueDisplayed=1uF
C2_1 C2_2 C2_3 C2_4 C4_1 C4_2 C4_3 C4_4 C128_1 C128_2 C128_3 C128_4 C129_1 C129_2 C129_3 C129_4 C131_1 C131_2 C131_3 C131_4 C132_1 C132_2 C132_3 C132_4 C134_1 C134_2 C134_3 C134_4 C135_1 C135_2 C135_3 C135_4 C136_1 C136_2 C136_3 C136_4 C137_1 C137_2 C137_3 C137_4 C138_1 C138_2 C138_3 C138_4 C140_1 C140_2 C140_3 C140_4 C142_1 C142_2 C142_3 C142_4 C143_1 C143_2 C143_3 C143_4 C144_1 C144_2 C144_3 C144_4 C145_1 C145_2 C145_3 C145_4 C148_1 C148_2 C148_3 C148_4 C170 C177 C179 C182 C186 C188: library part CMP-0078265-1, "CAP, CERM, 0.22 µF, 16 V,+/- 10%, X7R, AEC-Q200 Grade 1, 0402", Cap_Case=0402, Manufacturer=MuRata, Supplier Part Number 1=490-10671-1-ND, TempCo=X7R, Tolerance_%=10%, Value2=16V, ValueDisplayed=0.22µF
C5_1 C5_2 C5_3 C5_4 C6_1 C6_2 C6_3 C6_4 C10 C12 C14 C16 C19 C23 C25 C27 C29 C31 C32 C33 C35 C70 C72 C74 C76 C80 C82 C84 C86 C88 C89 C90 C92 C130_1 C130_2 C130_3 C130_4 C133_1 C133_2 C133_3 C133_4 C139_1 C139_2 C139_3 C139_4 C141_1 C141_2 C141_3 C141_4 C151 C153 C155 C157 C159 C161 C169 C172 C175 C176 C181 C184 C185 C201 C207: library part CMP-0008017-2, "CAP, CERM, 10 uF, 10 V, +/- 10%, X7R, 0805", Cap_Case=0805, Manufacturer=MuRata, Supplier Part Number 1=490-10674-1-ND, TempCo=X7R, Tolerance_%=10%, Value1=Unknown, Value2=10V, ValueDisplayed=10uF
C8_1 C8_2 C8_3 C8_4 C94 C149 C196 C197 C198 C200 C205 C206: library part CMP-0006325-2, "CAP, CERM, 0.1 uF, 50 V, +/- 10%, X7R, AEC-Q200 Grade 1, 0402", Cap_Case=0402, Manufacturer=TDK, Supplier Part Number 1=445-6899-1-ND, TempCo=X7R, Tolerance_%=10%, Value1="0.039064 ohm", Value2=50V, ValueDisplayed=0.1uF
C9 C146_1 C146_2 C146_3 C146_4 C147_1 C147_2 C147_3 C147_4 C162 C163 C164 C165: library part CMP-0006351-2, "CAP, CERM, 0.1 uF, 16 V, +/- 10%, X7R, 0402", Cap_Case=0402, Manufacturer=MuRata, Supplier Part Number 1=490-4759-2-ND, TempCo=X7R, Tolerance_%=10%, Value1=Unknown, Value2=16V, ValueDisplayed=0.1uF
C11 C15 C18 C21 C22 C24 C30 C71 C75 C79 C81 C87 C150 C154 C158 C166 C204: library part CMP-0008811-2, "CAP, CERM, 22 uF, 10 V, +/- 10%, X7R, AEC-Q200 Grade 1, 1206", Cap_Case=1206, Manufacturer=MuRata, TempCo=X7R, Tolerance_%=10%, Value1=Unknown, Value2=10V, ValueDisplayed=22uF
C13 C17 C20 C26 C28 C34 C36 C73 C77 C78 C83 C85 C91 C93 C152 C156 C160 C202 C203: library part CMP-0079154-1, "CAP, CERM, 1 µF, 16 V,+/- 10%, X7R, AEC-Q200 Grade 1, 0603", Cap_Case=0603, Manufacturer=MuRata, Supplier Part Number 1=490-12657-1-ND, TempCo=X7R, Tolerance_%=10%, Value2=16V, ValueDisplayed=1µF
C37 C38 C49 C50 C95 C96 C107 C108: library part CMP-0080703-2, "CAP, CERM, 390 pF, 50 V,+/- 10%, X7R, AEC-Q200 Grade 1, 0402", Cap_Case=0402, Manufacturer=MuRata, Supplier Part Number 1=81-GCM155R71H391KA7D, TempCo=X7R, Tolerance_%=10%, Value2=50V, ValueDisplayed=390pF
C39 C44 C51 C56 C97 C102 C109 C114: library part CMP-0860888-1, "CAP, CERM, 6800 pF, 100 V,+/- 10%, X7R, AEC-Q200 Grade 1, 0603", Cap_Case=0603, Manufacturer=MuRata, TempCo=X7R, Tolerance_%=10%, Value2=100V, ValueDisplayed=6800pF
C40 C41 C45 C46 C52 C53 C57 C58 C98 C99 C103 C104 C110 C111 C115 C116: library part CMP-0008280-2, "CAP, CERM, 100 uF, 6.3 V, +/- 20%, X5R, 0805", Cap_Case=0805, Manufacturer=MuRata, TempCo=X5R, Tolerance_%=20%, Value1=Unknown, Value2=6.3V, ValueDisplayed=100uF
C42 C47 C54 C59 C63 C100 C105 C112 C117 C121: library part CMP-0080702-1, "CAP, CERM, 0.1 µF, 16 V,+/- 5%, X7R, AEC-Q200 Grade 1, 0402", Cap_Case=0402, Manufacturer=MuRata, Supplier Part Number 1=490-16433-1-ND, TempCo=X7R, Tolerance_%=5%, Value2=16V, ValueDisplayed=0.1µF
C43 C48 C55 C60 C101 C106 C113 C118: library part CMP-0081849-1, "CAP, CERM, 10 µF,  V,+/- 10%, X7R, 0805", Cap_Case=0805, Manufacturer=MuRata, Supplier Part Number 1=490-10516-2-ND, TempCo=X7R, Tolerance_%=10%, ValueDisplayed=10µF
C61 C62 C64 C65 C66 C67 C68 C69 C119 C120 C122 C123 C124 C125 C126 C127: library part CMP-0007890-1, "CAP, CERM, 22 uF, 10 V, +/- 20%, X7S, 0805", Cap_Case=0805, Manufacturer=TDK, Supplier Part Number 1=445-14560-1-ND, TempCo=X7S, Tolerance_%=20%, Value1="0.00205 ohm", Value2=10V, ValueDisplayed=22uF
C167 C168 C173 C174: library part CMP-0006367-2, "CAP, CERM, 4.7 pF, 50 V, +/- 2%, C0G/NP0, 0402", Cap_Case=0402, Manufacturer=MuRata, Supplier Part Number 1=490-8102-1-ND, TempCo=C0G/NP0, Tolerance_%=2%, Value1=Unknown, Value2=50V, ValueDisplayed=4.7pF
C171 C178 C180 C183 C187 C189: library part CMP-0007134-5, "CAP, CERM, 2.2 uF, 6.3 V, +/- 10%, X7R, AEC-Q200 Grade 1, 0603", Cap_Case=0603, Manufacturer=MuRata, Supplier Part Number 1=490-5316-1-ND, TempCo=X7R, Tolerance_%=10%, Value1=Unknown, Value2=6.3V, ValueDisplayed=2.2uF
C190 C191 C192 C193 C194: library part CMP-0078216-1, "CAP, TA, 47 µF, 10 V, +/- 10%, SMD", Cap_Case=3528-21, Manufacturer=Kemet, Supplier Part Number 1=399-9728-1-ND, Tolerance_%=10%, Value2=10V, ValueDisplayed=47µF
C195 C199: library part CMP-0078218-1, "CAP, CERM, 0.01 µF, 16 V,+/- 10%, X7R, 0402", Cap_Case=0402, Manufacturer=Kemet, Supplier Part Number 1=399-1038-1-ND, TempCo=X7R, Tolerance_%=10%, Value2=16V, ValueDisplayed=0.01µF
DS1 DS2: library part CMP-0078197-1, "LED, Red, SMD", Color=Red, Manufacturer=Vishay-Semiconductor, Power_TotalModule=40mW, Supplier Part Number 1=TLMS1000-GS08CT-ND, Value1=.04W, Value2=1.8V
DS3 DS4 DS5 DS6 DS7: library part CMP-0078196-1, "LED, Yellow, SMD", Color=yellow, Manufacturer=Vishay-Semiconductor, Power_TotalModule=40mW, Supplier Part Number 1=TLMY1000-GS08CT-ND, Value1=.04W, Value2=1.8V
FID1 FID2 FID3 FID4 FID5 FID6: library part CMP-0077181-1, "Fiducial mark.  There is nothing to buy or mount.", Manufacturer=N/A
J1_1 J1_2 J1_3 J1_4: library part CMP-0075594-2, "Header, 2.54mm, 6x2, Gold, SMT", Color=Black, Current_A=4.9A, Manufacturer=Samtec, Supplier Part Number 1=TSM-106-01-L-DV-ND, Voltage_V=475V
J2: library part CMP-0075593-2, "Header, 2.54mm, 4x2, Gold, SMT", Color=Black, Current_A=4.9A, Manufacturer=Samtec, Supplier Part Number 1=TSM-104-01-L-DV-ND, Voltage_V=475V
J3: library part CMP-0055458-1, "Connector, RF 50 Ohms, SMT", Manufacturer=Rosenberger
J4 J5: library part CMP-0081853-1, "Header(shrouded), 0.5mm, 60x2, Gold, SMT", Color=Black, Manufacturer="Hirose Electric Co. Ltd.", Supplier Part Number 1=H125039-ND
J6: library part CMP-0082107-1, "Header(shrouded), 4.2mm, 3x2, Tin, R/A, TH", Color=Natural, Current_A=13A, Manufacturer=Molex, Supplier Part Number 1=WM21353-ND, Voltage_V=600V
L1 L2 L3 L4 L5 L6 L7 L8 L17 L18 L19 L20 L21 L22 L23 L24: library part CMP-0083745-1, "Inductor, Wirewound, Ferrite, 100 nH, 2.85 A, 0.024 ohm, AEC-Q200 Grade 1, SMD", Manufacturer=TDK, Value1="0.024 ohm", Value2=2.85A, ValueDisplayed=100nH
L9 L10 L11 L12 L25 L26 L27 L28: library part CMP-0003364-1, "Ferrite Bead, 30 ohm @ 100 MHz, 4 A, 0805", Manufacturer=MuRata, Supplier Part Number 1=490-11049-1-ND, Value1="0.014 ohm", Value2=4A, ValueDisplayed="30 ohm"
L13 L14 L15 L16 L29 L30 L31 L32: library part CMP-0058944-1, "Inductor, Shielded, 470 nH, 4.7 A, 0.021 ohm, SMD", Manufacturer="MuRata Toko", Value1="0.021 ohm", Value2=4.7A, ValueDisplayed=470nH
L33 L34 L35: library part CMP-0003352-2, "Ferrite Bead, 120 ohm @ 100 MHz, 3 A, 0603", Manufacturer=MuRata, Supplier Part Number 1=490-3996-1-ND, Value1="0.025 ohm", Value2=3A, ValueDisplayed="120 ohm"
Logo1: library part CMP-0074844-1, "CE Mark"
Logo2: library part CMP-0074838-1, "Texas Instrument Corporate Signature"
Logo3: library part CMP-0074847-1, "FCC_disclaimer"
Logo4: library part CMP-0074769-1
Logo5: library part CMP-0074840-1, "ESD Susceptible Symbol"
LOGO6: library part CMP-0074837-1, "IEC 61010-1 Hot Surface Warning"
Q1 Q2 Q3 Q4 Q5: library part CMP-0000947-2, "MOSFET, N-CH, 100 V, 0.17 A, SOT-23", Alternate Manufacturer=None, Manufacturer="Fairchild Semiconductor", Supplier Part Number 1=BSS123NCT-ND, Value1=1, Value2="1.8 nC"
R1_1 R1_2 R1_3 R1_4 R2_1 R2_2 R2_3 R2_4 R4_1 R4_2 R4_3 R4_4 R5_1 R5_2 R5_3 R5_4 R8_1 R8_2 R8_3 R8_4 R10_1 R10_2 R10_3 R10_4 R11_1 R11_2 R11_3 R11_4 R12_1 R12_2 R12_3 R12_4 R13_1 R13_2 R13_3 R13_4 R14_1 R14_2 R14_3 R14_4 R15_1 R15_2 R15_3 R15_4: library part CMP-0026299-2, "RES, 33.2, 1%, 0.063 W, AEC-Q200 Grade 0, 0402", Manufacturer=Vishay-Dale, Power_W=63mW, Supplier Part Number 1=541-33.2LCT-ND, TempCo="100 ppm/C", Tolerance_%=1%, Value2=0.063W, Value_Code=33R2, ValueDisplayed=33.2
R3_1 R3_2 R3_3 R3_4: library part CMP-0026395-2, "RES, 47.5 k, 1%, 0.063 W, AEC-Q200 Grade 0, 0402", Manufacturer=Vishay-Dale, Power_W=63mW, Supplier Part Number 1=541-47.5KLCT-ND, TempCo="100 ppm/C", Tolerance_%=1%, Value2=0.063W, Value_Code=47k5, ValueDisplayed=47.5k
R6_1 R6_2 R6_3 R6_4 R7_1 R7_2 R7_3 R7_4 R30_1 R30_2 R30_3 R30_4 R31_1 R31_2 R31_3 R31_4 R32_1 R32_2 R32_3 R32_4 R33_1 R33_2 R33_3 R33_4 R127: library part CMP-0027008-4, "RES, 0, 5%, 0.05 W, 0201", Manufacturer=Vishay-Dale, Power_W=50mW, Supplier Part Number 1=72M6743, TempCo=ppm/C, Tolerance_%=5%, Value2=0.05W, Value_Code=0000, ValueDisplayed=0
R9_1 R9_2 R9_3 R9_4 R107 R109 R115 R116 R117 R121 R122 R123 R126 R128 R129 R130 R131 R142 R143 R145 R146 R165 R169 R170 R171 R172 R186 R187 R204 R205 R208 R209 R210 R211 R213 R214: library part CMP-0026992-3, "RES, 0, 5%, 0.1 W, AEC-Q200 Grade 0, 0402", Manufacturer=Panasonic, Power_W=100mW, Supplier Part Number 1=P0.0JCT-ND, TempCo="600 ppm/C", Tolerance_%=5%, Value2=0.1W, Value_Code=0000, ValueDisplayed=0
R16_1 R16_2 R16_3 R16_4 R17_1 R17_2 R17_3 R17_4 R18_1 R18_2 R18_3 R18_4 R27_1 R27_2 R27_3 R27_4 R28_1 R28_2 R28_3 R28_4 R37 R49 R50 R51 R54 R55 R56 R57 R58 R61 R74 R78 R80 R81 R86 R87 R88 R89 R90 R91 R92 R93 R94 R95 R118 R119 R120 R124 R137 R138 R139 R141 R144 R147 R148 R149 R150 R151 R152 R153 R155 R157 R159 R161 R162 R163 R174_1 R174_2 R174_3 R174_4 R176_1 R176_2 R176_3 R176_4 R177_1 R177_2 R177_3 R177_4 R184_1 R184_2 R184_3 R184_4 R185_1 R185_2 R185_3 R185_4 R206 R207: library part CMP-0025958-3, "RES, 10.0 k, 1%, 0.063 W, AEC-Q200 Grade 0, 0402", Manufacturer=Vishay-Dale, Power_W=63mW, Supplier Part Number 1=541-10.0KLCT-ND, TempCo="100 ppm/C", Tolerance_%=1%, Value2=0.063W, Value_Code=10k0, ValueDisplayed=10.0k
R19 R20 R35 R188_1 R188_2 R188_3 R188_4: library part CMP-0081857-1, "RES, 0, 0%,  W, AEC-Q200 Grade 0, 0805", Manufacturer=Rohm, Supplier Part Number 1=755-PMR10EZPJ000, Tolerance_%=0%, Value2=W, Value_Code=0
R21_1 R21_2 R21_3 R21_4 R22_1 R22_2 R22_3 R22_4 R23_1 R23_2 R23_3 R23_4 R24_1 R24_2 R24_3 R24_4 R25_1 R25_2 R25_3 R25_4 R26_1 R26_2 R26_3 R26_4 R43 R45 R48 R52 R67 R69 R72 R76: library part CMP-0026822-3, "RES, 0, 5%, 0.063 W, AEC-Q200 Grade 0, 0402", Manufacturer=Vishay-Dale, Power_W=63mW, Supplier Part Number 1=541-0.0JCT-ND, TempCo="200 ppm/C", Tolerance_%=5%, Value2=0.063W, Value_Code=0000, ValueDisplayed=0
R29_1 R29_2 R29_3 R29_4: library part CMP-0020443-3, "RES, 0, 5%, 0.333 W, AEC-Q200 Grade 0, 0805", Manufacturer=Vishay-Dale, Power_W=333mW, Supplier Part Number 1=541-0.0TBCT-ND, TempCo="200 ppm/C", Tolerance_%=5%, Value2=0.333W, Value_Code=0000, ValueDisplayed=0
R34 R59: library part CMP-0022170-4, "RES, 1.00, 1%, 0.1 W, AEC-Q200 Grade 0, 0603", Manufacturer=Vishay-Dale, Power_W=100mW, Supplier Part Number 1=52K8059, TempCo="100 ppm/C", Tolerance_%=1%, Value2=0.1W, Value_Code=1R00, ValueDisplayed=1.00
R36 R60: library part CMP-0022137-4, "RES, 1.96 k, 1%, 0.1 W, AEC-Q200 Grade 0, 0603", Manufacturer=Vishay-Dale, Power_W=100mW, Supplier Part Number 1=541-1.96KHCT-ND, TempCo="100 ppm/C", Tolerance_%=1%, Value2=0.1W, Value_Code=1k96, ValueDisplayed=1.96k
R38 R53 R62 R77 R189 R190 R191 R212: library part CMP-0026794-1, "RES, 100, 0.1%, 0.1 W, AEC-Q200 Grade 0, 0402", Manufacturer=Vishay/Beyschlag, Power_W=100mW, Supplier Part Number 1=MCS0402-100-MBCT-ND, TempCo="25 ppm/C", Tolerance_%=0.1%, Value2=0.1W, Value_Code=100R, ValueDisplayed=100
R39 R40 R41 R42 R63 R64 R65 R66: library part CMP-0026928-3, "RES, 3.9, 5%, 0.063 W, AEC-Q200 Grade 0, 0402", Manufacturer=Vishay-Dale, Power_W=63mW, Supplier Part Number 1=541-3.9JCT-ND, TempCo="200 ppm/C", Tolerance_%=5%, Value2=0.063W, Value_Code=3R90, ValueDisplayed=3.9
R44 R68 R73 R75 R96 R97: library part CMP-0025884-3, "RES, 0, 5%, 0.125 W, 0603", Manufacturer=Vishay/Beyschlag, Power_W=125mW, Supplier Part Number 1=MCT0603-0.0-ZZCT-ND, TempCo=ppm/C, Tolerance_%=5%, Value2=0.125W, Value_Code=0000, ValueDisplayed=0
R46 R47 R70 R71 R180_1 R180_2 R180_3 R180_4 R181_1 R181_2 R181_3 R181_4: library part CMP-0026938-5, "RES, 4.7 k, 5%, 0.063 W, AEC-Q200 Grade 0, 0402", Manufacturer=Vishay-Dale, Power_W=63mW, Supplier Part Number 1=541-4.7KJCT-ND, TempCo="200 ppm/C", Tolerance_%=5%, Value2=0.063W, Value_Code=4k70, ValueDisplayed=4.7k
R79 R82 R83 R84 R85: library part CMP-0026404-2, "RES, 49.9, 1%, 0.063 W, AEC-Q200 Grade 0, 0402", Manufacturer=Vishay-Dale, Power_W=63mW, Supplier Part Number 1=541-49.9LCT-ND, TempCo="100 ppm/C", Tolerance_%=1%, Value2=0.063W, Value_Code=49R9, ValueDisplayed=49.9
R98 R99 R100 R101 R102 R112 R114 R125 R154 R156 R158 R160: library part CMP-0081856-1, "RES, 0, 0%, 0.2 W, AEC-Q200 Grade 0, 0402", Manufacturer=Vishay-Dale, Power_W=200mW, Supplier Part Number 1=541-0.0YBTR-ND, Tolerance_%=0%, Value2=0.2W, Value_Code=0
R103 R104 R106 R108 R132 R133 R134 R135: library part CMP-0026932-3, "RES, 43, 5%, 0.063 W, AEC-Q200 Grade 0, 0402", Manufacturer=Vishay-Dale, Power_W=63mW, Supplier Part Number 1=541-43JCT-ND, TempCo="200 ppm/C", Tolerance_%=5%, Value2=0.063W, Value_Code=43R0, ValueDisplayed=43
R105: library part CMP-0082348-1, "RES, 11.5 k, 1%, 0.1 W, AEC-Q200 Grade 0, 0402", Manufacturer=Panasonic, Power_W=100mW, TempCo="100 ppm/C", Tolerance_%=1%, Value2=0.1W, Value_Code=11k5, ValueDisplayed=11.5k
R110: library part CMP-0082349-1, "RES, 3.09 k, 1%, 0.1 W, AEC-Q200 Grade 0, 0402", Manufacturer=Panasonic, Power_W=100mW, TempCo="100 ppm/C", Tolerance_%=1%, Value2=0.1W, Value_Code=3k09, ValueDisplayed=3.09k
R111: library part CMP-0026703-1, "RES, 49.9, 1%, 0.1 W, AEC-Q200 Grade 0, 0402", Manufacturer=Panasonic, Power_W=100mW, Supplier Part Number 1=P49.9LCT-ND, TempCo="100 ppm/C", Tolerance_%=1%, Value2=0.1W, Value_Code=49R9, ValueDisplayed=49.9
R113: library part CMP-0026071-3, "RES, 1.00 k, 1%, 0.063 W, AEC-Q200 Grade 0, 0402", Manufacturer=Vishay-Dale, Power_W=63mW, Supplier Part Number 1=541-1.00KLCT-ND, TempCo="100 ppm/C", Tolerance_%=1%, Value2=0.063W, Value_Code=1k00, ValueDisplayed=1.00k
R136: library part CMP-0083872-1, "RES, 100, 2%, 0.03 W, 02016", Manufacturer=Vishay-Semiconductor, Power_W=30mW, TempCo="100 ppm/C", Tolerance_%=5%, Value1=2%, Value2=0.03W, Value_Code=100R, ValueDisplayed=100
R140: library part CMP-0083872-1, "RES, 100, 2%, 0.03 W, 02016", Manufacturer=Vishay-Semiconductor, Power_W=30mW, TempCo="100 ppm/C", Tolerance_%=2%, Value1=5%, Value2=0.03W, Value_Code=100R, ValueDisplayed=100
R164 R173: library part CMP-0025963-3, "RES, 10.0, 1%, 0.063 W, AEC-Q200 Grade 0, 0402", Manufacturer=Vishay-Dale, Power_W=63mW, Supplier Part Number 1=541-10.0LCT-ND, TempCo="100 ppm/C", Tolerance_%=1%, Value2=0.063W, Value_Code=10R0, ValueDisplayed=10.0
R166 R167 R168: library part CMP-0026463-2, "RES, 5.11 k, 1%, 0.063 W, AEC-Q200 Grade 0, 0402", Manufacturer=Vishay-Dale, Power_W=63mW, Supplier Part Number 1=541-5.11KLCT-ND, TempCo="100 ppm/C", Tolerance_%=1%, Value2=0.063W, Value_Code=5k11, ValueDisplayed=5.11k
R175_1 R175_2 R175_3 R175_4 R178_1 R178_2 R178_3 R178_4 R179_1 R179_2 R179_3 R179_4 R182_1 R182_2 R182_3 R182_4 R183_1 R183_2 R183_3 R183_4: library part CMP-0025950-3, "RES, 100 k, 1%, 0.063 W, AEC-Q200 Grade 0, 0402", Manufacturer=Vishay-Dale, Power_W=63mW, Supplier Part Number 1=541-100KLCT-ND, TempCo="100 ppm/C", Tolerance_%=1%, Value2=0.063W, Value_Code=100k
R192 R194 R195 R196 R197 R198 R199 R200 R201 R202 R203: library part CMP-0078212-1, "RES, 510, 5%, 0.1 W, AEC-Q200 Grade 0, 0402", Manufacturer=Panasonic, Power_W=100mW, Supplier Part Number 1=P510JCT-ND, TempCo="200 ppm/C", Tolerance_%=5%, Value2=0.1W, Value_Code=510R, ValueDisplayed=510
R193: library part CMP-0078194-1, "RES, 360, 5%, 0.1 W, AEC-Q200 Grade 0, 0402", Manufacturer=Panasonic, Power_W=100mW, Supplier Part Number 1=P360JCT-ND, TempCo="200 ppm/C", Tolerance_%=5%, Value2=0.1W, Value_Code=360R, ValueDisplayed=360
TP1_1 TP1_2 TP1_3 TP1_4 TP2_1 TP2_2 TP2_3 TP2_4 TP3_1 TP3_2 TP3_3 TP3_4 TP4 TP5 TP6 TP7 TP8 TP9 TP10 TP11 TP12 TP13 TP14 TP15 TP21 TP22 TP23 TP24 TP26 TP27 TP28 TP31 TP32 TP33: library part CMP-0003825-1, "1mm Test Point, SMT", Manufacturer=Any
TP16 TP17 TP18 TP19 TP20 TP25 TP29 TP30: library part CMP-0055138-1, "Test Point, Miniature, Black, TH", Color=Black, Manufacturer=Keystone, Supplier Part Number 1=36-5001-ND
U1_1 U1_2 U1_3 U1_4: library part CMP-0082537-1, "Single Chip 77 and 79 GHz FMCW Transceiver, ABL0161A (FCBGA-161)", Alternate Manufacturer="Texas Instruments", Rating=Automotive
U2_1 U2_2 U2_3 U2_4: library part CMP-0079267-1, "2.3V-3.6V, 16M-BIT [x 1/x 2/x 4] CMOS FLASH Memory, WSON-8", Manufacturer="Macronix International Co., LTD", Supplier Part Number 1=1092-1211-ND
U3 U4: library part CMP-0083823-1, "4-A + 2.5-A + Two 1.5-A Buck Converters With Integrated Switches, RNF0026C (VQFN-HR-26)", Alternate Manufacturer="Texas Instruments", Alternate PartNumber=LP87524PRNFRQ1, Rating=Automotive
U5: library part CMP-0036354-2, "Single Output Automotive LDO, 1 A, Fixed 3.3 V Output, 2.2 to 5.5 V Input, with Reverse Current Protection, 8-pin SON (DRB), -40 to 125 degC, Green (RoHS & no Sb/Br)", Manufacturer="Texas Instruments", Rating=Automotive
U6 U11 U12 U13: library part CMP-0051570-2, "Automotive Catalog Single 2-Input Positive-AND Gate, DBV0005A, LARGE T&R", Alternate Manufacturer="Texas Instruments", F @ Nom Voltage(Max)(Mhz)=150, Generic Part Number=SN74LVC1G08-Q1, ICC @ Nom Voltage(Max)(mA)=0.01, Operating Temperature Range(C)="-40 to 125,-40 to 85", Rating=Automotive, tpd @ Nom Voltage(Max)(ns)=8,5.5,4.5,4, Voltage(Nom)(V)=1.8,2.5,3.3,5
U7 U8: library part CMP-0065663-1, "Low Skew, 1-to-4 Multiplexed Differential/LVCMOS-to-LVCMOS/TTL Fanout Buffer, PW0016A (TSSOP-16)", Alternate Manufacturer="Texas Instruments"
U9 U10: library part CMP-0067397-2, "1.4V-Capable +/-0.5degC Temperature Sensor with Alert Function and I2C/SMBus interface in SOT-563, DRL0006A (SOT-OTHER-6)", Alternate Manufacturer="Texas Instruments", Alternate PartNumber=TMP112AIDRLT
Y1 Y2: library part CMP-0004694-3, "Crystal, 40 MHz, 8pF, SMD", Frequency_Fixed=40MHz, Frequency Stability=+/-200ppm, Manufacturer=Kyocera, Supplier Part Number 1=581-CX3225SA40D0PTWC
ZZ1: library part CMP-0077236-1, "These assemblies are ESD sensitive, ESD precautions shall be observed."
ZZ2: library part CMP-0077237-1
ZZ3: library part CMP-0077238-1, "These assemblies must comply with workmanship standards IPC-A-610 Class 2, unless otherwise specified."
ZZ4: library part CMP-0077238-1

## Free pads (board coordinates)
  round 200 hole 160: ""(0,0) ""(0,5108) ""(6037,0) ""(6037,5108)
  round 158.11 hole 118.11: ""(12,2652) ""(12,3257) ""(6025.21,2652) ""(6025.21,3257)

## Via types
v1: diameter 13.77/15.74 (per signal layer), hole 5.9, L1 TOP to L2 GND, tented both sides, 5522 vias
v2: diameter 22.4, hole 12.2, L1 TOP to L8 BOTTOM, tented both sides, 1522 vias
v3: diameter 18, hole 8, L1 TOP to L8 BOTTOM, tented both sides, 727 vias
v4: diameter 18, hole 7.87, L1 TOP to L8 BOTTOM, tented top, 50 vias
v5: diameter 24, hole 12, L1 TOP to L8 BOTTOM, tented both sides, 13 vias
v6: diameter 19.68, hole 7.87, L1 TOP to L8 BOTTOM, tented top, 10 vias
v7: diameter 13.77/15.74 (per signal layer), hole 5.9, L1 TOP to L2 GND, tented top, 1 vias

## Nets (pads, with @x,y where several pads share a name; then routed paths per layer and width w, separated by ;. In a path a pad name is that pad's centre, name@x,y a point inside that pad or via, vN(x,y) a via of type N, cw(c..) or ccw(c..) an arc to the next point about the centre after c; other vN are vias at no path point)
40M_BUF_IN_PRIMAWRY: R107.2 R109.2 R111.2 R113.2 U7.5 | length 233.5
  L1 TOP w10.5: R111.2@2611.99,4860.7 R109.2@2611.99,4909.65 2636.09,4909.65 R113.2@2660.57,4934.13 ; R107.2@2611.99,4958.61 2636.09,4958.61 R113.2@2660.57,4934.13 ; U7.5@2725.57,4939.13 2665.57,4939.13 R113.2@2660.57,4934.13
40M_BUF_IN_SECONDAWRY: R122.2 R123.2 U7.8 | length 120.2
  L1 TOP w10.5: R122.2@2672.94,4810.62 2699.26,4836.94 ; R123.2@2725.57,4810.62 2699.26,4836.94 ; U7.8@2725.57,4862.36 2709.45,4862.36 2699.26,4852.17 2699.26,4836.94
AWR_1_1V0_RF1_FILT: C22.1 C23.1 C26.1 C136_1.1 C137_1.1 C138_1.1 C139_1.1 L4.2 U1_1.G5 U1_1.H5 U1_1.J5 | length 101.7
  L1 TOP w15: v2(2404.09,3149.57) 2402.3,3147.78 U1_1.J5@2402.3,3124.27 U1_1.G5@2453.48,3124.27 2453.48,3145.69 v2(2451.34,3147.83)
  other v3: 1156.05,1311.3 1175.74,1311.3 1156.05,1330.98 1175.74,1330.98 1156.05,1350.67 1175.74,1350.67 1156.05,1370.35 1175.74,1370.35 2262.53,3407.18 2282.21,3407.18 2262.53,3426.86 2282.21,3426.86 2251.51,3443.1
AWR_1_1V0_RF2_FILT: C24.1 C28.1 C32.1 C140_1.1 C141_1.1 L5.2 R188_1.2 U1_1.C2 U1_1.D2 | length 106
  L1 TOP w12: v2(2526.49,3156.98) 2530.25,3160.74 U1_1.D2@2530.26,3201.04 U1_1.C2@2555.85,3201.04
  L1 TOP w20: v3(2807.55,3203.9) R188_1.2@2807.55,3238.67
  other v2: 2530.26,3181.14
  other v3: 1508.89,678.8 1528.58,678.8 1548.26,678.8 1508.89,698.48 1528.58,698.48 1548.26,698.48 1508.89,718.17 1528.58,718.17 1548.26,718.17 2770.85,1288.01 2790.54,1288.01 2770.85,1307.69 2790.54,1307.69 2770.85,1327.38 2790.54,1327.38 2770.85,1347.06 2790.54,1347.06 2826.71,3191.75 2642,3230.61 2661.69,3230.61 2622.32,3250.3 2642,3250.3 2661.69,3250.3
AWR_1_1V2_FILT: C11.1 C12.1 C13.1 C142_1.1 C143_1.1 C144_1.1 C145_1.1 C146_1.1 C147_1.1 L1.2 U1_1.F13 U1_1.N11 U1_1.P14 U1_1.P15 U1_1.R6 U1_1.R14 | length 742.4
  L1 TOP w4: 2261.5,2857.69 2261.5,2873.5 2274.35,2886.35 U1_1.P14@2274.35,2893.95
  L1 TOP w8: 2253.43,2846.28 2261.5,2854.35 2261.5,2857.69 ; 2274.35,2845.01 U1_1.P15@2274.35,2868.36
  L1 TOP w10: v2@2188,3114 2200,3114 2215,3099 2227,3099 2227.32,3098.68 U1_1.R6@2248.76,3098.68 ; 2209,2884 2221,2884 2230.96,2893.96 U1_1.R14@2248.76,2893.95 ; 2230.75,2823.6 2253.43,2846.28 ; 2264.25,2828.86 2274.35,2838.95 2274.35,2845.01 ; v2(2478.51,2944.72) 2479.07,2944.16 U1_1.F13@2479.07,2919.55
  L1 TOP w15: C142_1.1@2141.49,3125.71 2152.2,3115 v2(2187,3115) v2@2188,3114 ; v2(2151,2828) 2183.58,2860.58 C146_1.1@2183.58,2870 2197.58,2884 2209,2884 ; v2(2164,2798.99) 2177.42,2785.57 C147_1.1@2203,2785.58 ; C147_1.1@2203,2787 2220,2804 2220,2812.85 2230.75,2823.6 ; 2264.25,2828.86 2244,2808.6 C143_1.1@2244,2785.58 2249.58,2780 v2(2274,2780) ; U1_1.N11@2299.94,2970.72 2305.02,2970.73 v2(2317.19,2982.9)
  L8 BOTTOM w15: C145_1.1@2280.64,2946.35 v2(2317.19,2982.9) ; C144_1.1@2478.51,2859.53 v2(2478.51,2944.72)
  other v3: 254.07,1123.95 273.75,1123.95 293.44,1123.95 254.07,1143.64 273.75,1143.64 293.44,1143.64 254.07,1163.32 273.75,1163.32 293.44,1163.32
AWR_1_1V8_FILT: C15.1 C16.1 C17.1 C128_1.1 C129_1.1 C130_1.1 C131_1.1 C132_1.1 C133_1.1 C134_1.1 C135_1.1 L2.2 U1_1.B11 U1_1.B12 U1_1.D13 U1_1.F5 U1_1.K5 U1_1.K13 | length 757.4
  L1 TOP w15: v2(2360.39,3149.45) 2371.19,3138.65 2371.19,3132.45 2376.71,3126.93 U1_1.K5@2376.71,3124.27 ; U1_1.K13@2376.71,2919.55 2376.71,2935.82 v2(2382.03,2941.14) ; U1_1.F5@2479.07,3124.27 2479.07,3130.78 v2(2489.99,3141.7) ; v2(2529,2959.6) 2530.25,2958.35 U1_1.D13@2530.25,2919.55 ; U1_1.B12@2581.44,2945.13 2616.49,2945.13 2648.59,2913.04 2659.87,2913.04 C132_1.1@2666.84,2906.06 v3(2666.84,2885.69) ; U1_1.B11@2581.44,2970.72 2625.64,2970.72 2654.35,2942.02 C131_1.1@2666.84,2942.02 v3(2666.84,2962.39)
  L8 BOTTOM w12: v2(2529,2959.6) 2533.4,2964 2589.32,2964 2605.98,2980.66 C134_1.1@2605.98,3005.49
  L8 BOTTOM w15: v2(2360.39,3149.45) 2388.15,3121.69 C129_1.1@2389.89,3121.69 ; C135_1.1@2381.3,2906 2381.3,2940.41 v2(2382.03,2941.14) ; v2(2489.99,3141.7) 2487.72,3143.97 C128_1.1@2487.72,3221.01 2487.72,3268.62 C130_1.1@2499.9,3280.8
  L8 BOTTOM w20: v3(2666.84,2885.69) 2666.84,2885.27 C133_1.1@2714.22,2837.89
  other v3: 243.93,2045.24 263.62,2045.24 243.93,2064.92 263.62,2064.92 243.93,2084.61 263.62,2084.61 243.93,2104.29 263.62,2104.29 243.93,2123.98 263.62,2123.98 2516.21,3362.33 2517.58,3381.47 2524.35,3400.18 2536.26,3416.1
AWR_1_BSS_LOGGER: J4.80 R14_1.1 | length 3684.5
  L1 TOP w10.5: v2(1992.5,3260.5) 2008,3276 2040.2,3276 R14_1.1@2070.2,3246
  L6 SIGNAL 3 w6.9: v2(1992.5,3260.5) 2005.31,3273.31 2042.89,3273.31 2075.28,3240.92 2075.28,2996.77 1988.89,2910.38 1988.89,2408.16 2124.57,2272.48 2124.57,1473.4 2545.97,1052 2545.97,958.13 2655.1,849 2766.24,849 2814.44,897.2 3037.13,897.2 3094.78,839.56 3094.78,784.49 3097,782.27 v2(3097,646)
  L8 BOTTOM w7.75: J4.80@3078.23,743.02 3078.23,706.77 3097,688 v2(3097,646)
AWR_1_CSI2_CLK_N: J4.20 U1_1.J14 | length 2300.2
  L1 TOP w4: U1_1.J14@2402.3,2893.95 2414.89,2881.37 2414.89,2862.68
  L1 TOP w6.5: 2414.89,2862.68 2414.89,2646.11 v2@2425,2636
  L8 BOTTOM w5.25: v2(2425,2635.88) 2414,2624.88 2414,2590.87 3074,1930.87 3074,1637.36 3074,1634.99 3078.66,1630.33 3096.58,1630.33 3111.09,1615.83 3111.09,1591.62 3096.77,1577.31 3081.29,1577.31 3073.95,1569.96 3073.95,1535.72 3079.79,1529.88 3093.88,1529.88 3109.15,1514.6 3109.15,1487.56 3094.42,1472.83 3079.61,1472.83 3074,1467.21 3074,1027.79 3078.23,1023.56 J4.20@3078.23,979.12
AWR_1_CSI2_CLK_P: J4.19 U1_1.J15 | length 2270.9
  L1 TOP w6.5: v2@2390,2635 2402.89,2647.89 2402.89,2867.78 U1_1.J15@2402.3,2868.36
  L8 BOTTOM w5.25: v2(2390,2634.88) 2402,2622.88 2402,2585.9 3062,1925.9 3062,1632.39 3062,1630.02 3073.68,1618.33 3091.61,1618.33 3099.09,1610.86 3099.09,1596.59 3091.8,1589.31 3076.32,1589.31 3061.95,1574.93 3061.95,1530.75 3074.82,1517.88 3088.91,1517.88 3097.15,1509.63 3097.15,1492.53 3089.45,1484.83 3074.64,1484.83 3062,1472.18 3062,1027.03 3058.54,1023.57 J4.19@3058.54,979.12
AWR_1_CSI2_TX0_N: J4.29 U1_1.G14 | length 2300.4
  L1 TOP w4: U1_1.G14@2453.48,2893.95 2453.48,2886.52 2466.07,2873.93 2466.07,2854
  L1 TOP w6.5: 2466.07,2854 2466.07,2774.57 2476.64,2764 2484.2,2764 v2@2496,2775.8
  L8 BOTTOM w5.25: v2(2496,2775.68) 2508.42,2763.26 2551.94,2763.26 2581.13,2734.07 2581.13,2645.92 3251,1976.05 3251,1026.88 3255.39,1022.49 J4.29@3255.39,979.12
AWR_1_CSI2_TX0_P: J4.28 U1_1.G15 | length 2270.7
  L1 TOP w6.5: U1_1.G15@2453.48,2868.36 2454.07,2867.78 2454.07,2769.59 2471.66,2752 2482,2752 v2@2496,2738
  L8 BOTTOM w5.25: v2(2496,2737.88) 2509.38,2751.26 2546.97,2751.26 2569.13,2729.1 2569.13,2640.95 3239,1971.08 3239,1026.86 3235.71,1023.57 J4.28@3235.71,979.12
AWR_1_CSI2_TX1_N: J4.26 U1_1.H14 | length 2300.4
  L1 TOP w4: U1_1.H14@2427.89,2893.95 2440.48,2881.37 2440.48,2860.89
  L1 TOP w6.5: 2440.48,2860.89 2440.48,2754.25 2466.72,2728.01 2466.72,2707.06 v2@2479.72,2694.06
  L8 BOTTOM w5.25: v2(2479.72,2693.94) 2467.32,2681.54 2467.32,2648.16 3197,1918.48 3197,1405.8 3184.13,1392.92 3164.76,1392.92 3151.89,1380.05 3151.89,1357.89 3162.99,1346.79 3177.31,1346.79 3193,1331.1 3193,1026.9 3196.34,1023.56 J4.26@3196.34,979.12
AWR_1_CSI2_TX1_P: J4.25 U1_1.H15 | length 2269.4
  L1 TOP w6.5: U1_1.H15@2427.89,2868.36 2428.48,2867.78 2428.48,2749.27 2454.72,2723.03 2454.72,2705.46 v2@2443.32,2694.06
  L8 BOTTOM w5.25: v2(2443.32,2693.94) 2455.32,2681.94 2455.32,2643.19 3185,1913.51 3185,1410.77 3179.16,1404.92 3159.79,1404.92 3139.89,1385.03 3139.89,1352.91 3158.02,1334.79 3172.34,1334.79 3181,1326.13 3181,1027.92 3176.65,1023.57 J4.25@3176.65,979.12
AWR_1_CSI2_TX2_N: J4.17 U1_1.K14 | length 2300.3
  L1 TOP w4: U1_1.K14@2376.71,2893.95 2389.3,2881.37 2389.3,2858
  L1 TOP w6.5: v2@2373.96,2558 2360,2571.96 2360,2643 2389.3,2672.3 2389.3,2858
  L8 BOTTOM w5.25: v2@2374.13,2557.88 v2(2373.96,2557.88) 3015.04,1916.8 3015.04,1615.09 3002.34,1602.4 2987.54,1602.4 2979.84,1594.69 2979.84,1577.6 2988.08,1569.35 3002.17,1569.35 3015.04,1556.48 3015.04,1512.29 3000.67,1497.92 2985.19,1497.92 2977.9,1490.63 2977.9,1476.37 2985.38,1468.89 3000.93,1468.89 3015,1454.82 3015,1027.91 3019.17,1023.74 J4.17@3019.17,979.12
AWR_1_CSI2_TX2_P: J4.16 U1_1.K15 | length 2289.3
  L1 TOP w6.5: v2@2337.56,2558 2348,2568.44 2348,2647.98 2377.3,2677.28 2377.3,2867.78 U1_1.K15@2376.71,2868.36
  L8 BOTTOM w5.25: v2(2337.56,2557.88) 2361.15,2534.29 2380.58,2534.29 3003.04,1911.83 3003.04,1620.07 2997.37,1614.4 2982.57,1614.4 2967.84,1599.66 2967.84,1572.63 2983.11,1557.35 2997.2,1557.35 3003.04,1551.51 3003.04,1517.26 2995.7,1509.92 2980.22,1509.92 2965.9,1495.6 2965.9,1471.4 2980.41,1456.89 2995.96,1456.89 3003,1449.85 3003,1027.08 2999.49,1023.57 J4.16@2999.49,979.12
AWR_1_CSI2_TX3_N: J4.13 U1_1.L14 | length 2300.5
  L1 TOP w4: U1_1.L14@2351.12,2893.95 2363.71,2881.37 2363.71,2860
  L1 TOP w6.5: v2@2327.4,2606 2316,2617.4 2316,2643 2363.71,2690.71 2363.71,2860
  L8 BOTTOM w5.25: v2(2327.4,2605.88) 2315,2593.48 2315,2502.7 2936,1881.7 2936,1625.23 2923.3,1612.53 2908.5,1612.53 2900.79,1604.83 2900.79,1587.73 2909.04,1579.48 2920.59,1579.48 2936,1564.08 2936,1522.42 2921.63,1508.05 2906.14,1508.05 2898.86,1500.76 2898.86,1486.5 2906.34,1479.03 2918.92,1479.03 2936,1461.95 2936,1028 2940.43,1023.57 J4.13@2940.43,979.12
AWR_1_CSI2_TX3_P: J4.12 U1_1.L15 | length 2269.9
  L1 TOP w6.5: v2@2291,2606 2304,2619 2304,2647.98 2351.71,2695.69 2351.71,2867.78 U1_1.L15@2351.12,2868.36
  L8 BOTTOM w5.25: v2(2291,2605.88) 2303,2593.88 2303,2497.73 2924,1876.73 2924,1630.2 2918.33,1624.53 2903.53,1624.53 2888.79,1609.8 2888.79,1582.76 2904.07,1567.48 2915.62,1567.48 2924,1559.11 2924,1527.39 2916.66,1520.05 2901.17,1520.05 2886.86,1505.74 2886.86,1481.53 2901.37,1467.03 2913.95,1467.03 2924,1456.98 2924,1026.82 2920.75,1023.57 J4.12@2920.75,979.12
AWR_1_DIG_SYNCIN: R132.2 R185_1.2 U1_1.N10 | length 4196.1
  L1 TOP w10.5: U1_1.N10@2299.94,2996.31 2310.89,3007.27 2329.83,3007.27 2337.45,3014.89 2349.34,3014.89 v2(2354.59,3020.14)
  L8 BOTTOM w7.75: R132.2@2106.16,3598.46 2106.16,3577.2 2118.01,3565.36 2386.17,3565.36 2397.11,3554.41 2397.11,3533.37 2386.26,3522.52 2172.07,3522.52 2161.09,3511.54 1996.75,3511.54 1986.13,3500.92 1986.13,3480.23 1997.12,3469.24 2161.5,3469.24 2172.22,3458.53 2172.22,3442.5 2157.38,3427.66 1975.83,3427.66 1930.95,3472.54 1930.95,3535.95 1890.81,3576.09 1531.25,3576.09 1514.6,3592.74 1514.6,3705.29 1496.89,3723.01 1462.89,3723.01 1448.29,3708.4 1448.29,3552.41 1475.43,3525.27 1865.92,3525.27 1880.97,3510.22 1880.97,3484.74 1867.74,3471.51 1593.91,3471.51 1584.5,3462.1 1584.5,3434.16 1592.1,3426.56 1893.39,3426.56 1935.83,3384.12 2082.62,3384.12 2105.88,3360.86 2105.88,3310.23 2117.18,3298.92 2142.14,3298.92 2171.95,3269.11 2171.95,3223.59 2151.38,3203.01 2107.87,3203.01 2096.11,3191.25 2096.11,3110.71 2125.82,3081 R185_1.2@2155.9,3081 2254.44,3081 2271.84,3063.6 2326.4,3063.6 2354.59,3035.41 v2(2354.59,3020.14)
AWR_1_DIG_SYNCIN_RS: R132.1 U8.16 | length 81.4
  L8 BOTTOM w7.75: R132.1@2106.16,3645.7 2106.16,3685.25 2122.73,3701.82 U8.16@2141.18,3701.82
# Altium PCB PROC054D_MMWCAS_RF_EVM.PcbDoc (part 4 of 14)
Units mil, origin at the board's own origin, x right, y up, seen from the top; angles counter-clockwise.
Board outline 6299.21 x 5370.07 mil, 8 copper layers (L1 TOP, L2 GND, L3 SIGNAL 1, L4 GND, L5 SIGNAL 2, L6 SIGNAL 3, L7 GND, L8 BOTTOM), stack 53.5 mil thick; 775 components, 552 nets, 2648 pads, 7845 vias.

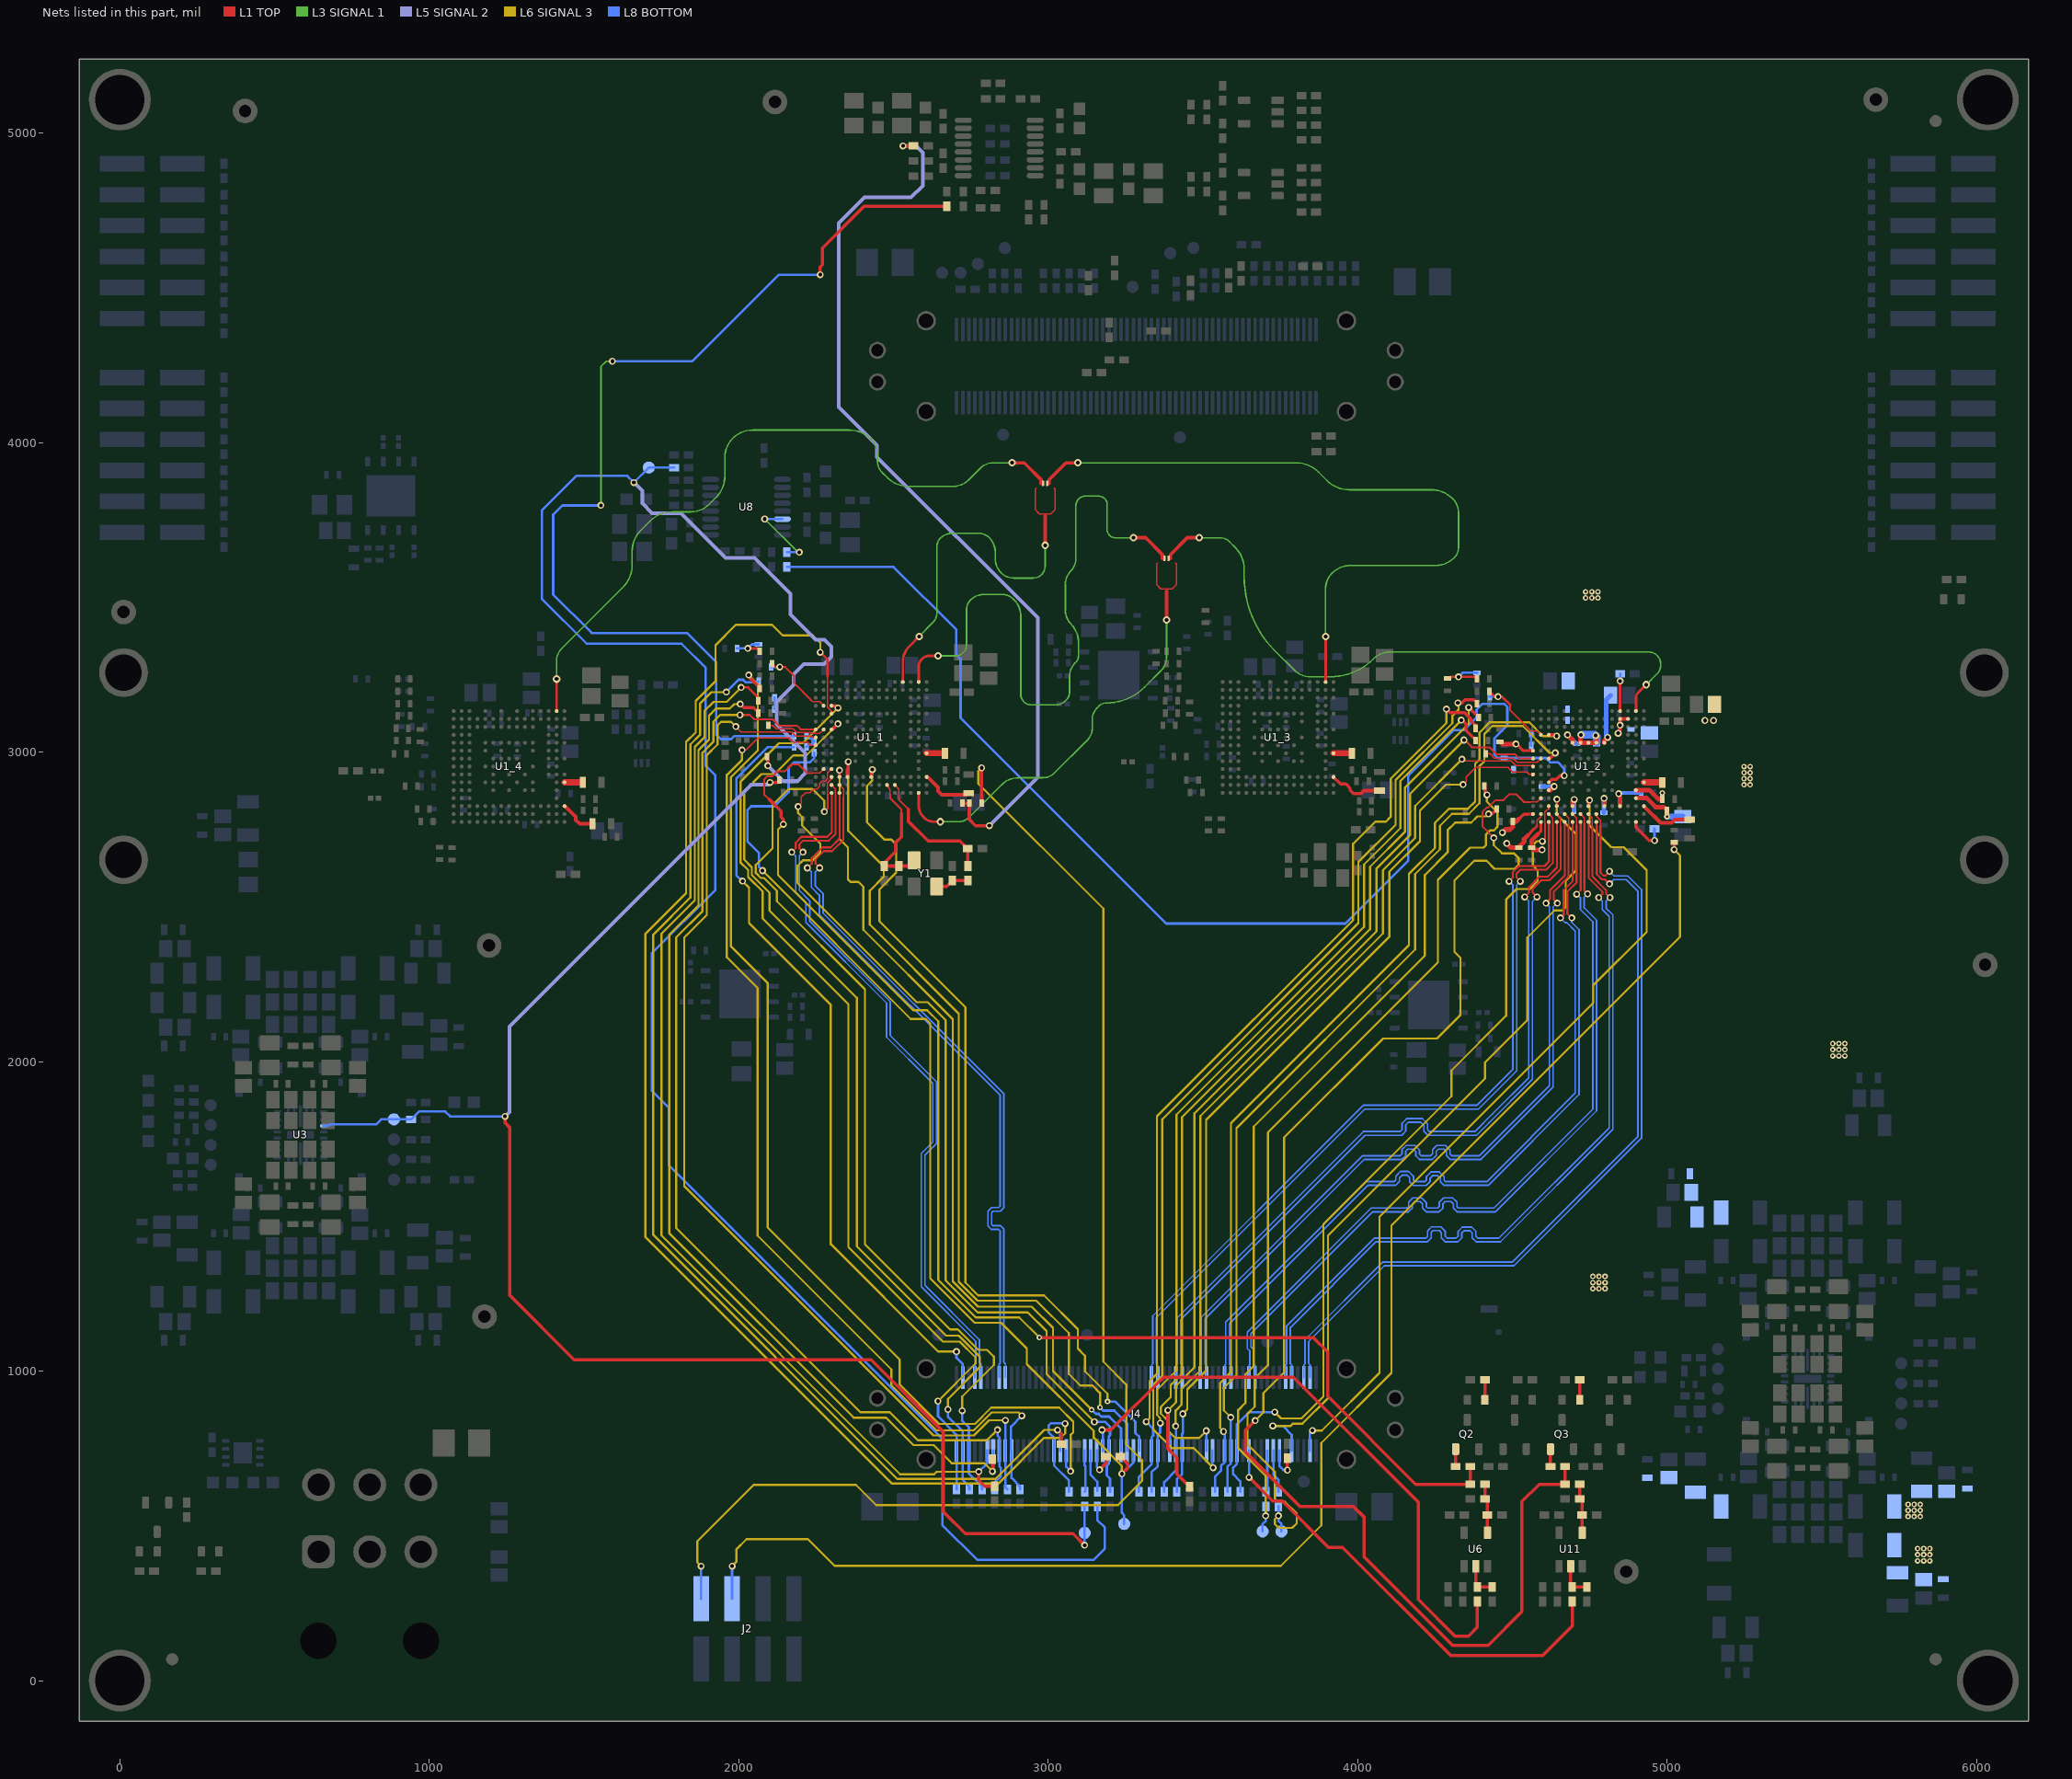
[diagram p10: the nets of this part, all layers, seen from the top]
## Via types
v1: diameter 13.77/15.74 (per signal layer), hole 5.9, L1 TOP to L2 GND, tented both sides, 5522 vias
v2: diameter 22.4, hole 12.2, L1 TOP to L8 BOTTOM, tented both sides, 1522 vias
v3: diameter 18, hole 8, L1 TOP to L8 BOTTOM, tented both sides, 727 vias
v4: diameter 18, hole 7.87, L1 TOP to L8 BOTTOM, tented top, 50 vias
v5: diameter 24, hole 12, L1 TOP to L8 BOTTOM, tented both sides, 13 vias
v6: diameter 19.68, hole 7.87, L1 TOP to L8 BOTTOM, tented top, 10 vias
v7: diameter 13.77/15.74 (per signal layer), hole 5.9, L1 TOP to L2 GND, tented top, 1 vias

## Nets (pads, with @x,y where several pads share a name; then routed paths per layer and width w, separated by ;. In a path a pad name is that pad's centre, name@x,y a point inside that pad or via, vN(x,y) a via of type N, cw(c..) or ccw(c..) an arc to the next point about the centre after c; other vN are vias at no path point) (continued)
AWR_1_DIG_SYNCOUT: R1_1.1 R143.1 R148.1 TP1_1.1 | length 7059.6
  L1 TOP w10.5: v2(2094.1,2956) R1_1.1@2094.1,2985
  L5 SIGNAL 2 w12: v2(1661.14,3871.03) 1687.95,3844.22 1687.95,3803.71 1719.74,3771.92 1812.76,3771.92 1957.32,3627.36 2051.28,3627.36 2167.72,3510.93 2167.72,3445 2249.33,3363.39 2277.09,3363.39 2299.47,3341 2299.47,3307.75 2275.27,3283.54 2209.86,3283.54 2177.83,3251.51 2177.83,3217.8 2123.08,3163.05 2123.08,3089.41 2214.93,2997.55 2214.93,2931.98 2188.96,2906.01 2144.09,2906.01 v2(2094.1,2956)
  L8 BOTTOM w7.75: R143.1@1791.14,3919.29 TP1_1.1@1709.4,3919.29 v2(1661.14,3871.03) 1639.93,3892.23 1474.96,3892.23 1421.71,3838.99 1363.59,3780.87 1363.59,3495.41 1508.63,3350.37 1814.84,3350.37 1893.44,3271.77 1893.44,2955.42 1924.27,2924.58 1924.27,2555.16 1718.61,2349.5 1718.61,1906.97 1773.88,1851.7 1773.88,1665.42 2658.2,781.1 2658.2,502.93 2771.23,389.9 3145.86,389.9 3183.2,427.24 3183.2,494.47 3159,518.67 R148.1@3159,563.18
AWR_1_FMCW_CLKOUT: R136.1 R136.2 U1_1.B1 U1_1.B15 U1_2.B1 | length 5817.5
  L1 TOP w5.08: 3353.17,3610.43 3350.56,3607.82 3350.56,3541.35 3364.37,3527.54 3382.46,3527.54 3382.46,3519.25 ; 3382.48,3527.56 3400.57,3527.56 3414.38,3541.37 3414.38,3607.84 3411.77,3610.45
  L1 TOP w8.4: U1_1.B15@2581.44,2868.36 2581.43,2828.39 ccw(c2635.68,2828.39) 2597.32,2790.03 2600.15,2787.2 ccw(c2629.12,2816.17) 2629.12,2775.2 v5(2651.3,2775.2) ; U1_1.B1@2581.44,3226.63 2581.43,3275.9 cw(c2616.53,3275.9) 2616.53,3311 v5(2644,3311) ; U1_2.B1@4899.44,3132.63 4899.43,3174.07 cw(c4924.44,3174.06) 4906.76,3191.75 v5(4933,3218)
  L1 TOP w11.26: v5(3276.3,3692.56) 3315.28,3692.56 3369.47,3638.37 3369.47,3626.25 ; v5(3382.46,3426.29) 3382.46,3519.25 ; 3395.45,3626.25 3395.45,3638.37 3449.62,3692.54 v5(3488.62,3692.54)
  L3 SIGNAL 1 w5: v5(2644,3311) 2704.19,3311 ccw(c2704.19,3337) 2722.57,3318.62 2725.29,3321.34 ccw(c2698.54,3348.09) 2736.38,3348.09 2736.38,3461.86 ; v5(2651.3,2775.2) 2710.97,2775.2 ccw(c2710.96,2821.62) 2743.79,2788.8 2849.7,2894.71 cw(c2903.65,2840.76) 2903.65,2917.06 2984.15,2917.06 ccw(c2984.15,2965.89) 3018.68,2931.36 3127.37,3040.05 ccw(c3090.91,3076.51) 3142.47,3076.51 3142.47,3105.45 cw(c3194.85,3105.45) 3157.8,3142.48 3164.16,3148.83 cw(c3188.71,3124.28) 3188.71,3159 ccw(c3188.71,3332.22) 3311.19,3209.74 3363.93,3262.47 ccw(c3319.18,3307.21) 3382.46,3307.21 v5(3382.46,3426.29) ; 2736.38,3462.57 cw(c2775.58,3461.86) 2747.86,3489.58 2750.81,3492.53 cw(c2791.26,3452.08) 2791.26,3509.28 2852.74,3509.28 cw(c2852.74,3462.35) 2885.93,3495.54 2890.2,3491.26 cw(c2839.11,3440.18) 2911.36,3440.18 2911.36,3187.1 ccw(c2946.31,3187.1) 2921.6,3162.39 ccw(c2944.46,3185.25) 2944.46,3152.92 3025.78,3152.92 ccw(c3025.78,3192.93) 3054.07,3164.64 3060.5,3171.07 ccw(c3039.54,3192.03) 3069.18,3192.03 3069.18,3245.78 cw(c3128.25,3245.78) 3086.48,3287.55 3090.49,3291.56 ccw(c3072.66,3309.38) 3097.88,3309.38 3097.88,3355.08 ccw(c3014.55,3355.08) 3073.47,3414 cw(c3116.89,3457.42) 3055.49,3457.42 3055.49,3542.68 cw(c3114.99,3542.68) 3072.91,3584.76 ccw(c3032.71,3624.96) 3089.57,3624.96 3089.57,3795.47 cw(c3122.17,3795.47) 3099.11,3818.53 cw(c3119.67,3797.97) 3119.67,3827.04 3162.01,3827.04 cw(c3162.01,3796.65) 3183.5,3818.14 cw(c3166.34,3800.98) 3190.61,3800.98 3190.61,3716.26 ccw(c3210.46,3716.26) 3196.42,3702.23 3198.89,3699.75 ccw(c3216.26,3717.12) 3216.26,3692.56 v5(3276.3,3692.56) ; v5(3488.62,3692.54) 3554.81,3692.54 cw(c3554.81,3648.07) 3586.25,3679.53 ; 3586.25,3679.52 3605.04,3660.73 cw(c3536.37,3592.07) 3633.48,3592.07 3633.48,3567.36 ccw(c3973.24,3567.36) 3732.99,3327.12 3794.92,3265.19 ; 3794.93,3265.18 ccw(c3847.65,3317.92) 3847.65,3243.35 3911.53,3243.35 ccw(c3911.53,3440.85) 4051.19,3301.19 cw(c4105.11,3247.27) 4105.11,3323.53 4940.44,3323.53 cw(c4940.44,3284.01) 4968.38,3311.96 cw(c4942.16,3285.74) 4979.24,3285.74 4979.24,3279.71 cw(c4941.91,3279.71) 4968.31,3253.31 v5(4933,3218)
AWR_1_FMCW_SYNCOUT: R140.1 R140.2 U1_1.D1 U1_3.B1 U1_4.B1 | length 6029
  L1 TOP w5.08: 2960.81,3852.44 2958.2,3849.83 2958.2,3783.36 2972.01,3769.55 2990.1,3769.55 ; 2990.1,3761.26 2990.1,3769.55 ; 3019.41,3852.46 3022.02,3849.85 3022.02,3783.38 3008.21,3769.57 2990.12,3769.57
  L1 TOP w8.4: U1_4.B1@1411.44,3132.63 v5(1411.43,3236) ; U1_1.D1@2530.26,3226.63 2530.25,3291 cw(c2603.3,3290.99) 2551.65,3342.65 v5(2583,3374.01) ; U1_3.B1@3896.44,3226.63 v5(3896.43,3374)
  L1 TOP w11.26: v5(2883.94,3934.57) 2922.92,3934.57 2977.11,3880.38 2977.11,3868.26 ; v5(2990.1,3668.3) 2990.1,3761.26 ; 3003.09,3868.26 3003.09,3880.38 3057.26,3934.55 v5(3096.26,3934.55)
  L3 SIGNAL 1 w5: v5(1411.43,3236) 1411.43,3296.01 cw(c1465.58,3296.01) 1427.29,3334.3 1550.53,3457.53 1626.31,3533.31 ccw(c1555.6,3604.02) 1655.6,3604.02 1655.6,3648.17 cw(c1753.2,3648.17) 1684.18,3717.19 1714.06,3747.06 cw(c1784.51,3676.62) 1784.51,3776.24 1845.64,3776.24 ccw(c1845.64,3858.84) 1904.04,3800.44 1925.98,3822.38 ccw(c1855.27,3893.09) 1955.27,3893.09 1955.27,3953.24 cw(c2040.87,3953.24) 1980.34,4013.77 cw(c2044.92,3949.19) 2044.92,4040.51 2357.58,4040.51 cw(c2357.58,3940.51) 2428.29,4011.22 cw(c2381.08,3964.02) 2447.84,3964.02 2447.84,3941.83 ccw(c2502.6,3941.83) 2463.83,3903.17 ccw(c2502.6,3941.83) 2463.88,3903.11 2481.11,3885.88 ccw(c2546,3950.75) 2546,3859 2694.74,3859 ccw(c2694.74,3924.81) 2741.28,3878.28 2780,3917 cw(c2822.42,3874.58) 2822.42,3934.57 v5(2883.94,3934.57) ; v5(2583,3374.01) 2625.86,3416.89 ccw(c2590.18,3452.57) 2640.63,3452.57 2640.63,3665.31 cw(c2677.41,3665.31) 2651.4,3691.32 cw(c2688.3,3654.42) 2688.3,3706.6 2777.61,3706.6 cw(c2777.61,3662.2) 2809,3693.6 cw(c2760.7,3645.31) 2829,3645.31 2829,3624.87 ccw(c2893.87,3624.87) 2848,3579 ccw(c2889.04,3620.04) 2889.04,3562 2951.13,3562 ccw(c2951.13,3600.97) 2990.1,3600.97 v5(2990.1,3668.3) ; v5(3096.26,3934.55) 3802.12,3934.55 cw(c3802.12,3834.55) 3872.83,3905.26 3901.12,3876.97 ccw(c3971.83,3947.68) 3971.83,3847.68 4236.99,3847.68 cw(c4236.99,3747.68) 4307.7,3818.39 cw(c4262.21,3772.91) 4326.54,3772.91 4326.54,3661.8 cw(c4279.32,3661.8) 4312.71,3628.42 cw(c4251.34,3689.78) 4251.34,3603 3977.36,3603 ccw(c3977.36,3517.63) 3917,3578 ccw(c3966.66,3528.34) 3896.43,3528.34 v5(3896.43,3374)
AWR_1_GPIO_0: J4.61 R16_1.2 U1_1.N4 | length 3146
  L1 TOP w10.5: U1_1.N4@2299.94,3149.86 2313.82,3149.86 v2(2320.99,3142.69)
  L6 SIGNAL 3 w6.9: v2(2320.99,3142.69) 2206.68,3028.38 2129.84,3028.38 2005.54,2904.08 2005.54,2643.9 2030.3,2619.15 2030.3,2596.61 2077.11,2549.8 2077.11,2462.65 2354.47,2185.3 2354.47,1400.45 2659.46,1095.46 2713.71,1095.46 2765.43,1043.74 2765.43,1024.43 v2(2644,903)
  L8 BOTTOM w7.75: v2(2644,903) 2644,854.04 2704.21,793.83 J4.61@2704.21,743.02 R16_1.2@2704.21,618.14
AWR_1_GPIO_1: J4.62 R17_1.2 U1_1.N7 | length 3088
  L1 TOP w10.5: U1_1.N7@2299.94,3073.09 2302.38,3073.09 v2(2320.69,3091.4)
  L6 SIGNAL 3 w6.9: v2(2320.69,3091.4) 2218.38,2989.09 2175.87,2989.09 2115.99,2929.21 2073.89,2929.21 2017.73,2873.05 2017.73,2652.48 2042.53,2627.68 2042.53,2602.57 2099.55,2545.55 2099.55,2487.96 2381.78,2205.72 2381.78,1402.96 2669.85,1114.9 2711.1,1114.9 2779.58,1046.41 2779.58,1013.56 2676,909.98 v2(2676,876)
  L8 BOTTOM w7.75: v2(2676,876) 2676,852.79 2723.9,804.89 J4.62@2723.89,743.02 2723.89,648.2 2745.21,626.89 R17_1.2@2745.21,618.14
AWR_1_GPIO_2: J4.63 R18_1.2 U1_1.N13 | length 3020.1
  L1 TOP w4: 2287.44,2863 2287.44,2900.5 2299.94,2913 U1_1.N13@2299.94,2919.55
  L1 TOP w6: v2(2276.5,2807.5) 2287.44,2818.44 2287.44,2863
  L6 SIGNAL 3 w6.9: v2(2276.5,2807.5) 2276.5,2842.88 2238.36,2881.02 2161.05,2881.02 2109.03,2829 2109.03,2689.03 2055.37,2635.37 2055.37,2609.24 2071.26,2593.35 2081.78,2593.35 2123.28,2551.85 2123.28,2518.25 2408.08,2233.45 2408.08,1409.53 2682.89,1134.72 2708.1,1134.72 2774.02,1068.81 2802.25,1068.81 2824.47,1046.59 2824.47,1020 2722,917.53 v2(2722,872)
  L8 BOTTOM w7.75: v2(2722,872) 2722,839.99 2743.58,818.41 J4.63@2743.58,743.02 2743.58,669.11 2786.21,626.49 R18_1.2@2786.21,618.14
AWR_1_LVDS_FRCLK_N: J4.9 U1_1.M14 | length 2300.3
  L1 TOP w4: U1_1.M14@2325.53,2893.95 2338.12,2881.37 2338.12,2853
  L1 TOP w6.5: v2@2261.62,2626 2248,2639.62 2248,2653 2275,2680 2301.98,2680 2338.12,2716.14 2338.12,2853
  L8 BOTTOM w5.25: v2(2261.62,2625.88) 2247,2611.26 2247,2568.35 2272.44,2542.91 2272.44,2480.15 2857,1895.59 2857,1528.59 2844.99,1516.58 2821.67,1516.58 2817.09,1512 2817.09,1474.07 2821.13,1470.04 2845.36,1470.04 2857,1458.39 2857,1028.26 2861.69,1023.57 J4.9@2861.69,979.12
AWR_1_LVDS_FRCLK_P: J4.8 U1_1.M15 | length 2268.5
  L1 TOP w6.5: v2@2222,2626 2236,2640 2236,2657.98 2270.02,2692 2297,2692 2326.12,2721.12 2326.12,2867.78 U1_1.M15@2325.53,2868.36
  L8 BOTTOM w5.25: v2(2222,2625.88) 2235,2612.88 2235,2563.38 2260.44,2537.94 2260.44,2475.18 2845,1890.62 2845,1533.56 2840.02,1528.58 2816.7,1528.58 2805.09,1516.97 2805.09,1469.1 2816.16,1458.04 2840.38,1458.04 2845,1453.42 2845,1026.56 2842.01,1023.57 J4.8@2842.01,979.12
AWR_1_LVDS_VALID_N: J4.5 U1_1.N14 | length 2300.5
  L1 TOP w4: U1_1.N14@2299.94,2893.95 2312.53,2881.37 2312.53,2861.89
  L1 TOP w6.5: v2@2207.7,2676.7 2196,2688.4 2196,2702.02 2207.98,2714 2290.98,2714 2312.53,2735.55 2312.53,2861.89
  L8 BOTTOM w5.25: v2(2207.7,2676.58) 2196,2664.88 2196,2553.12 2229.15,2519.97 2229.15,2454.53 2489.66,2194.02 2489.66,2084.1 2620.46,1953.3 2638.86,1934.91 2638.86,1735.37 2601.64,1698.16 2601.64,1277.39 2778,1101.03 2778,1028.52 2782.95,1023.57 J4.5@2782.95,979.12
AWR_1_LVDS_VALID_P: J4.4 U1_1.N15 | length 2269.8
  L1 TOP w6.5: v2@2171.3,2676.7 2184,2689.4 2184,2707 2203,2726 2286,2726 2300.53,2740.53 2300.53,2867.78 U1_1.N15@2299.94,2868.36
  L8 BOTTOM w5.25: v2(2171.3,2676.58) 2184,2663.88 2184,2548.15 2217.15,2515 2217.15,2449.56 2477.66,2189.05 2477.66,2079.13 2617,1939.79 2626.86,1929.93 2626.86,1740.34 2589.64,1703.13 2589.64,1272.42 2766,1096.06 2766,1026.3 2763.27,1023.57 J4.4@2763.27,979.12
AWR_1_MCU_CLKOUT: R5_1.1 R213.1 R214.1 | length 65.1
  L8 BOTTOM w7.75: R214.1@2218.59,3016.15 2226.7,3024.26 2233.8,3024.26 R5_1.1@2243.7,3034.15 2233.8,3044.05 2226.7,3044.05 R213.1@2218.59,3052.15
AWR_1_MCU_CLKOUT_CONN: J4.2 R214.2 | length 2501.1
  L6 SIGNAL 3 w6.9: v2(2012,2583) 2033.22,2561.78 2033.22,2447.41 2297.56,2183.06 2297.56,1410.04 2644.66,1062.95 v2(2703.52,1062.95)
  L8 BOTTOM w7.75: v2(2012,2583) 1992.47,2602.53 1992.47,2914.75 2093.87,3016.15 R214.2@2178.59,3016.15 ; v2(2703.52,1062.95) 2703.52,1042.87 2723.89,1022.5 J4.2@2723.89,979.24
AWR_1_MCU_CLKOUT_RS: R122.1 R213.2 | length 3365.5
  L1 TOP w10.5: v2(2263.58,4542.68) 2263.58,4567.65 2270.37,4574.44 2270.37,4628.78 2404.97,4763.38 R122.1@2672.94,4763.38
  L3 SIGNAL 1 w5.1: v2(1554.77,3796.99) 1554.77,4246.17 1571.52,4262.92 v2(1591.76,4262.92)
  L8 BOTTOM w7.75: v2(1554.77,3796.99) 1429.98,3796.99 1400.42,3767.43 1400.42,3509.26 1524.66,3385.02 1833.18,3385.02 1926.93,3291.27 1926.93,3057.59 1942.39,3042.12 1976.11,3042.12 1986.15,3052.15 R213.2@2178.59,3052.15 ; v2(1591.76,4262.92) 1849.87,4262.92 2129.63,4542.68 v2(2263.58,4542.68)
AWR_1_MSS_LOGGER: J4.79 R15_1.1 | length 3514.5
  L1 TOP w10.5: v2(2032,3249) 2032,3244.1 R15_1.1@2070.1,3206
  L6 SIGNAL 3 w6.9: v2(2032,3249) 2061.39,3219.61 2061.39,3005.5 1975.14,2919.25 1975.14,2372.08 2093.09,2254.13 2093.09,1464.39 2519.99,1037.5 2519.99,957 2647.52,829.47 2763.54,829.47 2815.87,881.79 3035.71,881.79 3081,836.51 3081,802 3072.5,793.5 v2(3072.5,676.5)
  L8 BOTTOM w7.75: J4.79@3058.54,743.02 3058.54,690.46 v2(3072.5,676.5)
AWR_1_NERROR_IN: R177_1.1 U1_1.P7 | length 193.7
  L1 TOP w4: R177_1.1@2096.4,3086 2110.36,3086 2121.56,3074.8 2175.25,3074.8 2187.05,3063 2233,3063 2235.5,3060.5 2261.76,3060.5 U1_1.P7@2274.35,3073.09
AWR_1_NERROR_OUT: R9_1.1 R154.1 | length 36.9
  L8 BOTTOM w7.75: R154.1@2115.9,3139.1 R9_1.1@2115.9,3176
AWR_1_NRST: R198.2 R208.2 U1_1.P12 | length 4253.1
  L1 TOP w4: 2236.32,2932.64 2261.85,2932.64 U1_1.P12@2274.35,2945.13
  L1 TOP w6: 2098.54,2847.45 2082.43,2863.57 2082.43,2912.6 2091.03,2921.2 2108.4,2921.2 2125.4,2938.2 2149.5,2938.2 2171.5,2960.2 2193.65,2960.2 2221.21,2932.64 2236.32,2932.64
  L1 TOP w10.5: 2098.54,2847.45 2136.63,2809.37 2136.63,2789.84 2144,2782.48 v2@2144,2767 ; v3(2971.57,1108.47) 3856.77,1108.47 3903.44,1061.79 3903.44,918.78 4187.82,634.4 R208.2@4364.23,634.4 R198.2@4364.23,691.84
  L6 SIGNAL 3 w6.9: v2@2144,2767 2127.25,2750.25 2127.25,2603.08 2564.65,2165.68 2609.07,2165.68 2644.67,2130.07 2644.67,1294.83 2766.03,1173.47 2906.57,1173.47 v3(2971.57,1108.47)
  other v2: 2144,2766.88
AWR_1_NRST_HOST: J4.85 R191.1 | length 1977.4
  L1 TOP w10.5: v2(3174,810) 3202.16,810 3372.79,980.63 3791.9,980.63 4195.89,576.63 4195.89,262.42 4314.62,143.69 4358.07,143.69 4386.99,172.61 R191.1@4386.99,255.59
  L8 BOTTOM w7.75: v2(3174,810) 3176.65,807.35 J4.85@3176.65,743.02
AWR_1_NRST_HOST_GS: R86.1 R191.2 U6.2 | length 116.2
  L1 TOP w10.5: U6.2@4381.99,369.58 4381.99,307.83 R191.2@4386.99,302.83 R86.1@4434.39,302.83
AWR_1_NRST_LED: Q2.1 R198.1 | length 56.1
  L1 TOP w10.5: R198.1@4316.98,691.84 Q2.1@4316.98,747.96
AWR_1_NRST_LED_PW: DS4.1 R196.1 | length 65
  L1 TOP w10.5: DS4.1@4411.47,906.78 R196.1@4411.47,971.8
AWR_1_NRST_RS: C205.1 R206.1 R208.1 U6.4 | length 156.5
  L1 TOP w10.5: R206.1@4411.47,587.15 R208.1@4411.47,634.4 ; U6.4@4419.39,477.85 C205.1@4419.39,535.63 R206.1@4419.39,587.15
AWR_1_OSC_CLKOUT: R2_1.1 R107.1 R186.1 | length 2961.4
  L1 TOP w10.5: v2(2531.11,4958.61) R107.1@2564.74,4958.61 ; R2_1.1@2722.88,2834.89 R186.1@2745.21,2834.89 2745.21,2782.79 2765.74,2762.25 v2(2809.92,2762.25)
  L5 SIGNAL 2 w12: v2(2531.11,4958.61) 2573.38,4958.61 2595.11,4936.89 2595.11,4830.2 2557.04,4792.13 2405.94,4792.13 2322.67,4708.86 2322.67,4114.56 2446.36,3990.87 2446.36,3953.28 2965.94,3433.7 2965.94,2918.27 v2(2809.92,2762.25)
AWR_1_OSC_CLKOUT_CONN: J2.1 R186.2 | length 4404.4
  L1 TOP w10.5: R186.2@2785.21,2834.89 v2(2785.21,2949.21)
  L6 SIGNAL 3 w6.9: v2(1878.45,369.78) 1866.25,381.98 1866.25,450.42 2048.13,632.3 2379.06,632.3 2444.1,567.26 3225.52,567.26 3303.08,644.83 3303.08,712.68 3252.76,763.01 3252.76,956.02 3178.36,1030.42 3178.36,2494.31 2774.39,2898.28 2774.39,2938.39 v2(2785.21,2949.21)
  L8 BOTTOM w7.75: J2.1@1878.45,264.5 v2(1878.45,369.78)
AWR_1_PMIC_CLKOUT: R4_1.1 R57.2 R149.1 TP2_1.1 TP5.1 U3.3 | length 5164.6
  L1 TOP w10.5: v2(1244.72,1823.21) 1244.72,1802.6 1259.36,1787.95 1259.36,1245.65 1468.47,1036.54 2428.05,1036.54 2661.86,802.73 2661.86,544.73 2732.05,474.55 3080.57,474.55 v2(3118,437.12) ; v2(2101,2902) 2123,2902 R4_1.1@2131,2910
  L5 SIGNAL 2 w12: v2(1244.72,1823.21) 1258.61,1837.11 1258.61,2113.21 2040.11,2894.71 2093.71,2894.71 v2(2101,2902)
  L8 BOTTOM w7.75: U3.3@658.34,1792.49 673.8,1792.49 679.09,1797.78 829.21,1797.78 844.68,1813.25 TP2_1.1@885.78,1813.25 R57.2@941.03,1813.25 966.64,1838.86 1051.49,1838.86 1067.14,1823.21 v2(1244.72,1823.21) ; v2(3118,437.12) TP5.1@3118,477.19 R149.1@3118,563.18
AWR_1_SCL: R98.2 R180_1.1 U1_1.P4 | length 265
  L1 TOP w4: 2233.92,3168.08 2239.25,3162.75 2261.46,3162.75 U1_1.P4@2274.35,3149.86
  L1 TOP w6: R180_1.1@2108,3286 2118.94,3275.06 v2(2132.81,3275.06) 2150.37,3275.06 2178.33,3247.09 2178.33,3223.67 2233.92,3168.08
  L8 BOTTOM w7.75: R98.2@2104.31,3275.06 v2(2132.81,3275.06)
AWR_1_SDA: R13_1.1 R99.2 R181_1.1 | length 119.4
  L1 TOP w8: v2(2029,3334.9) 2061.3,3334.9 R13_1.1@2070.2,3326
  L8 BOTTOM w7.75: R99.2@1994.65,3335.1 v2@2028.8,3335.1 ; v2(2029,3334.9) 2042.33,3348.23 R181_1.1@2063.84,3348.23
AWR_1_SOP0_TDO: J4.84 R147.2 | length 117.3
  L1 TOP w10.5: v2(3166,681) 3186.66,701.66 R147.2@3186.66,724
  L8 BOTTOM w7.75: J4.84@3156.97,743.02 3156.97,690.03 v2(3166,681)
AWR_1_SOP1_SYNCOUT: J4.83 R148.2 | length 138.6
  L8 BOTTOM w7.75: J4.83@3137.28,743.02 3137.28,664.54 3159,642.82 R148.2@3159,613.42
AWR_1_SOP2_PMICCLKOUT: J4.82 R149.2 | length 135.1
  L8 BOTTOM w7.75: J4.82@3117.6,743.02 3117.6,695.4 3120.76,692.24 3120.76,613.18 R149.2@3118,610.42
AWR_1_SPI_CLK1: J4.70 R182_1.2 U1_1.R9 | length 3331.2
  L1 TOP w4: v2(2010.75,3006.5) 2024.16,3006.5 2062.67,3045 2162.6,3045 2175.85,3031.75 2222,3031.75 2231.84,3021.91 U1_1.R9@2248.76,3021.91
  L6 SIGNAL 3 w6.9: v2(2010.75,3006.5) 2010.75,2975.48 1961.65,2926.38 1961.65,2337.19 2060.68,2238.16 2060.68,1438.1 2493.52,1005.26 2493.52,954.01 2639.1,808.43 2759.33,808.43 2817.34,866.44 2904.56,866.44 v2(2915,856)
  L8 BOTTOM w7.75: R182_1.2@2909.21,618.14 2909.21,627.45 2881.38,655.28 J4.70@2881.38,743.02 2880,744.4 2880,821 v2(2915,856)
AWR_1_SPI_CS1: J4.68 R175_1.1 U1_1.R7 | length 3586
  L1 TOP w6: v2(2004,3120) 2036,3120 2050,3106 2110,3106 2131.2,3084.8 2189.66,3084.8 2201.37,3073.09 U1_1.R7@2248.76,3073.09
  L6 SIGNAL 3 w6.9: v2(2004,3120) 1939.87,3120 1917.87,3097.99 1917.87,3033.07 1882.97,2998.17 1882.97,2486.36 1798.07,2401.46 1798.07,1462.14 2393.03,867.19 2487.79,867.19 2578.6,776.38 2801.98,776.38 v2(2836,810.4)
  L8 BOTTOM w7.75: R175_1.1@2827.21,618.14 2827.21,640.59 2847,660.38 2847,686.99 2842.01,691.98 2842.01,785.93 2836,791.94 v2(2836,810.4)
AWR_1_SPI_HOST_INTR1: J4.67 R10_1.2 R184_1.2 | length 3385.6
  L1 TOP w10.5: v2(2005,3155) 2016,3144 2047.2,3144 R10_1.2@2065.2,3126 ; v2(2820,676) R184_1.2@2820,716
  L6 SIGNAL 3 w6.9: v2(2005,3155) 1985.7,3155 1971.21,3140.51 1926.36,3140.51 1903.86,3118.01 1903.86,3040.9 1869.66,3006.7 1869.66,2504 1775.17,2409.5 1775.17,1446.31 2371.76,849.72 2475.56,849.72 2564.43,760.85 2629.95,760.85 2688.16,702.64 2793.36,702.64 v2(2820,676)
  L8 BOTTOM w7.75: v2(2820,676) 2822.32,678.32 J4.67@2822.32,743.02
AWR_1_SPI_MISO1: J4.66 R12_1.2 R176_1.1 | length 3497.3
  L1 TOP w8: v2(2008,3209) 2031.01,3209 2065.2,3174.81 R12_1.2@2065.2,3166
  L1 TOP w10.5: v2(2775.58,675) 2775.58,647.72 2795.15,628.14 R176_1.1@2827.21,628.14
  L6 SIGNAL 3 w6.9: v2(2008,3209) 1961.35,3162.35 1918.68,3162.35 1889.42,3133.09 1889.42,3048.28 1857.76,3016.62 1857.76,2520.86 1750,2413.11 1750,1438.6 2521.78,666.83 2631.69,666.83 2639.86,675 v2(2775.58,675)
  L8 BOTTOM w7.75: v2(2775.58,675) 2802.64,702.06 J4.66@2802.64,743.02
AWR_1_SPI_MOSI1: J4.69 R183_1.2 U1_1.R8 | length 3493.9
  L1 TOP w4: v2(1990.38,3082.65) 2008.03,3065 2170.9,3065 2184.15,3051.75 2235.25,3051.75 2239.5,3047.5 U1_1.R8@2248.76,3047.5
  L6 SIGNAL 3 w6.9: v2(1990.38,3082.65) 1975.19,3097.84 1942.65,3097.84 1931.27,3086.47 1931.27,3024.65 1896.53,2989.91 1896.53,2473.77 1823.68,2400.92 1823.68,1597.68 2629.29,792.07 2760.43,792.07 2809.37,841 v2(2861.69,841)
  L8 BOTTOM w7.75: v2(2861.69,841) 2861.69,624.66 R183_1.2@2868.21,618.14
AWR_1_TCK: J4.88 U1_1.M13 | length 2734.1
  L1 TOP w10.5: U1_1.M13@2325.53,2919.55 2325.53,2938.23 v2(2326.04,2941.5)
  L6 SIGNAL 3 w6.9: v2(2326.04,2941.5) 2326.04,2718.86 2353,2691.9 2353,2588.99 2360.97,2581.02 2386.28,2581.02 2402.72,2564.59 2402.72,2426.29 2691.69,2137.31 2691.69,1289.83 2773.23,1208.3 2946.77,1208.3 3015.6,1139.47 3015.6,1000.11 v3(3140.71,875)
  L8 BOTTOM w7.75: v3(3140.71,875) 3153.77,861.94 3162.93,861.94 3171.89,852.98 3197.5,852.98 3235.71,814.76 J4.88@3235.71,743.02
AWR_1_TDI: J4.91 U1_1.H13 | length 2795.3
  L1 TOP w10.5: U1_1.H13@2427.89,2919.55 2427.89,2935.79 2431.6,2939.5 v2(2431.6,2943.69)
  L6 SIGNAL 3 w6.9: v2(2431.6,2943.69) 2431.6,2908.18 2414.79,2891.37 2414.79,2773.28 2470.38,2717.69 2492.57,2717.69 2508.84,2701.42 2508.84,2610.74 2454.43,2556.33 2454.43,2453.41 2732.36,2175.48 2732.36,1285.96 2773.63,1244.69 2986.54,1244.69 3095.74,1135.49 3095.74,1072.9 3118.99,1049.65 3118.99,999.3 3191.74,926.55 v3(3191.74,901.78)
  L8 BOTTOM w7.75: v3(3191.74,901.78) 3216.8,901.78 3281.78,836.79 3281.78,800.1 3294.76,787.12 J4.91@3294.76,743.02
AWR_1_TDO: J4.90 R8_1.2 R147.1 TP3_1.1 | length 3401.8
  L1 TOP w10.5: R147.1@3233.9,724 3256.54,701.36 3256.54,686.54 v2(3238,668)
  L6 SIGNAL 3 w6.9: v2(2077,2617) 2555.97,2138.03 2603.85,2138.03 2618.88,2122.99 2618.88,1299.48 2762.31,1156.05 2848.1,1156.05 2930.95,1073.21 2930.95,1022.72 3147.52,806.15 3147.52,784.36 3238,693.88 v2(3238,668)
  L8 BOTTOM w7.75: v2(2077,2617) 2065.5,2628.5 2065.5,2673.69 2027.71,2711.48 2027.71,2812.25 2040.5,2825.05 2115.48,2825.05 2161.12,2870.69 2161.12,2949.66 2178.63,2967.17 2230.52,2967.17 2243.7,2980.35 R8_1.2@2243.7,2998.15 ; TP3_1.1@3245.73,506.43 3245.73,534.08 3238,541.81 v2(3238,668) 3275.08,705.08 J4.90@3275.08,743.02
AWR_1_TMS: J4.89 U1_1.L13 | length 2842.4
  L1 TOP w10.5: U1_1.L13@2351.12,2919.55 2351.12,2944.22 2353.94,2947.04 v2(2353.94,2968.94)
  L6 SIGNAL 3 w6.9: v2(2353.94,2968.94) 2353.94,2745.44 2469.02,2630.36 2469.02,2597.45 2423.84,2552.27 2423.84,2442.16 2711.08,2154.92 2711.08,1288.54 2771.91,1227.71 2961.66,1227.71 3066.82,1122.54 3066.82,990.45 3103.78,953.49 3143.41,953.49 3167.61,929.29 v3(3167.61,882.86)
  L8 BOTTOM w7.75: v3(3167.61,882.86) 3178.17,872.3 3213.58,872.3 3255.39,830.49 J4.89@3255.39,743.02
AWR_1_UART_RX: J4.77 R179_1.1 U1_1.N5 | length 4724
  L1 TOP w4: 2287,3243.55 2287,3144.9 2299.94,3131.96 U1_1.N5@2299.94,3124.27
  L1 TOP w8: v2(2263.49,3322.67) 2287,3299.15 2287,3243.55
  L6 SIGNAL 3 w6.9: v2(2263.49,3322.67) 2263.49,3353.32 2239.48,3377.33 2142.06,3377.33 2107.9,3411.49 1990.67,3411.49 1924.73,3345.55 1924.73,3229.2 1860.85,3165.32 1860.85,3063.81 1829.96,3032.91 1829.96,2544.05 1697.85,2411.94 1697.85,1434.39 2495.79,636.45 2838.87,636.45 2986.34,783.92 3039.73,783.92 3054.85,799.04 v2(3054.85,830.65)
  L8 BOTTOM w7.75: v2(3054.85,830.65) 3053.5,832 3010,832 3001,823 3001,803 3019.17,784.83 3019.17,694.84 3067,647.01 R179_1.1@3067,610.42
AWR_1_UART_TX: J4.78 R11_1.1 R178_1.1 | length 3825.5
  L1 TOP w10.5: v2(3030,809.77) 3043.1,796.67 R178_1.1@3043.1,764
  L6 SIGNAL 3 w6.9: v2(1959.74,3193.74) 1911.83,3193.74 1874.64,3156.55 1874.64,3055.33 1843.95,3024.65 1843.95,2530.52 1723.87,2410.44 1723.87,1439.96 2511.93,651.9 2829.9,651.9 2987.77,809.77 v2(3030,809.77)
  L8 BOTTOM w7.75: v2(1959.74,3193.74) 1999.75,3233.75 2014.57,3233.75 2023.28,3225.04 2060.35,3225.04 R11_1.1@2064.31,3229 ; v2(3030,809.77) 3038.86,800.91 J4.78@3038.86,743.02
AWR_1_WARM_RST: J4.86 R174_1.1 U1_1.N12 | length 3041.5
  L1 TOP w4: v2(2192,2824) 2202.75,2834.75 2202.75,2855.28 2216.48,2869 2231,2869 2243,2881 2253.48,2881 2261.85,2889.37 2261.85,2899.14 2269.17,2906.46 2278.94,2906.46 2287.44,2914.96 2287.44,2932.64 U1_1.N12@2299.94,2945.13
  L6 SIGNAL 3 w6.9: v2(2192,2824) 2192,2803.17 2204.96,2790.2 2204.96,2762.94 2263.8,2704.1 2263.8,2675.75 2238.1,2650.05 2207.48,2650.05 2189.84,2632.41 2189.84,2577.22 2574.81,2192.26 2610.54,2192.26 2668.91,2133.89 2668.91,1292.88 2771.9,1189.89 2934.01,1189.89 2994.74,1129.16 2994.74,990.71 v2(3149.41,836.04)
  L8 BOTTOM w7.75: v2(3149.41,836.04) 3183.91,836.04 3200,819.95 3200,793 3196.34,789.34 3196.34,701.15 3189.35,694.16 3189.35,663.12 3200,652.47 R174_1.1@3200,610.42
AWR_1_XTAL_CLKM: C168.2 R128.1 U1_1.F14 Y1.1 | length 408.2
  L1 TOP w4: U1_1.F14@2479.07,2893.95 2484,2889.02 2484,2884.99 2489.57,2879.43 2489.57,2864.17
  L1 TOP w6: 2489.57,2864.17 2489.57,2850.64 2525.62,2814.59 2525.62,2802.6
  L1 TOP w10.5: 2525.62,2802.6 2525.62,2726.44 2507.02,2707.84 2507.02,2678.68 2470.68,2642.34 R128.1@2470.68,2631.9 C168.2@2518.3,2631.9 2548.69,2631.9 Y1.1@2567.11,2650.32
AWR_1_XTAL_CLKP: R116.2 R121.2 U1_1.E14 | length 420.2
  L1 TOP w4: U1_1.E14@2504.67,2893.95 2517.17,2881.45 2517.17,2859.55
  L1 TOP w6: 2517.17,2859.55 2517.17,2846.9 2548.46,2815.61
  L1 TOP w10.5: 2548.46,2815.61 2548.46,2775.91 2611.66,2712.71 2715.12,2712.71 R116.2@2740.15,2687.68 R121.2@2740.15,2631.9
AWR_1_XTALP_RS: C167.1 R121.1 Y1.3 | length 108.1
  L1 TOP w10.5: Y1.3@2639.95,2565.68 2671.43,2565.68 C167.1@2690.4,2584.65 R121.1@2740.15,2584.65
AWR_1V4_APLL_1: C3_1.1 U1_1.A10 | length 59.5
  L1 TOP w20: U1_1.A10@2607.03,2996.31 C3_1.1@2666.55,2996.31
AWR_1V4_APLL_2: C3_2.1 U1_2.A10 | length 59.5
  L1 TOP w20: U1_2.A10@4925.03,2902.32 C3_2.1@4984.55,2902.32
AWR_1V4_APLL_3: C3_3.1 U1_3.A10 | length 59.5
  L1 TOP w20: U1_3.A10@3922.03,2996.31 C3_3.1@3981.55,2996.31
AWR_1V4_APLL_4: C3_4.1 U1_4.A10 | length 59.5
  L1 TOP w20: U1_4.A10@1437.03,2902.31 C3_4.1@1496.55,2902.31
AWR_1V4_SYNTH_1: C1_1.1 U1_1.A13 | length 167.9
  L1 TOP w12: U1_1.A13@2607.03,2919.54 2609.65,2919.54 2643.63,2885.56 2643.63,2874.72 2655.97,2862.38 2737.61,2862.38 C1_1.1@2742.78,2867.55
AWR_1V4_SYNTH_2: C1_2.1 U1_2.A13 | length 176.2
  L1 TOP w12: U1_2.A13@4925.03,2825.54 4979.41,2771.17 5013.68,2771.17 5024.35,2781.83 C1_2.1@5073.3,2781.83 C1_2.1@5074.3,2781.83
AWR_1V4_SYNTH_3: C1_3.1 U1_3.A13 | length 178.7
  L1 TOP w10: U1_3.A13@3922.03,2919.54 3944.68,2896.89 3962.36,2896.89 3975.53,2883.72 3975.53,2877.84 3987.05,2866.33 4011.38,2866.33 ; C1_3.1@4070.8,2875.83 C1_3.1@4071.3,2875.83
  L1 TOP w12: 4011.38,2866.33 4020.89,2875.83 C1_3.1@4070.8,2875.83
AWR_1V4_SYNTH_4: C1_4.1 U1_4.A13 | length 120.8
  L1 TOP w12: U1_4.A13@1437.03,2825.54 1439.65,2825.54 1473.63,2791.56 1473.63,2780.72 1485.97,2768.38 C1_4.1@1527.76,2768.38
AWR_2_1V0_RF1_FILT: C79.1 C80.1 C83.1 C136_2.1 C137_2.1 C138_2.1 C139_2.1 L20.2 U1_2.G5 U1_2.H5 U1_2.J5 | length 173.1
  L1 TOP w15: v2(4722.09,3055.57) 4720.3,3053.78 U1_2.J5@4720.3,3030.27 U1_2.G5@4771.48,3030.27 4771.48,3046.51 4769.34,3048.65 v2(4769.34,3053.83)
  L8 BOTTOM w25: v2(4722.09,3055.57) 4767.6,3055.57 v2(4769.34,3053.83) 4772.38,3050.79 C136_2.1@4772.38,3031.63
  other v3: 5809.67,387.13 5829.35,387.13 5849.04,387.13 5809.67,406.82 5829.35,406.82 5849.04,406.82 5809.67,426.5 5829.35,426.5 5849.04,426.5 5535.39,2018.67 5555.07,2018.67 5574.76,2018.67 5535.39,2038.36 5555.07,2038.36 5574.76,2038.36 5535.39,2058.04 5555.07,2058.04 5574.76,2058.04 4737.01,3498.22 4756.69,3498.22 4776.38,3498.22 4737.01,3517.91 4756.69,3517.91 4776.38,3517.91
AWR_2_1V0_RF2_FILT: C85.1 C140_2.1 C141_2.1 C166.1 C201.1 L21.2 R188_2.2 U1_2.C2 U1_2.D2 | length 74.2
  L1 TOP w12: v2(4842,3061) 4842,3066 4848.25,3072.25 v2(4848.25,3087.15) 4848.25,3107.04 U1_2.C2@4873.85,3107.04
  other v2: 5122.68,3102.3 5150.17,3102.3
  other v3: 5778.93,530.15 5798.61,530.15 5818.3,530.15 5778.93,549.83 5798.61,549.83 5818.3,549.83 5778.93,569.52 5798.61,569.52 5818.3,569.52 5248.79,2894.28 5268.48,2894.28 5248.79,2913.96 5268.48,2913.96 5248.79,2933.65 5268.48,2933.65 5248.79,2953.33 5268.48,2953.33
AWR_2_1V2_FILT: C71.1 C72.1 C73.1 C142_2.1 C143_2.1 C144_2.1 C145_2.1 C146_2.1 C147_2.1 L17.2 U1_2.F13 U1_2.N11 U1_2.P14 U1_2.P15 U1_2.R6 U1_2.R14 | length 700.3
  L1 TOP w4: 4579.5,2763.69 4579.5,2779.5 4592.35,2792.35 U1_2.P14@4592.35,2799.95
  L1 TOP w8: 4571.43,2752.28 4579.5,2760.36 4579.5,2763.69 ; 4592.35,2751.01 U1_2.P15@4592.35,2774.36
  L1 TOP w10: v2(4512,3026) 4514,3026 4535.32,3004.68 U1_2.R6@4566.76,3004.68 ; 4520,2783 4536,2799 4548,2799 4548.96,2799.96 U1_2.R14@4566.76,2799.95 ; 4548.75,2729.6 4571.43,2752.28 ; 4582.25,2734.86 4592.35,2744.95 4592.35,2751.01
  L1 TOP w12: v2(4796.51,2850.72) 4796.51,2843.18 4797.07,2842.62 U1_2.F13@4797.07,2825.55
  L1 TOP w15: C143_2.1@4459.99,3033.71 4468.7,3025 4511,3025 v2(4512,3026) ; v2(4468,2740) 4478,2750 4493,2750 4501.58,2758.58 C146_2.1@4501.58,2776 4513,2776 4520,2783 ; v2(4482,2705) 4495.42,2691.58 C147_2.1@4521,2691.58 ; C147_2.1@4521,2693 4538,2710 4538,2718.86 4548.75,2729.6 ; 4582.25,2734.86 4562,2714.6 C142_2.1@4562,2691.58 4569.28,2684.3 v2(4596,2684.3) ; U1_2.N11@4617.94,2876.73 4623.02,2876.73 v2(4635.19,2888.9)
  L8 BOTTOM w12: C144_2.1@4596.3,2888.9 v2(4635.19,2888.9)
  L8 BOTTOM w15: C145_2.1@4796.51,2803.84 v2(4796.51,2850.72)
  other v3: 4760.3,1266.47 4779.98,1266.47 4799.67,1266.47 4760.3,1286.15 4779.98,1286.15 4799.67,1286.15 4760.3,1305.84 4779.98,1305.84 4799.67,1305.84
AWR_2_1V8_FILT: C75.1 C76.1 C77.1 C128_2.1 C129_2.1 C130_2.1 C131_2.1 C132_2.1 C133_2.1 C134_2.1 C135_2.1 L18.2 U1_2.B11 U1_2.B12 U1_2.D13 U1_2.F5 U1_2.K5 U1_2.K13 | length 719.1
  L1 TOP w8: v2(4843.79,2865.6) v2@4845.02,2866.83
  L1 TOP w12: U1_2.B12@4899.44,2851.13 4908.67,2851.13
  L1 TOP w15: v2@4678.39,3055.45 4694.71,3039.13 U1_2.K5@4694.71,3030.27 ; U1_2.K13@4694.71,2825.55 4694.71,2841.82 v2(4700.03,2847.14) ; U1_2.F5@4797.07,3030.27 4797.07,3036.78 v2(4807.99,3047.7) ; v2(4843.79,2865.6) 4843.79,2859.7 4848.25,2855.24 U1_2.D13@4848.25,2825.55 ; U1_2.B11@4899.44,2876.73 4943.64,2876.73 4972.35,2848.02 C131_2.1@4984.84,2848.02 v3(4984.84,2868.39) ; 4908.67,2851.13 4934.49,2851.13 4962.9,2822.72 4989.18,2822.72 C132_2.1@4999.84,2812.06 v3(4999.84,2791.69)
  L8 BOTTOM w12: v2(4843.79,2865.6) 4846.19,2868 C134_2.1@4916.09,2868
  L8 BOTTOM w15: v2(4678.39,3055.45) 4706.15,3027.69 C129_2.1@4707.89,3027.69 ; C135_2.1@4699.3,2812 v2@4699.3,2846.41 ; v2(4807.99,3047.7) 4803.23,3052.46 C128_2.1@4803.23,3125.03 4803.23,3169.13 C130_2.1@4817.9,3183.8
  L8 BOTTOM w20: v3(4999.84,2791.69) C133_2.1@5050.19,2791.69
AWR_2_BSS_LOGGER: J4.103 R14_2.1 | length 3131.9
  L1 TOP w10.5: v2(4324,3159) 4336.84,3159 4346.84,3169 4376.09,3169 R14_2.1@4388.09,3157
  L6 SIGNAL 3 w6.9: v2(3533,688) 3469.33,751.67 3399.76,751.67 3339.79,811.63 3339.79,956.28 3368.57,985.06 3368.57,1813.48 4002.57,2447.49 4002.57,2645.1 4122.53,2765.06 4122.53,2909.53 4306.11,3093.11 4306.11,3116.58 4326.36,3136.83 v2@4326.36,3161.36
  L8 BOTTOM w7.75: J4.103@3530.98,743.02 3530.98,690.02 v2(3533,688)
AWR_2_CSI2_CLK_N: J4.50 U1_2.J14 | length 2638.5
  L1 TOP w4: U1_2.J14@4720.3,2799.95 4732.89,2787.37 4732.89,2768.68
  L1 TOP w6.5: 4732.89,2768.68 4732.89,2552.11 v2(4743,2542)
  L8 BOTTOM w5.25: J4.50@3668.78,979.24 3668.78,1019.05 3664,1023.83 3664,1069.26 3655.29,1077.97 3655.29,1121.25 4048.78,1514.73 4164.46,1514.73 4177.11,1527.39 4177.11,1541.03 4183.67,1547.59 4202.22,1547.59 4209.92,1539.89 4209.92,1526.46 4221.7,1514.68 4263.03,1514.68 ; 4263.37,1514.76 4276.08,1527.47 4276.08,1541.11 4282.64,1547.67 4302.05,1547.67 4308.89,1540.83 4308.89,1526.63 4320.78,1514.73 4445.8,1514.73 4772.26,1841.19 4772.26,2456.72 4732,2496.98 4732,2531 v2(4743,2542)
AWR_2_CSI2_CLK_P: J4.49 U1_2.J15 | length 2609.1
  L1 TOP w6.5: v2(4708,2541) 4720.89,2553.89 4720.89,2773.78 U1_2.J15@4720.3,2774.36
  L8 BOTTOM w5.25: J4.49@3649.09,979.24 3649.09,1019.37 3652,1022.28 3652,1064.29 3643.29,1073 3643.29,1126.22 4043.81,1526.73 4159.49,1526.73 4165.11,1532.36 4165.11,1546 4178.7,1559.59 4207.19,1559.59 4221.92,1544.86 4221.92,1531.43 4226.67,1526.68 4258.32,1526.68 4264.08,1532.44 4264.08,1546.09 4277.67,1559.67 4307.02,1559.67 4320.89,1545.8 4320.89,1531.6 4325.75,1526.73 4440.83,1526.73 4760.26,1846.16 4760.26,2451.75 4720,2492.01 4720,2529 v2(4708,2541)
AWR_2_CSI2_TX0_N: J4.59 U1_2.G14 | length 2631.7
  L1 TOP w4: U1_2.G14@4771.48,2799.95 4771.48,2792.52 4784.58,2779.42 4784.58,2760.51
  L1 TOP w6.5: 4784.58,2760.51 4784.58,2610.42 4794,2601 4801.2,2601 v2(4814,2614.8)
  L8 BOTTOM w5.25: J4.59@3845.94,979.24 3845.94,1020.37 3841.9,1024.41 3841.9,1096.24 4086.26,1340.61 4505.65,1340.61 4917.46,1752.42 4917.46,2555.99 4873.26,2600.19 4828.61,2600.19 v2(4814,2614.8)
AWR_2_CSI2_TX0_P: J4.58 U1_2.G15 | length 2601
  L1 TOP w6.5: U1_2.G15@4771.48,2774.36 4772.07,2773.78 4772.07,2761.02 4772.58,2760.51 4772.58,2605.44 4789.02,2589 4799,2589 v2(4814,2574)
  L8 BOTTOM w5.25: J4.58@3826.26,979.24 3826.26,1020.21 3829.9,1023.85 3829.9,1101.21 4081.29,1352.61 4500.68,1352.61 4905.46,1757.39 4905.46,2551.01 4868.29,2588.19 4828.19,2588.19 v2(4814,2574)
AWR_2_CSI2_TX1_N: J4.56 U1_2.H14 | length 2631
  L1 TOP w4: U1_2.H14@4745.89,2799.95 4758.48,2787.37 4758.48,2760
  L1 TOP w6.5: 4758.48,2760 4758.48,2598.5 4803,2553.98 4803,2542.4 v2(4815.4,2530)
  L8 BOTTOM w5.25: J4.56@3786.89,979.24 3786.89,1020.09 3782.8,1024.18 3782.8,1141.04 4059.79,1418.03 4225.71,1418.03 4238.01,1430.33 4238.01,1448.14 4243.74,1453.87 4264.3,1453.87 4270.82,1447.34 4270.82,1430.95 4284.25,1417.53 4323.22,1417.53 4336.98,1431.29 4336.98,1447.13 4343.24,1453.39 4363.52,1453.39 4369.79,1447.12 4369.79,1430.94 4383.1,1417.63 4461.62,1417.63 4824.71,1780.72 4824.71,2474.27 4803,2495.98 4803,2517.6 v2(4815.4,2530)
AWR_2_CSI2_TX1_P: J4.55 U1_2.H15 | length 2599.9
  L1 TOP w6.5: U1_2.H15@4745.89,2774.36 4746.48,2773.78 4746.48,2593.52 4791,2549 4791,2542 v2(4779,2530)
  L8 BOTTOM w5.25: J4.55@3767.2,979.24 3767.2,1019.9 3770.8,1023.5 3770.8,1146.01 4054.82,1430.03 4220.74,1430.03 4226.01,1435.3 4226.01,1453.11 4238.77,1465.87 4269.27,1465.87 4282.82,1452.31 4282.82,1435.92 4289.22,1429.53 4318.25,1429.53 4324.98,1436.26 4324.98,1452.1 4338.27,1465.39 4368.5,1465.39 4381.79,1452.09 4381.79,1435.91 4388.07,1429.63 4456.65,1429.63 4812.71,1785.69 4812.71,2469.3 4791,2491.01 4791,2518 v2(4779,2530)
AWR_2_CSI2_TX2_N: J4.46 U1_2.K14 | length 2631.7
  L1 TOP w4: U1_2.K14@4694.71,2799.95 4707.3,2787.37 4707.3,2764
  L1 TOP w6.5: v2(4691.96,2464) 4678,2477.96 4678,2549 4707.3,2578.3 4707.3,2764
  L8 BOTTOM w5.25: J4.46@3590.04,979.24 3590.04,1018.46 3585.7,1022.8 3585.7,1152.93 4032.94,1600.17 4122.87,1600.17 4135.51,1612.82 4135.51,1624.8 4143.74,1633.02 4160.39,1633.02 4168.32,1625.09 4168.32,1611.89 4180.11,1600.11 4221.44,1600.11 ; 4221.77,1600.19 4234.48,1612.9 4234.48,1623.93 4241.96,1631.4 4258.95,1631.4 4267.3,1623.05 4267.3,1612.06 4279.18,1600.17 4422.19,1600.17 4715.33,1893.31 4715.33,2426.66 4691.96,2450.03 v2(4691.96,2464)
AWR_2_CSI2_TX2_P: J4.45 U1_2.K15 | length 2612.9
  L1 TOP w6.5: v2(4655.56,2464) 4666,2474.44 4666,2553.98 4695.3,2583.28 4695.3,2773.78 U1_2.K15@4694.71,2774.36
  L8 BOTTOM w5.25: J4.45@3570.35,979.24 3570.35,1018.25 3573.7,1021.6 3573.7,1157.9 4027.97,1612.17 4117.9,1612.17 4123.51,1617.79 4123.51,1629.77 4138.77,1645.02 4165.37,1645.02 4180.32,1630.06 4180.32,1616.86 4185.08,1612.11 4216.72,1612.11 4222.48,1617.87 4222.48,1628.9 4236.99,1643.4 4263.92,1643.4 4279.3,1628.03 4279.3,1617.03 4284.15,1612.17 4417.22,1612.17 4703.33,1898.29 4703.33,2421.69 4676.02,2449 4670.56,2449 v2(4655.56,2464)
AWR_2_CSI2_TX3_N: J4.42 U1_2.L14 | length 2631
  L1 TOP w4: U1_2.L14@4669.12,2799.95 4681.71,2787.37 4681.71,2763.9
  L1 TOP w6.5: v2(4645.4,2512) 4634.3,2523.1 4634.3,2549.3 4681.71,2596.71 4681.71,2763.9
  L8 BOTTOM w5.25: J4.42@3511.3,979.24 3511.3,1018.83 3506.8,1023.33 3506.8,1169.07 4021.78,1684.05 4142.6,1684.05 4155.31,1696.76 4155.31,1710.41 4161.86,1716.96 4180.42,1716.96 4188.12,1709.27 4188.12,1695.83 4199.9,1684.05 4241.23,1684.05 ; 4241.57,1684.13 4254.28,1696.84 4254.28,1710.49 4260.83,1717.05 4279.39,1717.05 4287.09,1709.35 4287.09,1696 4299.04,1684.05 4398.76,1684.05 4632,1917.29 4632,2499.6 4644.4,2512 v2(4645.4,2512)
AWR_2_CSI2_TX3_P: J4.41 U1_2.L15 | length 2599.6
  L1 TOP w6.5: v2(4609,2512) 4622.3,2525.3 4622.3,2554.28 4669.71,2601.69 4669.71,2773.78 U1_2.L15@4669.12,2774.36
  L8 BOTTOM w5.25: J4.41@3491.61,979.24 3491.61,1018.86 3494.8,1022.05 3494.8,1174.04 4016.81,1696.05 4137.62,1696.05 4143.31,1701.73 4143.31,1715.38 4156.89,1728.96 4185.39,1728.96 4200.12,1714.24 4200.12,1700.8 4204.87,1696.05 4236.51,1696.05 4242.28,1701.81 4242.28,1715.46 4255.86,1729.05 4284.36,1729.05 4299.09,1714.32 4299.09,1700.97 4304.01,1696.05 4393.79,1696.05 4620,1922.26 4620,2500 4609,2511 v2(4609,2512)
AWR_2_DIG_SYNCIN: R133.2 R185_2.2 U1_2.N10 | length 3936
  L1 TOP w10.5: U1_2.N10@4617.94,2902.32 4628.04,2912.42 4642.59,2912.42 4654.16,2924 v2(4668,2924)
  L8 BOTTOM w7.75: R133.2@2155.48,3598.46 2500.19,3598.46 2703,3395.65 2703,3314.92 2716.94,3300.98 2716.94,3110.25 3381.23,2445.95 3960.85,2445.95 4164.02,2649.12 4164.02,2924.56 4309.95,3070.49 4342.75,3070.49 4384.4,3112.14 4384.4,3136.89 4403.69,3156.18 4473.32,3156.18 4483.8,3145.7 4483.8,3086.14 4442.28,3044.62 4442.28,2991.61 4452.84,2981.05 R185_2.2@4473.9,2981.05 4607.81,2981.05 4621.86,2967 4646.99,2967 4668,2945.99 v2(4668,2924)
AWR_2_DIG_SYNCIN_RS: R133.1 U8.14 | length 253.9
  L3 SIGNAL 1 w5.1: v2(2083.93,3753) 2191.23,3645.7 v2(2195.79,3645.7)
  L8 BOTTOM w7.75: v2(2083.93,3753) U8.14@2141.18,3753 ; R133.1@2155.48,3645.7 v2(2195.79,3645.7)
AWR_2_DIG_SYNCOUT: R1_2.1 R152.1 TP1_2.1 | length 3044.3
  L1 TOP w10.5: R1_2.1@4412.1,2890.99 4412.1,2867.89 v2(4418,2861.99)
  L6 SIGNAL 3 w6.9: v2(3744,532.56) 3732.91,521.46 3732.91,505.34 3744.98,493.27 3788.53,493.27 3803.17,507.91 3803.17,539.62 3765.49,577.29 3742.43,577.29 3733.1,586.62 3733.1,674.16 3644.21,763.05 3644.21,861.7 3667.25,884.74 3667.25,976.25 3709.98,1018.98 3709.98,1770.86 4259.38,2320.27 4259.38,2586.9 4363.53,2691.04 4406.64,2691.04 4415.06,2699.47 4415.06,2734.22 4427.49,2746.65 4440.17,2746.65 4451.46,2757.94 4451.46,2806.48 4418,2839.94 v2(4418,2861.99)
  L8 BOTTOM w7.75: R152.1@3744,563.18 v2(3744,532.56) 3744,516.18 3754,506.18 TP1_2.1@3754,481.94
AWR_2_FMCW_CLKOUT: R79.1 U1_2.B15 | length 132.7
  L1 TOP w10.5: U1_2.B15@4899.44,2774.36 4899.44,2757.56 4942.61,2714.39 v2(4959.41,2714.39)
  L8 BOTTOM w7.75: v2(4959.41,2714.39) R79.1@4959.41,2752.44
AWR_2_FMCW_SYNCOUT: R82.1 U1_2.D1 | length 120.9
  L1 TOP w8.4: U1_2.D1@4848.26,3132.63 v2(4848.26,3229.68)
  L8 BOTTOM w7.75: v2(4848.26,3229.68) R82.1@4848.26,3253.5
AWR_2_GPIO_0: J4.105 R16_2.2 U1_2.N4 | length 3163.3
  L1 TOP w10.5: U1_2.N4@4617.94,3055.86 4638.97,3055.86 v2(4643.09,3051.75)
  L6 SIGNAL 3 w6.9: v2(3566.68,804.67) 3555.65,815.7 3555.65,961.67 3590.83,996.86 3590.83,1801.03 4166.06,2376.27 4166.06,2606.38 4249.81,2690.14 4249.81,2771.27 4295.12,2816.58 4356.42,2816.58 4379.78,2839.94 4379.78,2962.49 4394.32,2977.02 4394.32,3063.38 4427.51,3096.57 4554.39,3096.57 4599.21,3051.75 v2(4643.09,3051.75)
  L8 BOTTOM w7.75: R16_2.2@3539,610.42 3539,658.79 3558.6,678.39 3558.6,693.37 3570.35,705.13 J4.105@3570.35,743.02 3570.35,801 v2(3566.68,804.67)
AWR_2_GPIO_1: J4.106 R17_2.2 U1_2.N7 | length 3146.2
  L1 TOP w10.5: U1_2.N7@4617.94,2979.09 4620.38,2979.09 v2(4638.69,2997.4)
  L6 SIGNAL 3 w6.9: v2(3589.93,850.67) 3567.55,873.05 3567.55,946.09 3608.52,987.07 3608.52,1785.11 4185.77,2362.36 4185.77,2605.64 4266.34,2686.21 4266.34,2761.98 4305.01,2800.65 4359.66,2800.65 4393.49,2834.47 4393.49,2953.95 4409.58,2970.04 4409.58,3058.25 4435.5,3084.17 4533.53,3084.17 4620.31,2997.4 v2(4638.69,2997.4)
  L8 BOTTOM w7.75: R17_2.2@3580,610.42 3580,692.09 3590.04,702.12 J4.106@3590.04,743.02 3590.04,823.96 3589.93,824.07 v2(3589.93,850.67)
AWR_2_GPIO_2: J4.107 R18_2.2 U1_2.N13 | length 2823.6
  L1 TOP w4: 4605.44,2769 4605.44,2806.5 4617.94,2819 U1_2.N13@4617.94,2825.55
  L1 TOP w6: v2(4597,2712) 4605.44,2720.44 4605.44,2769
  L6 SIGNAL 3 w6.9: v2(3732.19,867.47) 3752.66,847 3818.66,847 3889.34,917.68 3889.34,1474.69 4303.07,1888.42 4303.07,1971.5 4479.66,2148.09 4479.66,2523.58 4513.88,2557.79 4556.22,2557.79 4582.14,2583.71 4582.14,2617.62 4566.62,2633.14 4566.62,2699.53 4579.09,2712 v2(4597,2712)
  L8 BOTTOM w7.75: R18_2.2@3621,610.42 3621,644.04 3597.71,667.34 3597.71,688.23 3609.72,700.24 J4.107@3609.72,743.02 3609.72,827.72 3649.47,867.47 v2(3732.19,867.47)
AWR_2_LVDS_FRCLK_N: J4.38 U1_2.M14 | length 2632
  L1 TOP w4: U1_2.M14@4643.53,2799.95 4656.12,2787.37 4656.12,2759
  L1 TOP w6.5: v2(4579.62,2532) 4566,2545.62 4566,2559 4593,2586 4619.98,2586 4656.12,2622.14 4656.12,2759
  L8 BOTTOM w5.25: J4.38@3432.56,979.24 3432.56,1019.18 3428.95,1022.79 3428.95,1167.45 4023.56,1762.06 4142.63,1762.06 4155.4,1774.83 4155.4,1795.95 4163.52,1804.07 4203.9,1804.07 4213.98,1793.98 4213.98,1775.41 4227.25,1762.14 4384.22,1762.14 4424.51,1802.43 4565,1942.92 4565,2428.26 4565,2517.38 v2(4579.62,2532)
AWR_2_LVDS_FRCLK_P: J4.37 U1_2.M15 | length 2601.2
  L1 TOP w6.5: v2(4540,2532) 4554,2546 4554,2563.98 4588.02,2598 4615,2598 4644.12,2627.12 4644.12,2773.78 U1_2.M15@4643.53,2774.36
  L8 BOTTOM w5.25: J4.37@3412.87,979.24 3412.87,1019.36 3416.95,1023.44 3416.95,1172.42 4018.59,1774.06 4137.66,1774.06 4143.4,1779.8 4143.4,1800.92 4158.54,1816.07 4208.87,1816.07 4225.98,1798.95 4225.98,1780.38 4232.22,1774.14 4379.25,1774.14 4436.32,1831.21 4553,1947.89 4553,2423.28 4553,2519 v2(4540,2532)
AWR_2_LVDS_VALID_N: J4.34 U1_2.N14 | length 2631.3
  L1 TOP w4: U1_2.N14@4617.94,2799.95 4630.53,2787.37 4630.53,2767.89
  L1 TOP w6.5: v2(4525.7,2582.7) 4514,2594.4 4514,2608.02 4525.98,2620 4608.98,2620 4630.53,2641.55 4630.53,2767.89
  L8 BOTTOM w5.25: J4.34@3353.82,979.24 3353.82,1019.51 3350,1023.33 3350,1173.61 4023.18,1846.8 4390.26,1846.8 4514,1970.54 4514,2571 v2(4525.7,2582.7)
AWR_2_LVDS_VALID_P: J4.33 U1_2.N15 | length 2601.6
  L1 TOP w6.5: v2(4489.3,2582.7) 4502,2595.4 4502,2613 4521,2632 4604,2632 4618.53,2646.53 4618.53,2773.78 U1_2.N15@4617.94,2774.36
  L8 BOTTOM w5.25: J4.33@3334.13,979.24 3334.13,1019.52 3338,1023.39 3338,1178.59 4018.21,1858.8 4385.28,1858.8 4502,1975.51 4502,2570 v2(4489.3,2582.7)
AWR_2_MCU_CLKOUT: R5_2.1
AWR_2_MSS_LOGGER: J4.102 R15_2.1 | length 3005.3
  L1 TOP w10.5: v2(4359,3144) 4386,3117 R15_2.1@4388.1,3117
  L6 SIGNAL 3 w6.9: v2(3511,807) 3488.26,784.26 3410.79,784.26 3387.55,807.5 3387.55,839.33 3363.96,862.92 3363.96,884.16 3396.24,916.45 3396.24,954.67 3432.01,990.43 3432.01,1819.83 4040.05,2427.87 4040.05,2629.92 4153.54,2743.41 4153.54,2886.18 4359,3091.64 v2(4359,3144)
  L8 BOTTOM w7.75: v2(3511,807) 3511.3,806.7 J4.102@3511.3,743.02
AWR_2_NERROR_IN: R177_2.1 U1_2.P7 | length 194.9
  L1 TOP w4: R177_2.1@4414.4,2995 4427.74,2995 4441.74,2981 4501,2981 4515.41,2966.59 4579.85,2966.59 U1_2.P7@4592.35,2979.09
AWR_2_NERROR_OUT: R9_2.1 R156.1 | length 38.9
  L8 BOTTOM w7.75: R9_2.1@4560.6,3020.95 R156.1@4560.6,3059.85
AWR_2_NRST: R199.2 R209.2 U1_2.P12 | length 4812.5
  L1 TOP w4: 4558.6,2838.64 4579.85,2838.64 U1_2.P12@4592.35,2851.13
  L1 TOP w6: v2(4440,2723) 4403.15,2759.85 4403.15,2805.89 4418.19,2820.93 4422.09,2820.93 4445.7,2844.53 4471.38,2844.53 4490.85,2864 4512,2864 4537.36,2838.64 4558.6,2838.64
  L1 TOP w10.5: v2(3669,840) 3636.87,807.87 3636.87,739.62 3814.47,562.02 3987.2,562.02 4021.52,527.7 4021.52,399.21 4306.81,113.92 4421.85,113.92 4531.11,223.18 4531.11,578.81 4586.69,634.4 R209.2@4670.68,634.4 R199.2@4670.68,691.84
  L6 SIGNAL 3 w6.9: v2(3669,840) 3695.63,866.63 3695.63,928.66 3762.65,995.67 3762.65,1755.12 4082.33,2074.81 4256.37,2074.81 4332.27,2150.71 4332.27,2335.26 4312.91,2354.62 4312.91,2584.79 4377.45,2649.33 4416.1,2649.33 4442.26,2623.18 4507.4,2623.18 4519.76,2635.54 4519.76,2658.36 4505.02,2673.1 4466.51,2673.1 4440,2699.61 v2(4440,2723)
AWR_2_NRST_HOST: J4.109 R190.1 | length 1487.6
  L1 TOP w10.5: v2(3649.09,656.84) 3725.66,580.26 3756.08,580.26 3905.7,430.64 3951.43,430.64 4300.97,81.1 4598.08,81.1 4693.44,176.46 R190.1@4693.44,255.59
  L8 BOTTOM w7.75: v2(3649.09,656.84) J4.109@3649.09,743.02
AWR_2_NRST_HOST_GS: R88.1 R190.2 U11.2 | length 116.2
  L1 TOP w10.5: U11.2@4688.44,369.58 4688.44,307.83 R190.2@4693.44,302.83 R88.1@4740.84,302.83
AWR_2_NRST_LED: Q3.1 R199.1 | length 56.1
  L1 TOP w10.5: R199.1@4623.43,691.84 Q3.1@4623.43,747.96
AWR_2_NRST_LED_PW: DS5.1 R197.1 | length 65
  L1 TOP w10.5: DS5.1@4717.92,906.78 R197.1@4717.92,971.8
AWR_2_NRST_RS: C206.1 R207.1 R209.1 U11.4 | length 156.5
  L1 TOP w10.5: R207.1@4717.92,587.15 R209.1@4717.92,634.4 ; U11.4@4725.84,477.85 C206.1@4725.84,535.63 R207.1@4725.84,587.15
AWR_2_OSC_CLKOUT: J2.3 R2_2.1 | length 4854.2
  L1 TOP w10.5: v2(5022.77,2685.2) R2_2.1@5022.77,2708.4
  L6 SIGNAL 3 w6.9: v2(1978.45,369.78) 1992.04,383.38 1992.04,423.84 2025.29,457.08 2223.66,457.08 2309.92,370.83 3751.97,370.82 3882.67,501.52 3882.67,767.69 4109.39,994.41 4109.4,1470.77 5041.84,2403.21 5041.84,2642.55 5041.84,2666.13 v2(5022.77,2685.2)
  L8 BOTTOM w7.75: J2.3@1978.45,264.5 v2(1978.45,369.78)
AWR_2_PMIC_CLKOUT: R4_2.1 R153.1 TP2_2.1 | length 2803.7
  L1 TOP w10.5: v2(4423,2800) 4434.09,2800 R4_2.1@4449,2814.91
  L6 SIGNAL 3 w6.9: v2(3703,532.56) 3703,661.69 3614.11,750.58 3614.11,874.17 3637.15,897.21 3637.15,989.15 3664.27,1016.27 3664.27,1789.95 4216.79,2342.47 4216.79,2602.57 4290.91,2676.69 4290.91,2747.85 4315.57,2772.51 4367.33,2772.51 4387.26,2792.44 4415.44,2792.44 v2(4423,2800)
  L8 BOTTOM w7.75: TP2_2.1@3693,481.94 3693,506.17 3703,516.17 v2(3703,532.56) R153.1@3703,563.18
AWR_2_SCL: R100.2 R180_2.1 U1_2.P4 | length 262.5
  L1 TOP w4: 4552.66,3075.16 4559.07,3068.75 4579.46,3068.75 U1_2.P4@4592.35,3055.86
  L1 TOP w6: 4493,3153 4493,3134.82 4552.66,3075.16
  L1 TOP w8: R180_2.1@4425.91,3197 4443.69,3179.22 v2(4453.92,3179.22) 4466.78,3179.22 4493,3153
  L8 BOTTOM w7.75: R100.2@4426.98,3179.22 v2(4453.92,3179.22)
AWR_2_SDA: R13_2.1 R101.2 R181_2.1 | length 167.3
  L1 TOP w8: R101.2@4291.06,3238 4297.67,3238 4302.67,3243 v2(4326,3243) 4382.1,3243 R13_2.1@4388.1,3237
  L8 BOTTOM w7.75: v2(4326,3243) 4339.41,3256.41 R181_2.1@4386.19,3256.41
AWR_2_SOP0_TDO: J4.114 R151.2 | length 119.5
  L1 TOP w10.5: v2(3773.1,680) R151.2@3773.1,718.21
  L8 BOTTOM w7.75: J4.114@3747.52,743.02 3747.52,692.48 3760,680 v2(3773.1,680)
AWR_2_SOP1_SYNCOUT: J4.113 R152.2 | length 139.3
  L8 BOTTOM w7.75: J4.113@3727.83,743.02 3727.83,665.15 3744,648.98 R152.2@3744,610.42
AWR_2_SOP2_PMICCLKOUT: J4.112 R153.2 | length 134.7
  L8 BOTTOM w7.75: R153.2@3703,610.42 3708.15,615.57 J4.112@3708.15,743.02
AWR_2_SPI_CLK1: J4.98 R182_2.2 U1_2.R9 | length 2968.4
  L1 TOP w4: v2(4341,2895) 4351,2905 4351,2920 4382,2951 4486,2951 4501,2936 4547,2936 4555.09,2927.91 U1_2.R9@4566.76,2927.91
  L6 SIGNAL 3 w6.9: v2(3435,862) 3449.67,876.67 3449.67,941.14 3510.22,1001.69 3510.22,1811.27 4102.22,2403.28 4102.22,2613 4201.52,2712.3 4201.52,2811.13 4285.4,2895 v2(4341,2895)
  L8 BOTTOM w7.75: R182_2.2@3416,610.42 3416,650.64 3432.56,667.2 3432.56,796.56 3435.93,799.93 3435.93,861.07 v2(3435,862)
AWR_2_SPI_CS1: J4.96 R175_2.1 U1_2.R7 | length 3218.5
  L1 TOP w6: v2(4344,3039) 4346.06,3039 4369.37,3015.69 4425.94,3015.69 4448.05,2993.59 4508.22,2993.59 4522.72,2979.09 U1_2.R7@4566.76,2979.09
  L1 TOP w10.5: v2(3387,873.4) 3387,749.21 3416,720.21 3416,667.47 R175_2.1@3457,626.47
  L6 SIGNAL 3 w6.9: v2(3387,873.4) 3412.85,899.25 3412.85,952.11 3472.7,1011.96 3472.7,1832.75 4061.42,2421.47 4061.42,2624.02 4169.17,2731.76 4169.17,2864.17 v2(4344,3039)
  L8 BOTTOM w7.75: v2(3387,873.4) 3387,807 3393.19,800.81 J4.96@3393.19,743.02
AWR_2_SPI_HOST_INTR1: J4.94 R10_2.2 R184_2.2 | length 3003.1
  L1 TOP w10.5: v2(4335,3103) 4338,3103 4351,3090 4351,3069.11 R10_2.2@4383.11,3037
  L6 SIGNAL 3 w6.9: v2(3362,832) 3362,848.05 3352.06,857.99 3352.06,939.89 3414.44,1002.27 3414.44,1828.83 4021.05,2435.44 4021.05,2636.83 4138.39,2754.17 4138.39,2906.39 v2(4335,3103)
  L8 BOTTOM w7.75: R184_2.2@3334,610.42 3334,672.91 3353.82,692.73 3353.82,792.82 3362,801 v2(3362,832)
AWR_2_SPI_MISO1: J4.93 R12_2.2 R176_2.1 | length 3108.8
  L1 TOP w10.5: v2(4287,3139.12) 4298.34,3127.78 4345.75,3127.78 4366,3107.53 4366,3101 4383.09,3083.91 R12_2.2@4383.09,3077
  L6 SIGNAL 3 w6.9: v2(3316.93,836.19) 3327.89,847.15 3327.89,968.03 3351.56,991.7 3351.56,1823.39 3985.68,2457.52 3985.68,2703.7 4057.42,2775.43 4091.21,2775.43 4106.66,2790.88 4106.66,2913.49 4287,3093.83 v2(4287,3139.12)
  L8 BOTTOM w7.75: R176_2.1@3293,610.42 3293,657.87 3334.13,699 J4.93@3334.13,743.02 3334.13,786.25 3339.74,791.86 3339.74,813.39 v2(3316.93,836.19)
AWR_2_SPI_MOSI1: J4.97 R183_2.2 U1_2.R8 | length 3005.3
  L1 TOP w4: v2(4337,2977) 4343,2971 4496,2971 4511,2956 4564.26,2956 U1_2.R8@4566.76,2953.5
  L6 SIGNAL 3 w6.9: v2(3412,822) 3412,872.75 3431.19,891.94 3431.19,941.87 3491.89,1002.57 3491.89,1824.28 4081.57,2413.96 4081.57,2618.71 4185.73,2722.87 4185.73,2825.73 v2(4337,2977)
  L8 BOTTOM w7.75: R183_2.2@3375,610.42 3375,640.74 3412.87,678.61 3412.87,821.13 v2(3412,822)
AWR_2_TCK: J4.116 U1_2.M13 | length 2669.4
  L1 TOP w10.5: U1_2.M13@4643.53,2825.55 4643.53,2844.23 4644.04,2844.74 v2(4644.04,2847.5)
  L6 SIGNAL 3 w6.9: v2(3726,823) 3783.74,823 3791.16,830.42 3821.98,830.42 3904.24,912.68 3904.24,1438.02 4411.48,1945.27 4411.48,1997.06 4548.37,2133.95 4548.37,2401.02 4635.89,2488.53 4662.68,2488.53 4672.77,2498.61 4672.77,2584.21 4705.59,2617.03 4705.59,2735.86 4644.04,2797.41 v2(4644.04,2847.5)
  L8 BOTTOM w7.75: v2(3726,823) 3757.94,823 3786.89,794.05 J4.116@3786.89,743.02
AWR_2_TDI: J4.119 U1_2.H13 | length 2691.3
  L1 TOP w10.5: U1_2.H13@4745.89,2825.55 4745.89,2840.98 v2(4749.6,2844.69)
  L6 SIGNAL 3 w6.9: v2(3854,808) 3884.19,808 4070.61,994.41 4070.61,1498.54 4761.96,2189.89 4761.96,2246.8 4933.97,2418.81 4933.97,2618.45 4859.78,2692.64 4819.48,2692.64 4749.6,2762.52 v2(4749.6,2844.69)
  L8 BOTTOM w7.75: J4.119@3845.94,743.02 3845.94,800.94 3853,808 v2(3854,808)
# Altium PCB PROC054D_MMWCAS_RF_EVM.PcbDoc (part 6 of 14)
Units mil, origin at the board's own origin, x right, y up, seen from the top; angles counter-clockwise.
Board outline 6299.21 x 5370.07 mil, 8 copper layers (L1 TOP, L2 GND, L3 SIGNAL 1, L4 GND, L5 SIGNAL 2, L6 SIGNAL 3, L7 GND, L8 BOTTOM), stack 53.5 mil thick; 775 components, 552 nets, 2648 pads, 7845 vias.

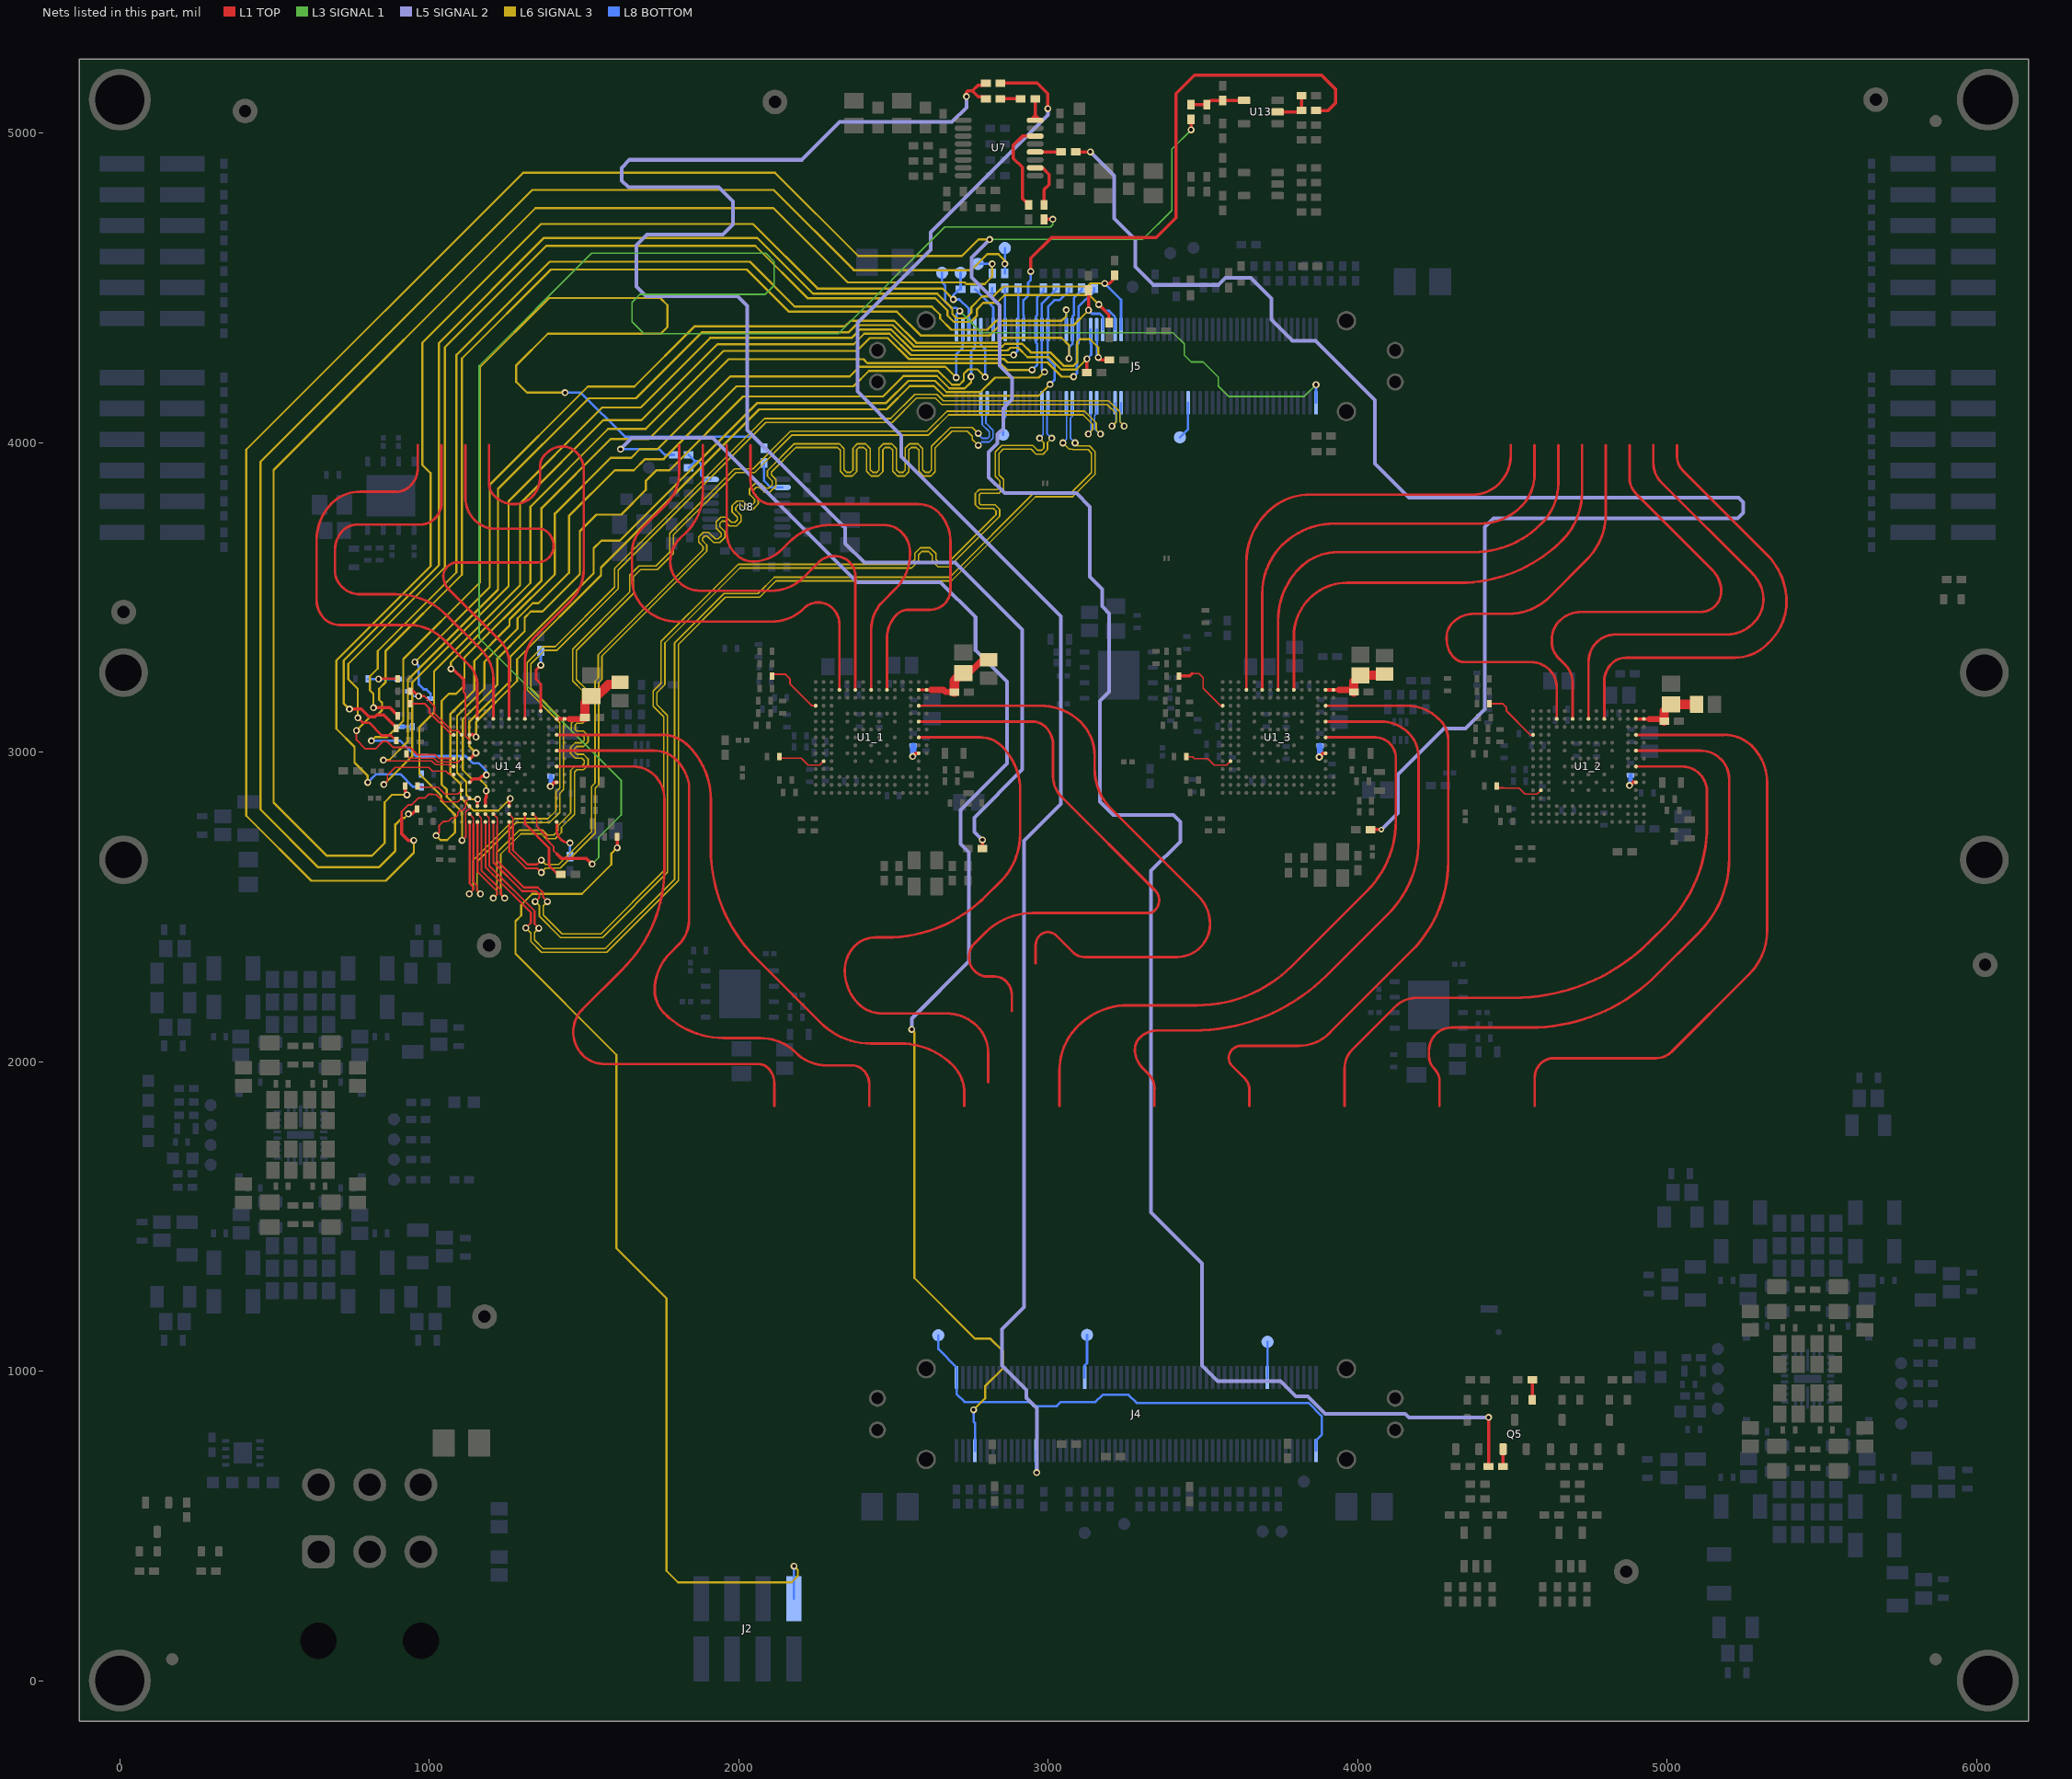
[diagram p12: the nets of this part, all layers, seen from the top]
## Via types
v1: diameter 13.77/15.74 (per signal layer), hole 5.9, L1 TOP to L2 GND, tented both sides, 5522 vias
v2: diameter 22.4, hole 12.2, L1 TOP to L8 BOTTOM, tented both sides, 1522 vias
v3: diameter 18, hole 8, L1 TOP to L8 BOTTOM, tented both sides, 727 vias
v4: diameter 18, hole 7.87, L1 TOP to L8 BOTTOM, tented top, 50 vias
v5: diameter 24, hole 12, L1 TOP to L8 BOTTOM, tented both sides, 13 vias
v6: diameter 19.68, hole 7.87, L1 TOP to L8 BOTTOM, tented top, 10 vias
v7: diameter 13.77/15.74 (per signal layer), hole 5.9, L1 TOP to L2 GND, tented top, 1 vias

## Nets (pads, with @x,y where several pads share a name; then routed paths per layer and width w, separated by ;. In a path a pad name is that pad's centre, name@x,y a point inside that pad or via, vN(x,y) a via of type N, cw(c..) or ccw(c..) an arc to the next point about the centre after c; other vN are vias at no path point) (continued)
AWR_4_CSI2_TX1_N: J5.65 U1_4.H14 | length 3691.2
  L1 TOP w4: U1_4.H14@1257.89,2799.95 1270.48,2787.37 1270.48,2766.89
  L1 TOP w6.5: 1270.48,2766.89 1270.48,2683.35 1317.04,2636.79 1348.07,2636.79 v2(1362,2650.72)
  L6 SIGNAL 3 w5: v2(1362,2650.72) 1375.87,2636.85 1418.25,2636.85 1524.71,2743.31 1524.71,2888.95 1535.54,2899.78 1535.54,3229.16 1546,3239.62 1546,3314.95 1884.88,3653.83 1884.88,3664.17 1870.23,3678.82 1870.23,3695.43 1885.14,3710.34 1902.61,3710.34 1923.74,3689.2 1933.84,3689.2 1943.18,3698.54 1943.18,3707.1 1926.73,3723.55 1926.73,3743.76 1941.54,3758.57 1960.11,3758.57 1975.67,3743.01 1988.26,3743.01 1995.71,3750.46 1995.71,3759.35 1978.15,3776.92 1978.15,3795.45 1993.52,3810.83 2013.19,3810.83 2029.2,3794.82 2039.28,3794.82 2051.3,3806.84 2051.3,3816.62 2035.1,3832.82 2035.1,3851.34 2051.53,3867.77 2071.94,3867.77 2087.45,3852.26 2096.42,3852.26 2108.01,3863.84 2108.01,3875.87 2092.98,3890.89 2092.98,3909.54 2179.71,3996.27 2324.85,3996.27 2340.28,3980.84 2340.28,3912.29 2348.42,3904.15 2361.93,3904.15 2369.02,3911.24 2369.02,3982.11 2383.18,3996.27 2409.43,3996.27 2424.86,3980.84 2424.86,3912.29 2433,3904.15 2446.51,3904.15 2453.6,3911.24 2453.6,3982.11 2467.76,3996.27 2494.01,3996.27 2509.44,3980.84 2509.44,3912.29 2517.58,3904.15 2531.09,3904.15 2538.18,3911.24 2538.18,3982.11 2552.34,3996.27 2578.59,3996.27 2594.02,3980.84 2594.02,3912.29 2602.16,3904.15 2615.67,3904.15 2622.76,3911.24 2622.76,3987.55 2684.4,4049.18 2754.75,4049.18 v2(2774,4029.93)
  L8 BOTTOM w5.25: v2@2774,4025.93 2785.93,4014 ; v2@2775.5,4025.93 v2@2775.5,4029.93 ; 2779.97,4019.97 2785.93,4014 ; J5.65@2782.95,4128.84 2782.95,4087.32 2786.8,4083.47 2786.8,4058.2 2810,4035 2810,4019.25 2804.75,4014 2787.43,4014 ; 2796.09,4014 2787.43,4014 ; 2785.93,4014 2787.43,4014
AWR_4_CSI2_TX1_P: J5.66 U1_4.H15 | length 3707.4
  L1 TOP w6.5: U1_4.H15@1257.89,2774.36 1258.48,2773.78 1258.48,2678.37 1312.06,2624.79 1348.31,2624.79 v2(1362,2611.1)
  L6 SIGNAL 3 w5: v2(1362,2611.1) 1375.74,2624.85 1423.23,2624.85 1536.71,2738.33 1536.71,2883.98 1547.54,2894.81 1547.54,3224.18 1558,3234.64 1558,3309.97 1896.89,3648.86 1896.89,3669.14 1882.24,3683.79 1882.24,3690.46 1890.11,3698.33 1897.63,3698.33 1918.77,3677.2 1938.82,3677.2 1955.19,3693.57 1955.19,3712.07 1938.73,3728.53 1938.73,3738.78 1946.52,3746.57 1955.13,3746.57 1970.7,3731 1993.24,3731 2007.72,3745.48 2007.72,3764.32 1990.15,3781.89 1990.15,3790.48 1998.49,3798.82 2008.22,3798.82 2024.22,3782.82 2044.25,3782.82 2063.31,3801.87 2063.31,3821.6 2047.11,3837.79 2047.11,3846.37 2056.51,3855.77 2066.96,3855.77 2082.47,3840.25 2101.4,3840.25 2120.01,3858.87 2120.01,3880.84 2104.98,3895.87 2104.98,3904.57 2184.69,3984.27 2319.88,3984.27 2328.28,3975.87 2328.28,3907.32 2343.45,3892.15 2366.9,3892.15 2381.02,3906.27 2381.02,3977.14 2388.15,3984.27 2404.46,3984.27 2412.86,3975.87 2412.86,3907.32 2428.03,3892.15 2451.48,3892.15 2465.6,3906.27 2465.6,3977.14 2472.73,3984.27 2489.04,3984.27 2497.44,3975.87 2497.44,3907.32 2512.61,3892.15 2536.06,3892.15 2550.18,3906.27 2550.18,3977.14 2557.31,3984.27 2573.62,3984.27 2582.02,3975.87 2582.02,3907.32 2597.19,3892.15 2620.65,3892.15 2634.76,3906.27 2634.76,3982.58 2689.37,4037.18 2738.58,4037.18 2755.2,4020.56 2755.2,4010.3 v2(2774,3991.5)
  L8 BOTTOM w5.25: v2(2774,3991.5) 2784.5,4002 2786,4002 ; 2797.86,4002 2786,4002 ; J5.66@2802.64,4128.84 2802.64,4087.55 2798.8,4083.71 2798.8,4063.18 2822,4039.98 2822,4014.27 2809.73,4002 2786,4002
AWR_4_CSI2_TX2_N: J5.75 U1_4.K14 | length 3678.2
  L1 TOP w4: U1_4.K14@1206.71,2799.95 1219.3,2787.37 1219.3,2764
  L1 TOP w6.5: 1219.3,2764 1219.3,2648.85 1305.15,2563 1350.76,2563 1367.49,2546.28 1367.49,2531.13 v2(1381.62,2517)
  L6 SIGNAL 3 w5: v2(1381.62,2517) 1368,2503.38 1368,2473.97 1428.96,2413.01 1554.66,2413.01 1758,2616.35 1758,3114 1723.48,3148.52 1723.48,3197.12 1749.22,3222.87 1749.22,3357.38 1932.28,3540.44 1998.61,3606.77 2553.76,3606.77 2569.17,3622.19 2569.17,3642.5 2586.73,3660.07 2618.16,3660.07 2637.09,3641.13 2637.09,3622.16 2649.03,3610.22 2674.73,3610.22 2824.51,3760 2831.28,3766.78 2831.28,3779.1 2823.38,3787 2776.85,3787 2764.73,3799.12 2764.73,3835.68 2776.94,3847.89 2835.98,3847.89 2844.15,3856.06 2844.15,3875.87 2828.89,3891.13 2828.89,3970.02 2849.57,3990.7 2950.15,3990.7 2965.85,3975 2978.8,3975 2985.82,3982.03 2985.82,4000.18 v2(2972,4014)
  L8 BOTTOM w5.25: v2(2972,4014) 2984,4026.01 2984,4089.77 2979.8,4093.97 J5.75@2979.8,4128.84
AWR_4_CSI2_TX2_P: J5.76 U1_4.K15 | length 3688.3
  L1 TOP w6.5: U1_4.K15@1206.71,2774.36 1207.3,2773.78 1207.3,2643.87 1300.17,2551 1345.78,2551 1355.49,2541.3 1355.49,2530.49 v2(1342,2517)
  L6 SIGNAL 3 w5: v2(1342,2517) 1356,2503 1356,2468.99 1423.98,2401.01 1559.64,2401.01 1770,2611.38 1770,3118.98 1735.48,3153.5 1735.48,3192.14 1761.22,3217.89 1761.22,3352.4 2003.59,3594.77 2558.73,3594.77 2581.18,3617.21 2581.18,3637.53 2591.71,3648.06 2613.18,3648.06 2625.08,3636.16 2625.08,3617.19 2644.06,3598.22 2679.7,3598.22 2843.28,3761.8 2843.28,3784.08 2828.36,3799 2781.83,3799 2776.73,3804.1 2776.73,3830.7 2781.92,3835.89 2840.96,3835.89 2856.15,3851.08 2856.15,3880.85 2840.89,3896.11 2840.89,3965.04 2854.55,3978.7 2945.17,3978.7 2960.87,3963 2983.78,3963 2997.82,3977.05 2997.82,4000.43 v2(3011.39,4014)
  L8 BOTTOM w5.25: J5.76@2999.49,4128.84 2999.49,4093.48 2996,4089.99 2996,4029.39 v2(3011.39,4014)
AWR_4_CSI2_TX3_N: J5.79 U1_4.L14 | length 3684.6
  L1 TOP w4: U1_4.L14@1181.12,2799.95 1193.71,2787.37 1193.71,2766
  L1 TOP w6.5: 1193.71,2766 1193.71,2632.93 1340,2486.68 1340,2445 v2(1354,2431)
  L6 SIGNAL 3 w5: v2(1354,2431) 1340.03,2417.03 1340.03,2392.95 1367.87,2365.11 1568.15,2365.11 1792.9,2589.85 1792.9,3353.3 1952.15,3512.55 2062.65,3512.55 2115.21,3565.11 2682.11,3565.11 2954.3,3837.3 3074.3,3837.3 3140,3903 3140,3966 3129,3977 3079.73,3977 3077.73,3979 3067.61,3979 v2(3047.61,3999)
  L8 BOTTOM w5.25: v2(3047.61,3999) 3059.72,4011.09 3059.72,4109.04 3058.54,4110.22 J5.79@3058.54,4128.84
AWR_4_CSI2_TX3_P: J5.80 U1_4.L15 | length 3674.5
  L1 TOP w6.5: U1_4.L15@1181.12,2774.36 1181.71,2773.78 1181.71,2627.96 1205.12,2604.55 1328,2481.7 1328,2448 v2(1312,2432)
  L6 SIGNAL 3 w5: v2(1312,2432) 1328.03,2415.97 1328.03,2387.97 1362.89,2353.11 1573.13,2353.11 1804.9,2584.87 1804.9,3348.32 1957.12,3500.54 2067.62,3500.54 2120.19,3553.1 2687.08,3553.1 2959.28,3825.3 3079.28,3825.3 3152,3898.02 3152,3970.98 3133.98,3989 3097,3989 v2(3087,3999)
  L8 BOTTOM w5.25: J5.80@3078.23,4128.84 3078.23,4085.66 3071.72,4079.15 3071.72,4014.28 v2(3087,3999)
AWR_4_DIG_SYNCIN: R135.2 R185_4.2 U1_4.N10 | length 4126.6
  L1 TOP w10.5: U1_4.N10@1129.94,2902.31 1140.89,2913.27 1161.14,2913.27 1170.23,2922.36 1180.81,2922.36 v2(1184.59,2926.14)
  L6 SIGNAL 3 w6.9: v2(812.89,3036.27) 825.11,3048.49 863.51,3048.49 915.63,3100.61 915.63,3300.2 1163.16,3547.74 1163.16,4243.44 1387.06,4467.34 1746.85,4467.34 1769.9,4444.29 1769.9,4373.73 1747.83,4351.66 1383.07,4351.66 1281.14,4249.73 1281.14,4196.18 1315.78,4161.55 v2(1438.72,4161.55)
  L8 BOTTOM w7.75: v2@813.69,3036.36 906.66,3036.36 956.02,2987 R185_4.2@985.9,2987 1118.06,2987 1141.23,2963.83 1160.75,2963.83 1184.59,2939.99 v2(1184.59,2926.14) ; v2(1438.72,4161.55) 1489.22,4161.55 1631.55,4019.22 2044.12,4019.22 R135.2@2081.68,3981.65
AWR_4_DIG_SYNCIN_RS: R135.1 U8.10 | length 125.8
  L8 BOTTOM w7.75: R135.1@2081.68,3934.41 2081.68,3877.07 2103.38,3855.37 U8.10@2141.18,3855.37
AWR_4_DIG_SYNCOUT: R1_4.1 R162.1 TP1_4.1 | length 4670
  L1 TOP w10.5: R1_4.1@921.9,2891 921.9,2867.9 v2(927.8,2862)
  L6 SIGNAL 3 w6.9: v2(927.8,2862) 879.56,2862 855.43,2837.86 855.43,2706.35 813.99,2664.91 668.91,2664.91 496.86,2836.96 496.86,3911.25 1343.23,4757.63 2112.2,4757.63 2352.03,4517.8 2730.04,4517.8 2735.57,4512.27 2795.22,4512.27 2819,4536.05 v2(2819,4577.44)
  L8 BOTTOM w7.75: TP1_4.1@2772.45,4577.44 v2(2819,4577.44) R162.1@2819,4546.21
AWR_4_FMCW_CLKOUT: R84.1 U1_4.B15 | length 136.1
  L1 TOP w8.4: U1_4.B15@1411.44,2774.36 1411.44,2749.58 ccw(c1454.53,2749.58) v2(1454.53,2706.49)
  L8 BOTTOM w7.75: R84.1@1454.53,2662.84 v2(1454.53,2706.49)
AWR_4_FMCW_SYNCOUT: R85.1 U1_4.D1 | length 207.2
  L1 TOP w8.4: U1_4.D1@1360.26,3132.63 1360.26,3220.75 1345.01,3236 1345.01,3265.75 v2(1360.26,3281)
  L8 BOTTOM w7.75: v2(1360.26,3281) R85.1@1360.26,3327.2
AWR_4_GPIO_0: J5.16 R16_4.2 U1_4.N4 | length 2826.2
  L1 TOP w10.5: U1_4.N4@1129.94,3055.86 1143.82,3055.86 v2(1150.99,3048.69)
  L6 SIGNAL 3 w6.9: v2(1150.99,3048.69) 1150.99,3097.13 1283.76,3229.9 1283.76,3299.67 1554.82,3570.73 1554.82,3596.52 2065.84,4107.54 2477.71,4107.54 2552.9,4182.72 2630.93,4182.72 2662.62,4151.02 2969.02,4151.02 v2(3006,4188)
  L8 BOTTOM w7.75: v2(3006,4188) 3020.29,4202.29 3020.29,4250.71 2998,4273 2998,4363.57 J5.16@2999.49,4365.06 2999.49,4439.52 3019.8,4459.83 3036.84,4459.83 3067,4490 R16_4.2@3067,4498.97
AWR_4_GPIO_1: J5.15 R17_4.2 U1_4.N7 | length 2882
  L1 TOP w10.5: U1_4.N7@1129.94,2979.09 1132.38,2979.09 v2(1150.69,2997.4)
  L6 SIGNAL 3 w6.9: v2(1150.69,2997.4) 1128.67,3019.42 1128.67,3097.06 1261.79,3230.18 1261.79,3308.53 1531.25,3577.99 1531.25,3658.39 1556.14,3683.28 1615.52,3683.28 2060.12,4127.87 2476.41,4127.87 2548.38,4199.85 2634.43,4199.85 2671.36,4162.92 2781.23,4162.92 2828.13,4209.83 2969.83,4209.83 v2(2988,4228)
  L8 BOTTOM w7.75: v2(2988,4228) 2979.8,4236.2 J5.15@2979.8,4365.06 2979.8,4449.18 3026,4495.38 R17_4.2@3026,4498.97
AWR_4_GPIO_2: J5.14 R18_4.2 U1_4.N13 | length 3451.4
  L1 TOP w4: 1117.44,2769 1117.44,2806.5 1129.94,2819 U1_4.N13@1129.94,2825.55
  L1 TOP w6: v2(1106,2714.5) 1117.44,2725.94 1117.44,2769
  L6 SIGNAL 3 w6.9: v2(1106,2714.5) 1106,2806.2 1056.72,2855.49 1056.72,2878.5 1040.17,2895.04 1040.17,3165.16 1063.16,3188.15 1086.89,3188.15 1113.76,3215.02 1113.76,3306.04 1362.77,3555.05 1362.77,3788.38 1585.86,4011.47 1709.27,4011.47 1967.05,4269.24 2403.14,4269.24 2415.42,4256.96 2845.12,4256.96 2867.09,4235 v2(2948,4235)
  L8 BOTTOM w7.75: v2(2948,4235) 2964.81,4251.81 2964.81,4318.42 2960.12,4323.11 J5.14@2960.12,4365.06 2960.12,4407.15 2964.62,4411.66 2964.62,4469.57 2985,4489.95 R18_4.2@2985,4498.97
AWR_4_LVDS_FRCLK_N: J5.83 U1_4.M14 | length 3666.4
  L1 TOP w4: U1_4.M14@1155.53,2799.95 1168.12,2787.37 1168.12,2766.39
  L1 TOP w6.5: 1168.12,2766.39 1168.12,2617.86 1231.4,2554.58 1231.4,2540 v2(1243.4,2528)
  L6 SIGNAL 3 w5: v2(1243.4,2528) 1230.71,2540.69 1230.71,2670.48 1296.22,2736 1361.59,2736 1377.07,2720.52 1407.5,2720.52 1427.16,2740.18 1427.16,2756.89 1469,2798.72 1469,2935.78 1476.47,2943.25 1498.51,2943.25 1513,2957.74 1513,2978.26 1498.51,2992.75 1476.47,2992.75 1469,3000.22 1469,3010.78 1476.47,3018.25 1498.51,3018.25 1513,3032.74 1513,3053.26 1498.51,3067.75 1476.47,3067.75 1471.48,3072.74 1471.48,3088.26 1476.47,3093.25 1495.45,3093.25 1507.52,3105.32 1507.52,3202.84 1475.49,3234.87 1475.49,3327.78 1660.03,3512.32 1660.03,3566.76 1682.84,3589.57 1737.28,3589.57 1789.23,3641.52 1789.23,3701.98 1990.61,3903.35 2051.06,3903.35 2172.24,4024.53 2613.52,4024.53 2678.53,4089.54 3112.48,4089.54 3143.22,4058.8 3143.22,4041.61 v2(3129.61,4028)
  L8 BOTTOM w5.25: v2(3129.61,4028) 3138,4036.39 3138,4128.12 J5.83@3137.28,4128.84
AWR_4_LVDS_FRCLK_P: J5.84 U1_4.M15 | length 3684.1
  L1 TOP w6.5: U1_4.M15@1155.53,2774.36 1156.12,2773.78 1156.12,2612.88 1219.4,2549.6 1219.4,2540.4 v2(1207,2528)
  L6 SIGNAL 3 w5: v2(1207,2528) 1218.71,2539.71 1218.71,2675.46 1291.24,2748 1366.57,2748 1382.04,2732.52 1402.53,2732.52 1415.16,2745.15 1415.16,2761.86 1457,2803.7 1457,2940.76 1471.49,2955.25 1493.53,2955.25 1501,2962.72 1501,2973.28 1493.53,2980.75 1471.49,2980.75 1457,2995.24 1457,3015.76 1471.49,3030.25 1493.53,3030.25 1501,3037.72 1501,3048.28 1493.53,3055.75 1471.49,3055.75 1459.48,3067.76 1459.48,3093.24 1471.49,3105.25 1490.47,3105.25 1495.52,3110.3 1495.52,3197.86 1463.49,3229.89 1463.49,3332.76 1648.02,3517.29 1648.02,3571.74 1677.86,3601.58 1732.31,3601.58 1777.22,3646.5 1777.22,3706.95 1985.63,3915.36 2046.09,3915.36 2167.26,4036.53 2608.54,4036.53 2673.55,4101.54 3117.46,4101.54 3155.22,4063.78 3155.22,4041.78 v2(3169,4028)
  L8 BOTTOM w5.25: J5.84@3156.97,4128.84 3156.97,4094.57 3150,4087.6 3150,4044 3166,4028 v2(3169,4028)
AWR_4_LVDS_VALID_N: J5.87 U1_4.N14 | length 3675.4
  L1 TOP w4: U1_4.N14@1129.94,2799.95 1142.53,2787.37 1142.53,2767.89
  L1 TOP w6.5: 1142.53,2767.89 1142.53,2580.45 1153.2,2569.78 1153.2,2554.2 v2(1165.4,2542)
  L6 SIGNAL 3 w5: v2(1165.4,2542) 1154,2553.4 1154,2645.6 1281.08,2772.69 1388.68,2772.69 1421.43,2805.44 1421.43,2866.68 1433.76,2879 1433.76,3100.12 1327.99,3205.88 1327.99,3284.69 1371.86,3328.55 1411.51,3328.55 1610.67,3527.72 1610.67,3588.17 2088.05,4065.55 2495.78,4065.55 2574.23,4144 2635.01,4144 2655.84,4123.17 3190.38,4123.17 3219.56,4093.99 3219.56,4066.58 v2(3206.17,4053.19)
  L8 BOTTOM w5.25: v2(3206.17,4053.19) 3219.53,4066.55 3219.53,4092.21 3216.02,4095.72 J5.87@3216.02,4128.84
AWR_4_LVDS_VALID_P: J5.88 U1_4.N15 | length 3686.1
  L1 TOP w6.5: v2(1129,2542) 1141.2,2554.2 1141.2,2564.8 1130.53,2575.47 1130.53,2773.78 U1_4.N15@1129.94,2774.36
  L6 SIGNAL 3 w5: v2(1129,2542) 1142,2555 1142,2650.58 1276.1,2784.69 1383.7,2784.69 1409.43,2810.42 1409.43,2871.65 1421.76,2883.97 1421.76,3095.15 1315.99,3200.91 1315.99,3289.66 1366.89,3340.55 1406.53,3340.55 1598.67,3532.69 1598.67,3593.14 2083.08,4077.55 2490.81,4077.55 2569.26,4156 2639.98,4156 2660.81,4135.17 3195.36,4135.17 3231.56,4098.96 3231.56,4067.19 v2(3245.56,4053.19)
  L8 BOTTOM w5.25: J5.88@3235.71,4128.84 3235.71,4095.79 3231.53,4091.62 3231.53,4067.22 v2(3245.56,4053.19)
AWR_4_MCU_CLKOUT: R5_4.1
AWR_4_MSS_LOGGER: J5.19 R15_4.1 | length 3649
  L1 TOP w10.5: v2(819.49,3143.3) 872.7,3143.3 899,3117 R15_4.1@900.1,3117
  L6 SIGNAL 3 w6.9: v2(819.49,3143.3) 819.49,3188.14 807.86,3199.77 807.86,3244.59 833.69,3270.42 833.69,3326.62 1087.5,3580.43 1087.5,4283.16 1389.04,4584.7 2036,4584.7 2181.41,4439.29 2624.27,4439.29 2650.63,4412.92 2650.63,4400.84 2687.05,4364.42 2803.01,4364.42 2832.55,4393.97 3044.06,4393.97 3058.54,4408.45 v2(3058.54,4429)
  L8 BOTTOM w7.75: J5.19@3058.54,4365.06 v2(3058.54,4429)
AWR_4_NERROR_IN: R177_4.1 U1_4.P7 | length 197.1
  L1 TOP w4: R177_4.1@926.4,2995 926.4,2991.27 936.67,2981 1014,2981 1026,2969 1066,2969 1068.41,2966.59 1091.85,2966.59 U1_4.P7@1104.35,2979.09
AWR_4_NERROR_OUT: R9_4.1 R160.1 | length 36.9
  L8 BOTTOM w7.75: R160.1@909,3082 R9_4.1@945.9,3082
AWR_4_NRST: R203.2 R210.2 U1_4.P12 | length 11634.2
  L1 TOP w4: 1010.19,2863.13 1022.72,2863.13 1047.21,2838.64 1091.85,2838.64 U1_4.P12@1104.35,2851.13
  L1 TOP w6: 910.71,2784.3 910.71,2807.53 932.99,2829.81 942.81,2829.81 964.31,2851.31 985.45,2851.31 997.33,2863.2 1010.19,2863.2
  L1 TOP w10.5: 910.71,2784.3 910.71,2735.9 931.59,2715.01 v2(949.95,2715.01) ; v2(3461.75,5010.51) R210.2@3461.75,5044.66 ; R203.2@4422.96,691.84 v2(4422.96,850.2)
  L3 SIGNAL 1 w5.1: v2(2811.14,4656.3) 3305.51,4656.3 3399.71,4750.5 3399.71,4948.48 v2(3461.75,5010.51)
  L5 SIGNAL 2 w12: v2(2811.14,4656.3) 2752.99,4598.15 2752.99,4534.61 2843.89,4443.71 2843.89,4248.66 2883.9,4208.65 2883.9,4139.47 2854.73,4110.3 2854.73,4045.49 2835.88,4026.64 2835.88,3997.26 2808.05,3969.44 2808.05,3887.75 2859.05,3836.75 3090.77,3836.75 3135.12,3792.4 3135.12,3566.3 3174.58,3526.84 3174.58,3471.33 3197.59,3448.32 3197.59,3195.18 3167.5,3165.08 3167.5,2839.63 3210.69,2796.43 3405.15,2796.43 3426.81,2774.77 3426.81,2711.13 3332.25,2616.57 3332.25,1513.3 3497.17,1348.37 3497.17,1018.47 3547.63,968.01 3750.58,968.01 3799.73,918.86 3839.36,918.86 3895.59,862.63 4153.24,862.63 4165.66,850.2 v2(4422.96,850.2)
  L6 SIGNAL 3 w6.9: v2(949.95,2715.01) 949.95,2674.99 859.45,2584.49 618.41,2584.49 408.49,2794.4 408.49,3977.47 1302.71,4871.69 2117.54,4871.69 2386.24,4602.99 2721.65,4602.99 2774.96,4656.3 v2(2811.14,4656.3)
AWR_4_NRST_HOST: J5.12 R77.1 | length 1841.1
  L1 TOP w10.5: v2(2943.45,4553.08) 2943.45,4595.19 3011.2,4662.93 3349.73,4662.93 3413.43,4726.64 3413.43,5127.66 3472.8,5187.03 3883.5,5187.03 3928.12,5142.41 3928.12,5096.69 3904.7,5073.27 R77.1@3865.5,5073.27
  L8 BOTTOM w7.75: J5.12@2920.75,4365.06 2920.75,4411.29 2920.36,4411.68 2920.36,4459.83 2935.49,4474.96 2935.49,4516.46 2943.45,4524.42 v2(2943.45,4553.08)
AWR_4_NRST_HOST_GS: R77.2 R92.1 U13.2 | length 126.2
  L1 TOP w10.5: U13.2@3741.51,5068.27 3813.25,5068.27 R77.2@3818.25,5073.27 R92.1@3818.25,5120.67
AWR_4_NRST_LED: Q5.1 R203.1 | length 56.1
  L1 TOP w10.5: R203.1@4470.21,691.84 Q5.1@4470.21,747.96
AWR_4_NRST_LED_PW: DS7.1 R201.1 | length 65
  L1 TOP w10.5: DS7.1@4564.7,906.78 R201.1@4564.7,971.8
AWR_4_NRST_RS: C149.1 R61.1 R210.1 U13.4 | length 177.2
  L1 TOP w10.5: R210.1@3461.75,5091.91 R61.1@3512.69,5091.91 3526.45,5105.67 C149.1@3564.27,5105.67 U13.4@3633.24,5105.67
AWR_4_OSC_CLKOUT: J2.7 R2_4.1 | length 3394.8
  L1 TOP w10.5: v2(1607.14,2691.08) R2_4.1@1607.14,2726.23
  L6 SIGNAL 3 w6.9: v2(1607.14,2691.08) 1588.31,2672.26 1588.31,2636.9 1493.38,2541.98 1332.56,2541.98 1296.94,2506.36 1296.94,2472.28 1278.24,2453.59 1278.24,2348.55 1604.67,2022.13 1604.67,1396.91 1766.71,1234.86 1766.71,354.59 1803.68,317.62 2170.69,317.62 2190.99,337.92 2190.99,357.24 v2(2178.45,369.78)
  L8 BOTTOM w7.75: J2.7@2178.45,264.5 v2(2178.45,369.78)
AWR_4_PMIC_CLKOUT: R4_4.1 R163.1 TP2_4.1 | length 4834.5
  L1 TOP w10.5: v2(932.8,2800) 945,2800 R4_4.1@961,2816
  L6 SIGNAL 3 w6.9: v2(932.8,2800) 919.67,2786.87 911.18,2786.87 890.24,2765.93 890.24,2680.76 837.3,2627.82 641.37,2627.82 454.71,2814.47 454.71,3938.12 1333.02,4816.43 2112.83,4816.43 2371.88,4557.38 2751.78,4557.38 2803.27,4608.86 2839.11,4608.86 2860,4587.98 v2(2860,4577.44)
  L8 BOTTOM w7.75: R163.1@2860,4546.21 v2(2860,4577.44) TP2_4.1@2860,4628.72
AWR_4_SCL: R114.2 R180_4.1 U1_4.P4 | length 276
  L1 TOP w4: 1016.29,3132.85 1016.29,3125.73 1073.07,3068.95 1091.26,3068.95 U1_4.P4@1104.35,3055.86
  L1 TOP w6: v2(965.29,3180.96) 984.1,3180.96 1016.29,3148.77 1016.29,3132.85
  L1 TOP w8: R180_4.1@937.91,3197 949.25,3197 v2(965.29,3180.96)
  L8 BOTTOM w7.75: R114.2@933.88,3195.9 948.82,3180.96 v2(965.29,3180.96)
AWR_4_SDA: R13_4.1 R125.2 R181_4.1 | length 159.4
  L1 TOP w8: v2(835.99,3236) 836.99,3237 R13_4.1@897.9,3237
  L8 BOTTOM w7.75: R125.2@801.74,3236.1 v2@835.89,3236.1 ; v2@836.09,3235.9 R181_4.1@899.06,3235.9
AWR_4_SOP0_TDO: J5.7 R161.2 | length 154.1
  L8 BOTTOM w7.75: R161.2@2764.12,4495.09 2822.32,4436.89 J5.7@2822.32,4365.06
AWR_4_SOP1_SYNCOUT: J5.8 R162.2 | length 143.4
  L8 BOTTOM w7.75: R162.2@2819,4498.97 2819,4469 2842.01,4445.99 J5.8@2842.01,4365.06
AWR_4_SOP2_PMICCLKOUT: J5.9 R163.2 | length 134.6
  L8 BOTTOM w7.75: R163.2@2860,4498.97 2860,4366.75 J5.9@2861.69,4365.06
AWR_4_SPI_CLK1: J5.23 R182_4.2 U1_4.R9 | length 3671.8
  L1 TOP w4: v2(853,2895) 864,2906 864,2925 890,2951 998,2951 1010,2939 1053,2939 1064.09,2927.91 U1_4.R9@1078.76,2927.91
  L1 TOP w10.5: R182_4.2@3125.04,4226.15 v2(3125.04,4270.14)
  L6 SIGNAL 3 w6.9: v2(853,2895) 944.45,2986.45 944.45,3224.24 1256.01,3535.79 1256.01,3810.58 1558.62,4113.2 1683.18,4113.2 1908.08,4338.1 2364.48,4338.1 2391.91,4365.53 2492.76,4365.53 2560.66,4297.63 2868.84,4297.63 2877.9,4306.69 2902.69,4306.69 2932.94,4276.45 3002.09,4276.45 3042.56,4235.98 3090.88,4235.98 v2(3125.04,4270.14)
  L8 BOTTOM w7.75: v2(3125.04,4270.14) 3139,4284.1 3139,4319 3137.28,4320.72 J5.23@3137.28,4365.06
AWR_4_SPI_CS1: J5.25 R175_4.1 U1_4.R7 | length 4177.6
  L1 TOP w6: v2(764.71,3069.65) 764.71,3039.42 793.53,3010.6 825.41,3010.6 849.01,3034.21 863.89,3034.21 882.52,3015.58 937.4,3015.58 961.98,2991 1019,2991 1030.91,2979.09 U1_4.R7@1078.76,2979.09
  L1 TOP w10.5: v2(3130.51,4427.61) R175_4.1@3130.51,4492.45
  L6 SIGNAL 3 w6.9: v2(764.71,3069.65) 808.89,3113.83 825.82,3113.83 847.41,3135.42 847.41,3159.26 837.58,3169.1 837.58,3204.45 859.05,3225.93 859.05,3327.13 1105.2,3573.29 1105.2,4271.68 1392.66,4559.14 2025.94,4559.14 2162.23,4422.85 2511.41,4422.85 2587.89,4346.38 2810.97,4346.38 2844.27,4379.67 3082.57,4379.67 v2(3130.51,4427.61)
  L8 BOTTOM w7.75: v2(3130.51,4427.61) 3141.53,4416.58 3167.17,4416.58 3176.65,4407.1 J5.25@3176.65,4365.06
AWR_4_SPI_HOST_INTR1: J5.27 R10_4.2 R184_4.2 | length 4097.7
  L1 TOP w8: v2(768.88,3110.53) 784.52,3094.89 805.48,3094.89 846.37,3054 876,3054 R10_4.2@893,3037
  L1 TOP w10.5: v2(3163.34,4446.33) 3196.34,4413.33 R184_4.2@3196.34,4387.27
  L6 SIGNAL 3 w6.9: v2(768.88,3110.53) 768.88,3204.85 738.54,3235.18 738.54,3285.27 1050.44,3597.16 1050.44,4308.18 1378.08,4635.83 2053.23,4635.83 2222.3,4466.76 2634.39,4466.76 2674.43,4426.72 2674.43,4410.95 2695.38,4390.01 2749.22,4390.01 2770.05,4410.83 2770.05,4431.35 2790.07,4451.37 2833.44,4451.37 2858.85,4476.78 3132.88,4476.78 v2(3163.34,4446.33)
  L8 BOTTOM w7.75: v2(3163.34,4446.33) 3183.95,4425.71 3197.03,4425.71 3216.02,4406.73 J5.27@3216.02,4365.06
AWR_4_SPI_MISO1: J5.28 R12_4.2 R176_4.1 | length 4187.3
  L1 TOP w10.5: v2(742.02,3139) 780.39,3139 805.17,3114.23 824.54,3114.23 830.39,3120.08 852.32,3120.08 892.89,3079.52 R12_4.2@892.89,3077 ; v2(3182.67,4514.41) 3197.54,4514.41 3215.4,4532.26 R176_4.1@3215.4,4540.37
  L6 SIGNAL 3 w6.9: v2(742.02,3139) 723.08,3157.94 723.08,3295.52 1031.03,3603.47 1031.03,4321.4 1371.02,4661.39 2059.57,4661.39 2239.9,4481.06 2641.54,4481.06 2689.93,4432.67 2689.93,4415.81 2703.84,4401.91 2734.05,4401.91 2751.59,4419.45 2751.59,4437.67 2786.07,4472.14 2822.86,4472.14 2854.72,4504 3126.28,4504 3136.7,4514.41 v2(3182.67,4514.41)
  L8 BOTTOM w7.75: v2(3182.67,4514.41) 3235.71,4461.38 J5.28@3235.71,4365.06
AWR_4_SPI_MOSI1: J5.24 R183_4.2 U1_4.R8 | length 3745.2
  L1 TOP w4: v2(851.8,2974.1) 854.9,2971 1008,2971 1020,2959 1063,2959 1068.5,2953.5 U1_4.R8@1078.76,2953.5
  L1 TOP w10.5: v2(3162,4275) 3169.85,4267.15 R183_4.2@3198.04,4267.15
  L6 SIGNAL 3 w6.9: v2(851.8,2974.1) 870.25,2974.1 930.7,3034.55 930.7,3233.6 1222.22,3525.11 1222.22,3850.07 1515.55,4143.4 1667.89,4143.4 1880.55,4356.06 2354.51,4356.06 2377.93,4379.48 2497.77,4379.48 2566.58,4310.68 2851.46,4310.68 2860.29,4319.51 2915.98,4319.51 2944.01,4291.47 3006.33,4291.47 3049.57,4248.23 3081.78,4248.23 3093.78,4260.23 3093.78,4325.24 3102.8,4334.26 3135.26,4334.26 3162,4307.52 v2(3162,4275)
  L8 BOTTOM w7.75: J5.24@3156.97,4365.06 3156.97,4280.03 v2(3162,4275)
AWR_4_TCK: J5.5 U1_4.M13 | length 2897.7
  L1 TOP w10.5: U1_4.M13@1155.53,2825.55 1155.53,2844.23 v2(1156.04,2847.5)
  L6 SIGNAL 3 w6.9: v2(1156.04,2847.5) 1134.48,2847.5 1119.5,2862.48 1119.5,2903.95 1089.74,2933.71 1089.74,3117.1 1177.89,3205.25 1177.89,3291.79 1284.89,3398.78 1284.89,3431.82 1334.04,3480.98 1352.93,3480.98 1451.14,3579.19 1451.14,3762.38 1599.23,3910.46 1661.03,3910.46 1697.19,3946.62 1757.33,3946.62 1992.5,4181.79 2370.45,4181.79 2420.44,4231.78 2644.19,4231.78 2689.24,4186.72 2712.95,4186.72 2727.47,4201.24 2727.47,4222.47 2741.93,4236.93 2771.07,4236.93 v2(2796,4212)
  L8 BOTTOM w7.75: J5.5@2782.95,4365.06 2782.95,4315.63 2796,4302.58 v2(2796,4212)
AWR_4_TDI: J5.2 U1_4.H13 | length 2962.8
  L1 TOP w10.5: U1_4.H13@1257.89,2825.55 1257.89,2841.79 1261.6,2845.5 v2(1261.6,2849.69)
  L6 SIGNAL 3 w6.9: v2(1261.6,2849.69) 1222.72,2810.81 1143.56,2810.81 1101.41,2852.95 1101.41,2895.95 1067.81,2929.55 1067.81,3121.9 1145.21,3199.3 1145.21,3294.52 1259.31,3408.62 1259.31,3428.22 1405.91,3574.82 1405.91,3770.49 1586.4,3950.99 1652.86,3950.99 1680.64,3978.76 1737.9,3978.76 1972.74,4213.6 2358.44,4213.6 2389.9,4245.06 2667.86,4245.06 v2(2702.91,4210)
  L8 BOTTOM w7.75: v2(2702.91,4210) 2702.91,4286.29 2723.89,4307.27 J5.2@2723.89,4365.06
AWR_4_TDO: J5.3 R8_4.2 R161.1 TP3_4.1 | length 4005.5
  L6 SIGNAL 3 w6.9: v2(801.13,2901.87) 801.13,2923.53 758.17,2966.48 758.17,3017.16 699.85,3075.49 699.85,3296.27 1004.12,3600.54 1004.12,3901.2 977.48,3927.85 977.48,4322.89 1361.07,4706.48 2045.93,4706.48 2254.47,4497.94 2657.94,4497.94 v2(2693.28,4462.6)
  L8 BOTTOM w7.75: v2(801.13,2901.87) 827.83,2928.58 906.51,2928.58 947.31,2887.78 R8_4.2@974.55,2887.78 ; TP3_4.1@2716.88,4548.68 R161.1@2716.88,4495.09 2712.73,4495.09 2693.28,4475.64 v2(2693.28,4462.6) 2713.2,4462.6 2743.58,4432.22 J5.3@2743.58,4365.06
AWR_4_TMS: J5.4 U1_4.L13 | length 2803.2
  L1 TOP w10.5: U1_4.L13@1181.12,2825.55 1181.12,2850.22 1183.94,2853.04 v2(1183.94,2874.94)
  L6 SIGNAL 3 w6.9: v2(1183.94,2874.94) 1183.94,2891.01 1161.1,2913.85 1136.45,2913.85 1108.41,2941.89 1108.41,3106.16 1220.25,3217.99 1220.25,3302.4 1308.36,3390.51 1308.36,3434.23 1328.27,3454.14 1366.2,3454.14 1486.72,3574.66 1486.72,3714.11 1540,3767.39 1620.2,3767.39 1699.39,3846.58 1699.39,3875.96 1733.61,3910.17 1775.36,3910.17 2014.33,4149.14 2466.51,4149.14 2532.34,4214.97 2640.6,4214.97 2680.75,4174.82 2730.39,4174.82 2751,4195.43 v2(2751,4213)
  L8 BOTTOM w7.75: v2(2751,4213) 2751,4294.5 2763.27,4306.77 J5.4@2763.27,4365.06
AWR_4_UART_RX: J5.21 R179_4.1 U1_4.N5 | length 3243.7
  L1 TOP w4: 1117,3146.75 1117,3051 1118,3050 1118,3049.9 1129.94,3037.96 U1_4.N5@1129.94,3030.27
  L1 TOP w6: 1111,3204.56 1111,3193.55 1117,3187.55 1117,3146.75
  L1 TOP w10.5: v2(1070,3269) 1076,3269 1111,3234 1111,3204.56
  L6 SIGNAL 3 w6.9: v2(1070,3269) 1070,3289.82 1326.66,3546.48 1326.66,3792.85 1578.15,4044.34 1699.42,4044.34 1951.02,4295.94 2381.79,4295.94 2423.68,4337.83 2481.62,4337.83 2548.85,4270.6 2856.51,4270.6 2868.11,4259.01 2998.1,4259.01 3044.11,4213 v2(3082,4213)
  L8 BOTTOM w7.75: v2(3082,4213) 3093,4224 3093,4316 3097.91,4320.91 3097.91,4438.57 3149,4489.66 R179_4.1@3149,4498.97
AWR_4_UART_TX: J5.20 R11_4.1 R178_4.1 | length 3241.3
  L6 SIGNAL 3 w6.9: v2(953.55,3291.06) 1195.4,3532.91 1195.4,3864.03 1512.53,4181.16 1662.68,4181.16 1857.68,4376.17 2344.13,4376.17 2361.56,4393.6 2502.95,4393.6 2573.97,4322.58 2836.71,4322.58 2852.7,4338.56 3043.36,4338.56 3067.59,4314.33 v2(3067.59,4271.64)
  L8 BOTTOM w7.75: v2(953.55,3291.06) 966.02,3278.58 966.02,3218.61 982.26,3202.38 990.5,3202.38 1003.91,3188.98 R11_4.1@1003.91,3172.94 ; v2(3067.59,4271.64) 3067.59,4308.34 3078.23,4318.98 3078.23,4407.22 3082.73,4411.72 3082.73,4466.77 3108,4492.04 R178_4.1@3108,4498.97
AWR_4_WARM_RST: J5.11 R174_4.1 U1_4.N12 | length 3582.7
  L1 TOP w4: 1053.96,2776.24 1062.24,2776.24 1073,2787 1083.48,2787 1091.85,2795.37 1091.85,2805.14 1099.17,2812.46 1108.94,2812.46 1117.44,2820.96 1117.44,2838.64 U1_4.N12@1129.94,2851.13
  L1 TOP w6: v2(1022,2730) 1032.23,2740.23 1032.23,2762.8 1045.67,2776.24 1053.96,2776.24
  L6 SIGNAL 3 w6.9: v2(1022,2730) 1036.4,2715.6 1057.94,2715.6 1083.5,2741.16 1083.5,2797 1038.51,2841.99 1038.51,2859.18 968.09,2929.61 968.09,3080.87 1015.56,3128.34 1015.56,3261.34 1293.32,3539.1 1293.32,3802.98 1562.67,4072.33 1685.28,4072.33 1931,4318.05 2371.72,4318.05 2405.76,4352.09 2487.32,4352.09 2556.41,4283 v2(2888,4283)
  L8 BOTTOM w7.75: v2(2888,4283) 2901.06,4296.06 J5.11@2901.06,4365.06 2903,4367 R174_4.1@2903,4498.97
AWR_4_XTAL_CLKM: R131.2 U1_4.F14 | length 248.6
  L1 TOP w8: U1_4.F14@1309.07,2799.95 1309.07,2768.17 1387.04,2690.21 1387.04,2633.55 1415.59,2604.99 R131.2@1425.11,2604.99
AWR_4_XTAL_CLKP: R108.2 U1_4.E14 | length 5430
  L1 TOP w4: U1_4.E14@1334.67,2799.95 1347.17,2787.45 1347.17,2759.83 1353.3,2753.7
  L1 TOP w6: 1353.3,2753.7 1379.51,2727.49 1379.51,2717 1402.49,2694.01 1402.49,2680.63 1412.37,2670.75
  L1 TOP w10.5: 1412.37,2670.75 1427.3,2655.82 1508.38,2655.82 v2(1526.14,2638.05) ; R108.2@2986.58,4721.32 v2(3014.98,4721.32)
  L3 SIGNAL 1 w5.1: v2(1526.14,2638.05) 1547.59,2659.51 1547.59,2724.31 1620.04,2796.75 1620.04,2909.33 1161.25,3368.12 1161.25,4248.67 1524.23,4611.65 2087.1,4611.65 2114.06,4584.7 2114.06,4507.54 2085.72,4479.2 1681.24,4479.2 1655.35,4453.32 1655.35,4390.99 1694.02,4352.32 2321.49,4352.32 2665.78,4696.61 3007.07,4696.61 3014.98,4704.52 v2(3014.98,4721.32)
AWR_CONN_TP1: J4.22 TP12.1 | length 140.8
  L8 BOTTOM w7.75: J4.22@3117.6,979.24 3117.6,1018.08 3125.61,1026.1 TP12.1@3125.61,1116.7
AWR_CONN_TP2: J4.52 TP15.1 | length 115.8
  L8 BOTTOM w7.75: J4.52@3708.15,979.24 3709,980.09 TP15.1@3709,1094.73
AWR_CONN_TP3: J5.69 TP8.1 | length 106.3
  L8 BOTTOM w7.75: TP8.1@2854.35,4025.61 2854.35,4076.29 2861.69,4083.63 J5.69@2861.69,4128.84
AWR_CONN_TP4: J5.99 TP13.1 | length 122.8
  L8 BOTTOM w7.75: TP13.1@3425.79,4016.95 3452.24,4043.4 J5.99@3452.24,4128.84
AWR_RX1_1: U1_1.M2 | length 1500.4
  L1 TOP w8.4: 1807.5,3991.32 1807.5,3901.87 cw(c1664.15,3901.88) 1765.51,3800.51 1687.36,3722.36 ccw(c1765.49,3644.23) 1655,3644.23 1655,3560.12 ccw(c1788.07,3560.12) 1693.98,3466.02 ccw(c1800.99,3572.98) 1800.99,3421.68 2107.7,3421.68 ccw(c2107.69,3566.36) 2210,3464.06 cw(c2257,3417.06) 2304,3464.06 cw(c2252.03,3412.08) 2325.53,3412.09 U1_1.M2@2325.53,3201.04
AWR_RX1_2: U1_2.M2 | length 1500.1
  L1 TOP w8.4: U1_2.M2@4643.53,3107.04 4643.53,3208.98 ccw(c4562.81,3208.98) 4619.89,3266.06 ccw(c4559.53,3205.7) 4559.53,3291.06 4344.27,3291.06 cw(c4344.27,3335.44) 4312.89,3304.06 cw(c4373.24,3364.4) 4287.89,3364.4 4287.89,3372.19 cw(c4352.76,3372.19) 4306.89,3418.06 cw(c4376.9,3348.06) 4376.9,3447.06 4489.05,3447.06 ccw(c4489.05,3632.57) 4620.23,3501.4 4741.08,3622.26 ccw(c4594.2,3769.14) 4801.92,3769.14 4801.92,3991.32
AWR_RX1_3: U1_3.M2 | length 1500.2
  L1 TOP w8.4: U1_3.M2@3640.53,3201.04 3640.53,3612.46 cw(c3870.49,3612.46) 3707.88,3775.06 cw(c3845.49,3637.45) 3845.49,3832.06 4372.24,3832.06 ccw(c4372.24,3952.63) 4457.04,3866.92 ccw(c4365.88,3958.08) 4494.8,3958.08 4494.8,3991.32
AWR_RX1_4: U1_4.M2 | length 1500.2
  L1 TOP w8.4: 660.47,3431.53 cw(c719.56,3490.61) 636,3490.61 636,3685.73 cw(c803.23,3685.73) 684.98,3803.98 cw(c774.33,3714.66) 774.33,3841 891.93,3841 ccw(c891.93,3907.56) 939,3860.5 ccw(c881.27,3918.24) 962.92,3918.24 962.92,3991.32 ; 660.48,3431.52 ccw(c710.02,3481.06) 710.02,3411 932.89,3411 cw(c932.89,3251.4) 1045.75,3364.25 1126.91,3283.09 cw(c1057.8,3213.99) 1155.53,3213.99 U1_4.M2@1155.53,3107.04
AWR_RX2_1: U1_1.K2 | length 1500.4
  L1 TOP w8.4: 1778.71,3615.15 ccw(c1870.08,3615.15) 1805.47,3550.54 ; 1778.71,3615.19 cw(c1883.76,3615.19) 1809.48,3689.47 1831.23,3711.22 ccw(c1703.17,3839.29) 1884.28,3839.29 1884.28,3991.32 ; 1805.48,3550.53 ccw(c1876.62,3621.66) 1876.62,3521.06 2105.03,3521.06 ccw(c2105.03,3668) 2208.93,3564.1 2257.89,3613.05 cw(c2308.41,3562.53) 2358.92,3613.05 ; 2358.93,3613.03 cw(c2316.02,3570.11) 2376.71,3570.11 U1_1.K2@2376.71,3201.04
AWR_RX2_2: U1_2.K2 | length 1500.2
  L1 TOP w8.4: 4651.57,3423.36 ccw(c4708.75,3366.2) 4627.9,3366.2 4627.9,3354.42 ccw(c4698.79,3354.42) 4648.65,3304.31 4670.9,3282.06 cw(c4613.39,3224.57) 4694.71,3224.57 U1_2.K2@4694.71,3107.04 ; 4651.58,3423.36 cw(c4723.28,3351.65) 4723.28,3453.06 5108.9,3453.06 ccw(c5108.9,3519.06) 5174.9,3519.06 ccw(c5075.92,3519.05) 5145.9,3589.05 4900.3,3834.65 cw(c4952.41,3886.77) 4878.71,3886.76 4878.71,3991.32
AWR_RX2_3: U1_3.K2 | length 1500.2
  L1 TOP w8.4: U1_3.K2@3691.71,3201.04 3691.71,3513.43 cw(c3911.11,3513.43) 3755.97,3668.57 cw(c3923.74,3500.79) 3923.74,3738.06 4394.88,3738.06 ccw(c4394.88,3927.5) 4528.84,3793.55 ccw(c4425.62,3896.76) 4571.59,3896.76 4571.59,3991.32
AWR_RX2_4: U1_4.K2 | length 1500.2
  L1 TOP w8.4: 1039.7,3991.32 1039.7,3806.89 cw(c965.61,3806.89) 1018,3754.5 cw(c970.92,3801.58) 970.92,3735 766.46,3735 ccw(c766.46,3671.12) 721.29,3716.29 ccw(c784.71,3652.84) 695,3652.84 695,3586.68 ccw(c768.42,3586.68) 716.5,3534.77 ccw(c776.29,3594.55) 776.29,3510 893.31,3510 cw(c893.31,3280.19) 1055.81,3442.69 1168,3330.5 cw(c1074.55,3237.05) 1206.71,3237.05 U1_4.K2@1206.71,3107.04
AWR_RX3_1: U1_1.H2 | length 1500
  L1 TOP w8.4: 1961.06,3991.32 1961.06,3707.89 ccw(c2053.89,3707.89) 1988.25,3642.25 1992.93,3637.57 ccw(c2045,3689.63) 2045,3616 ccw(c2045,3751.2) 2140.6,3655.6 2164.52,3679.52 cw(c2296.06,3547.97) 2296.06,3734 2469.07,3734 cw(c2469.07,3652.09) 2527,3710 cw(c2463.01,3646.02) 2553.5,3646.02 2553.5,3639.58 cw(c2396.38,3639.58) 2507.48,3528.48 2465.6,3486.6 ccw(c2556.64,3395.56) 2427.89,3395.56 U1_1.H2@2427.89,3201.04
AWR_RX3_2: U1_2.H2 | length 1500.2
  L1 TOP w8.4: U1_2.H2@4745.89,3107.04 4745.89,3289.88 cw(c4838.07,3289.88) 4772.89,3355.06 cw(c4833.24,3294.71) 4833.24,3380.06 5194.12,3380.06 ccw(c5194.12,3495.66) 5275.86,3413.92 5281.14,3419.2 ccw(c5207.83,3492.51) 5311.51,3492.51 ccw(c5193.4,3492.52) 5276.92,3576.03 4981.99,3870.95 cw(c5045.99,3934.95) 4955.48,3934.95 4955.48,3991.32
AWR_RX3_3: U1_3.H2 | length 1500.4
  L1 TOP w8.4: U1_3.H2@3742.89,3201.04 3742.89,3425.54 cw(c3983.15,3425.54) 3813.26,3595.43 cw(c3935.49,3473.2) 3935.49,3646.06 4375.36,3646.06 ccw(c4375.36,3951.53) 4591.36,3735.53 4595.53,3739.7 ccw(c4468,3867.24) 4648.36,3867.23 4648.36,3991.32
AWR_RX3_4: U1_4.H2 | length 1500.1
  L1 TOP w8.4: 1116.48,3991.32 1116.48,3822.68 ccw(c1220.68,3822.68) 1147,3749 ccw(c1212.18,3814.17) 1212.18,3722 1352.64,3722 cw(c1352.64,3677.65) 1384,3709.01 cw(c1340.74,3665.74) 1401.92,3665.74 ; U1_4.H2@1257.89,3107.04 1257.89,3287.74 ccw(c1153.2,3287.73) 1227.23,3361.76 1063.6,3525.4 cw(c1107.14,3568.93) 1045.57,3568.93 1045.57,3568.99 cw(c1088.02,3568.99) 1058,3599 cw(c1091.82,3565.18) 1091.82,3613.01 1129.94,3613.01 1349.21,3613 ccw(c1349.21,3665.71) 1401.92,3665.71
AWR_RX4_1: U1_1.F2 | length 1500.1
  L1 TOP w8.4: 2037.84,3991.32 2037.84,3877.86 ccw(c2120.14,3877.86) 2061.92,3819.69 ; 2061.94,3819.67 ccw(c2107.01,3864.74) 2107.01,3801 2581.57,3801 cw(c2581.57,3710.27) 2645.72,3774.43 ; U1_1.F2@2479.07,3201.04 2479.07,3367.88 cw(c2587.59,3367.88) 2510.85,3444.61 cw(c2547.99,3407.51) 2547.98,3460 2619.19,3460 ccw(c2619.19,3524.81) 2684,3524.81 2684,3682.03 ccw(c2553.34,3682.03) 2645.73,3774.42
AWR_RX4_2: U1_2.F2 | length 1500.1
  L1 TOP w8.4: U1_2.F2@4797.07,3107.04 4797.07,3228.56 cw(c4878.39,3228.56) 4820.89,3286.06 cw(c4866.76,3240.2) 4866.75,3305.06 5219.08,3305.06 ccw(c5219.08,3451.87) 5322.89,3348.06 5333.42,3358.6 ccw(c5206.67,3485.36) 5385.93,3485.36 ccw(c5169.47,3485.36) 5322.53,3638.42 5050.89,3910.06 cw(c5095.85,3955.03) 5032.26,3955.02 5032.26,3991.32
AWR_RX4_3: U1_3.F2 | length 1500
  L1 TOP w8.4: U1_3.F2@3794.07,3201.04 3794.07,3374.37 cw(c3967.58,3374.37) 3844.89,3497.06 cw(c3965.6,3376.35) 3965.6,3547.06 4330.14,3547.06 ccw(c4330.14,4014.81) 4654.36,3677.66 4661.44,3684.74 ccw(c4507.23,3838.7) 4725.14,3838.7 4725.14,3991.32
AWR_RX4_4: U1_4.F2 | length 1500.1
  L1 TOP w8.4: 1193.26,3991.32 1193.26,3867.5 ccw(c1247,3867.5) 1209,3829.5 1212.17,3826.33 ccw(c1272.74,3886.9) 1272.74,3801.24 ccw(c1272.74,3886.5) 1358,3886.5 1358,3923.79 cw(c1409.21,3923.79) 1373,3960 1379.26,3966.25 cw(c1430.38,3915.16) 1430.36,3987.43 ; U1_4.F2@1309.07,3107.04 1309.07,3290.53 cw(c1431.08,3290.53) 1344.81,3376.81 1456.68,3488.68 ccw(c1354.51,3590.85) 1499,3590.85 1499,3912.35 ccw(c1420.17,3912.35) 1475.7,3968.3 1475.09,3968.91 ccw(c1430.38,3924.2) 1430.38,3987.43
AWR_TX1_1: U1_1.B4 | length 2080.3
  L1 TOP w8.4: U1_1.B4@2581.44,3149.86 2976.01,3149.86 cw(c2976.01,2966.19) 3105.89,3096.06 cw(c2999.66,2989.83) 3149.89,2989.84 3149.89,2946.83 ccw(c3335.23,2946.83) 3204.17,2815.78 3486.38,2533.57 cw(c3397.58,2444.77) 3523.16,2444.77 cw(c3416.39,2444.77) 3416.39,2338 3117.23,2338 cw(c3117.23,2391.53) 3079.38,2353.68 3025.79,2407.28 ccw(c2999.01,2380.49) 2972.22,2407.27 ccw(c3002.45,2377.04) 2959.69,2377.04 2959.62,2376.97 2959.62,2317.66
AWR_TX1_2: U1_2.B4 | length 2080.1
  L1 TOP w8.4: 4572,1856.96 4572,1947.48 cw(c4636.87,1947.48) 4591,1993.35 cw(c4633.62,1950.72) 4633.62,2011 4963.92,2011 ccw(c4963.92,2083.62) 5015.27,2032.27 5265.12,2282.12 ccw(c5125.4,2421.85) 5323,2421.85 5323,2903.59 ccw(c5160.26,2903.59) 5275.34,3018.66 ccw(c5185.52,2928.85) 5185.52,3055.86 U1_2.B4@4899.44,3055.86
AWR_TX1_3: U1_3.B4 | length 2080.1
  L1 TOP w8.4: 3650.64,1856.96 3650.64,1907.28 ccw(c3594.92,1907.28) 3634.32,1946.68 3594.01,1986.99 cw(c3619.01,2012) 3583.65,2012 3583.65,2012.44 cw(c3621.21,2012.44) 3594.65,2039 cw(c3623.76,2009.9) 3623.76,2051.06 3810.63,2051.06 ccw(c3810.63,2189.95) 3908.84,2091.74 3919.54,2102.44 4172.2,2355.11 ccw(c3881.1,2646.23) 4292.79,2646.22 4292.79,3040.01 ccw(c4204.26,3040.01) 4266.86,3102.61 4261.55,3107.91 ccw(c4160.29,3006.66) 4160.3,3149.86 U1_3.B4@3896.44,3149.86
AWR_TX1_4: U1_4.B4 | length 2080.4
  L1 TOP w8.4: U1_4.B4@1411.44,3055.86 1751.47,3055.86 cw(c1751.47,2933.64) 1837.89,3020.06 cw(c1664.06,2846.23) 1909.89,2846.23 1909.89,2686.49 ccw(c2406.8,2686.49) 2055.43,2335.13 2265.66,2124.9 ccw(c2426.27,2285.51) 2426.27,2058.37 2523.07,2058.37 cw(c2523.07,1820.34) 2691.39,1988.65 2691.48,1988.56 cw(c2600.19,1897.28) 2729.29,1897.28 ; 2729.28,1856.96 2729.28,1897.27
AWR_TX2_1: U1_1.B6 | length 2080.1
  L1 TOP w8.4: U1_1.B6@2581.44,3098.68 2949.3,3098.68 cw(c2949.3,3038.97) 2991.52,3081.19 cw(c2932.69,3022.36) 3015.89,3022.36 3015.89,2921.06 ccw(c3107.35,2921.06) 3042.68,2856.38 3345,2554.02 cw(c3312.49,2521.51) 3345,2489 cw(c3323.28,2510.71) 3323.28,2480 2950.01,2480 ccw(c2950.01,2262.7) 2796.35,2416.35 2762.39,2382.39 ccw(c2807.39,2337.39) 2762.39,2292.38 ; 2762.39,2292.37 ccw(c2804.33,2334.32) 2804.33,2275 2827.26,2275 cw(c2827.26,2223.43) 2863.72,2259.9 cw(c2817.45,2213.64) 2882.88,2213.64 2882.84,2213.6 2882.84,2164.1
AWR_TX2_2: U1_2.B6 | length 2080.5
  L1 TOP w8.4: 4264.88,1856.96 4264.88,1936.45 ccw(c4207.74,1936.44) 4248.14,1976.85 cw(c4290.24,2018.96) 4230.7,2018.96 4230.7,2034.84 cw(c4307.86,2034.84) 4253.3,2089.4 cw(c4303.03,2039.67) 4303.03,2110 4556.24,2110 ccw(c4556.24,2688.83) 4965.54,2279.54 5101.36,2415.36 ccw(c4860.82,2655.91) 5201,2655.91 5201,2911.89 ccw(c5108.21,2911.89) 5108.21,3004.68 U1_2.B6@4899.44,3004.68
AWR_TX2_3: U1_3.B6 | length 2080.4
  L1 TOP w8.4: 3343.52,1856.96 3343.52,1913.01 3343.68,1913.17 ccw(c3278.13,1913.17) 3324.48,1959.52 3306.66,1977.34 cw(c3370.65,2041.33) 3280.89,2029.8 3280.62,2031.99 cw(c3334.19,2038.87) 3296,2077.06 cw(c3353.04,2020.03) 3353.04,2100.69 3470.04,2100.69 ccw(c3470.04,2708.09) 3899.53,2278.59 4100.18,2479.24 ccw(c3866.6,2712.83) 4196.94,2712.83 4196.94,2983.66 ccw(c4086.01,2983.66) 4164.45,3062.1 ccw(c4076.14,2973.79) 4076.14,3098.68 U1_3.B6@3896.44,3098.68
AWR_TX2_4: U1_4.B6 | length 2080.1
  L1 TOP w8.4: U1_4.B6@1411.44,3004.68 1726.38,3004.68 cw(c1726.38,2903.56) 1797.89,2975.06 cw(c1691.66,2868.84) 1839.2,2897.12 1839.2,2457.44 cw(c1727.97,2457.44) 1806.62,2378.79 1777.71,2349.88 ccw(c1896.71,2230.88) 1728.42,2230.88 ccw(c1834.25,2230.87) 1759.41,2156.04 ccw(c1952.51,2349.13) 1952.5,2076.06 2070.55,2076.06 cw(c2070.55,1914.91) 2184.5,2028.86 ccw(c2283.31,2127.67) 2283.31,1987.93 2364.91,1987.93 cw(c2364.91,1934.43) 2402.74,1972.26 2403.1,1971.9 cw(c2357.28,1926.08) 2422.08,1926.08 2422.16,1926 2422.16,1856.96
AWR_TX3_1: U1_1.B8 | length 2080.4
  L1 TOP w8.4: 2375.47,2374.03 ccw(c2454.79,2294.72) 2342.62,2294.72 ccw(c2495.35,2294.7) 2387.36,2186.7 ccw(c2462.72,2262.04) 2462.72,2155.48 2672.09,2155.48 cw(c2672.09,2016.88) 2770.09,2114.89 cw(c2683.18,2027.98) 2806.09,2027.98 ; 2375.48,2374.04 cw(c2440.83,2308.69) 2440.83,2401.11 2477.57,2401.11 ccw(c2477.56,2853.75) 2797.63,2533.69 2846,2582.06 ccw(c2693.58,2734.49) 2909.14,2734.48 2909.14,2892.16 ccw(c2704.83,2874.62) 2849.83,3019.62 ; U1_1.B8@2581.44,3047.5 2782.53,3047.5 cw(c2782.52,2952.33) 2849.82,3019.62 ; 2806.06,1933.74 2806.06,2027.95
AWR_TX3_2: U1_2.B8 | length 2080.4
  L1 TOP w8.4: 3957.76,1856.96 3957.76,1977.73 cw(c4044.75,1977.73) 3983.24,2039.24 4120.94,2176.94 cw(c4191.25,2106.62) 4191.25,2206.06 4503.59,2206.06 ccw(c4503.59,2829.65) 4944.53,2388.7 4996.32,2440.5 ccw(c4676.3,2760.54) 5128.89,2760.53 5128.89,2872.54 ccw(c5048.04,2872.54) 5105.21,2929.71 ccw(c5047.79,2872.3) 5047.79,2953.5 U1_2.B8@4899.44,2953.5
AWR_TX3_3: U1_3.B8 | length 2080.1
  L1 TOP w8.4: 3036.4,1856.96 3036.4,1971.11 3036.48,1971.19 cw(c3239.73,1971.19) 3096.01,2114.91 cw(c3258.12,1952.81) 3258.12,2182.06 3482.21,2182.06 ccw(c3482.21,2613.2) 3787.08,2308.34 4030.23,2551.5 ccw(c3804.65,2777.08) 4123.67,2777.08 4123.67,2979.15 ccw(c4053.09,2979.15) 4103,3029.06 ccw(c4058.49,2984.55) 4058.49,3047.5 U1_3.B8@3896.44,3047.5
AWR_TX3_4: U1_4.B8 | length 2080.4
  L1 TOP w8.4: U1_4.B8@1411.44,2953.5 1658.11,2953.5 cw(c1658.11,2854.18) 1728.34,2924.41 cw(c1652.17,2848.24) 1759.89,2848.24 1759.89,2623.76 cw(c1301.91,2623.76) 1625.75,2299.92 1495.88,2170.06 ccw(c1570.38,2095.56) 1495.88,2021.06 ccw(c1565.91,2091.09) 1565.91,1992.06 2063.48,1992.06 cw(c2063.48,1947.49) 2095,1979 cw(c2046.99,1931) 2114.88,1931 2115.04,1930.84 2115.04,1856.96
AWR_VBGAP_1: C2_1.1 U1_1.B10 | length 58.9
  L1 TOP w12: v2(2562,2986) 2572.32,2996.31 U1_1.B10@2581.44,2996.31
  L8 BOTTOM w20: v2(2562,2986) 2563.59,2987.59 C2_1.1@2563.59,3020.51
AWR_VBGAP_2: C2_2.1 U1_2.B10 | length 60.9
  L1 TOP w10: v2@4879,2890 v2(4879,2892)
  L1 TOP w12: v2(4879,2892) 4889.32,2902.32 U1_2.B10@4899.44,2902.32
  L8 BOTTOM w15: v2(4879,2892) 4881.59,2894.59 C2_2.1@4881.59,2925.09
AWR_VBGAP_3: C2_3.1 U1_3.B10 | length 63.1
  L1 TOP w12: v2(3876,2984) 3888.32,2996.32 U1_3.B10@3896.44,2996.31
  L8 BOTTOM w20: v2(3876,2984) 3878.59,2986.59 C2_3.1@3878.59,3020.51
AWR_VBGAP_4: C2_4.1 U1_4.B10 | length 59.5
  L1 TOP w12: v2(1391,2889) 1404.32,2902.32 U1_4.B10@1411.44,2902.31
  L8 BOTTOM w15: v2(1391,2889) 1393,2891 C2_4.1@1393,2921.71
AWR_VOUT_PA_1: C4_1.1 C5_1.1 R188_1.1 U1_1.A2 U1_1.B2 | length 292.2
  L1 TOP w10: U1_1.B2@2581.44,3201.04 U1_1.A2@2607.03,3201.04 2621.97,3201.04
  L1 TOP w15: C4_1.1@2696.51,3194 C4_1.1@2696.81,3194.3
  L1 TOP w20: 2621.97,3201.04 2661.97,3201.04 2669.01,3194 C4_1.1@2696.51,3194 ; C5_1.1@2725.58,3255.06 2743.8,3255.06 2786.46,3297.73 R188_1.1@2807.55,3297.73
  L1 TOP w30: C4_1.1@2696.81,3194.3 2696.81,3231.29 C5_1.1@2723.08,3257.56
AWR_VOUT_PA_2: C4_2.1 C5_2.1 R188_2.1 U1_2.A2 U1_2.B2 | length 239.8
  L1 TOP w10: U1_2.B2@4899.44,3107.04 U1_2.A2@4925.03,3107.04 4943.01,3107.04
  L1 TOP w20: 4943.01,3107.04 4984.07,3107.04 C4_2.1@4990.81,3100.3
  L1 TOP w30: C4_2.1@4990.81,3100.3 4990.81,3132.48 C5_2.1@5012.4,3154.07 ; C5_2.1@5011.9,3154.07 C5_2.1@5012.4,3154.07 ; R188_2.1@5094.77,3154.07 C5_2.1@5012.4,3154.07
AWR_VOUT_PA_3: C4_3.1 C5_3.1 R188_3.1 U1_3.A2 U1_3.B2 | length 236.7
  L1 TOP w12: U1_3.B2@3896.44,3201.04 U1_3.A2@3922.03,3201.04 3939.05,3201.04
  L1 TOP w20: 3939.05,3201.04 3981.07,3201.04 C4_3.1@3987.81,3194.3
  L1 TOP w30: C4_3.1@3987.81,3194.3 3987.81,3226.98 C5_3.1@4008.9,3248.07 4082.53,3248.07 R188_3.1@4087.03,3252.57
AWR_VOUT_PA_4: C4_4.1 C5_4.1 R188_4.1 U1_4.A2 U1_4.B2 | length 282.2
  L1 TOP w12: U1_4.B2@1411.44,3107.04 U1_4.A2@1437.03,3107.04 1453.17,3107.04
  L1 TOP w20: 1453.17,3107.04 1497.55,3107.04 C4_4.1@1502.81,3112.3
  L1 TOP w30: C4_4.1@1502.81,3112.3 1502.81,3159.98 C5_4.1@1523.9,3181.07 1541.7,3181.07 1579.14,3218.51 1610.16,3218.51 R188_4.1@1616.77,3225.12
BSS_LOGGER_RS_1: R14_1.2 U1_1.R4 | length 195.1
  L1 TOP w6: R14_1.2@2108,3246 2114.14,3252.14 2149.86,3252.14 2165,3237 2165,3220.96 2236.1,3149.86 U1_1.R4@2248.76,3149.86
BSS_LOGGER_RS_2: R14_2.2 U1_2.R4 | length 189.4
  L1 TOP w6: R14_2.2@4425.89,3157 4468,3157 4481,3144 4481,3132.68 4557.82,3055.86 U1_2.R4@4566.76,3055.86
BSS_LOGGER_RS_3: R14_3.2 U1_3.R4 | length 206.4
  L1 TOP w4: 3464.98,3253.34 3487.51,3253.34 3501,3239.85 3501,3206.38 3557.52,3149.86 U1_3.R4@3563.76,3149.86
  L1 TOP w10.5: R14_3.2@3422.89,3246 3457.64,3246 3464.98,3253.34
BSS_LOGGER_RS_4: R14_4.2 U1_4.R4 | length 190.6
  L1 TOP w4: 1064.93,3062.94 1072.01,3055.86 U1_4.R4@1078.76,3055.86
  L1 TOP w6: R14_4.2@937.89,3157 984.2,3157 1000.68,3140.52 1000.68,3127.19 1064.93,3062.94
BUF_CLKOUT1: R103.2 R117.1 | length 64.8
  L1 TOP w10.5: R117.1@2846.05,5110.83 R103.2@2910.88,5110.83
BUF_CLKOUT1_RS: R103.1 U7.16 | length 98.7
  L1 TOP w10.5: U7.16@2947.73,5046.55 2958.12,5056.95 ; U7.16@2958.12,5041.49 2958.12,5056.95 ; R103.1@2958.12,5110.83 2958.12,5056.95 ; U7.16@2968.52,5046.55 2958.12,5056.95
BUF_CLKOUT2_RS: R104.1 U7.14 | length 294.7
  L1 TOP w10.5: R104.1@2936.49,4768.56 2916.33,4788.73 2916.33,4889.91 2887.62,4918.62 2887.62,4960.45 2917.48,4990.31 U7.14@2957.85,4990.31
BUF_CLKOUT3: R106.2 R126.1 | length 5019.4
  L1 TOP w10.5: R106.2@3089.19,4939.13 v2(3136.5,4939.13) ; R126.1@4041.18,2749.57 v3(4076.72,2749.57)
  L5 SIGNAL 2 w12: v2(3136.5,4939.13) 3213.75,4861.88 3213.75,4724.59 3281.83,4656.51 3281.83,4567.7 3312.76,4536.76 3340.06,4509.46 3550.22,4509.46 3573.44,4532.69 3654.35,4532.69 3721.88,4465.15 3721.88,4396.7 3789.16,4329.42 3863.65,4329.42 4055.99,4137.08 4055.99,3931.86 4165.21,3822.64 5231.07,3822.64 5246.12,3807.58 5246.12,3773.22 5228.23,3755.33 4438.8,3755.33 4410.98,3727.52 4410.98,3138.63 4349.03,3076.68 4278.36,3076.68 4129.86,2928.18 4129.86,2802.71 v3(4076.72,2749.57)
BUF_CLKOUT3_RS: R106.1 U7.12 | length 84.1
  L1 TOP w10.5: U7.12@2957.85,4939.13 R106.1@3041.94,4939.13
BUF_CLKOUT4_RS: R108.1 U7.10 | length 158.4
  L1 TOP w10.5: U7.10@2957.85,4887.95 2981.26,4887.95 3002.81,4866.4 3002.81,4833.89 2986.58,4817.66 R108.1@2986.58,4768.56
CONN_MONITOR_1: J4.1 J4.120 TP32.1 | length 1573.6
  L8 BOTTOM w7.75: TP32.1@2645.03,1115.91 2645.03,1070.9 2704.21,1011.72 J4.1@2704.21,979.24 2704.21,925.79 2730,900 2940,900 2953,887 3027.6,887 3040.6,900 3152.74,900 3176.3,923.55 3259.35,923.55 3285.9,897 3842,897 3884,855 3884,794 3865.63,775.63 J4.120@3865.63,743.02
CONN_MONITOR_2: J5.1 J5.120 TP33.1 | length 1598.5
  L3 SIGNAL 1 w5.1: v2(2714.21,4425) 2784.21,4355 3403.55,4355 3439.81,4318.74 3439.81,4283.03 3462.26,4260.58 3501.04,4260.58 3550.02,4211.6 3550.02,4182 3582.67,4149.35 3827.98,4149.35 v2(3865.63,4187)
  L8 BOTTOM w7.75: TP33.1@2657.29,4548.68 2657.29,4517.11 2667.57,4506.82 2667.57,4455.36 2687.31,4435.63 2703.58,4435.63 v2(2714.21,4425) 2704.21,4415 J5.1@2704.21,4365.06 ; J5.120@3865.63,4128.84 v2(3865.63,4187)
DIG_SYNC_SOURCE: R142.2 R143.2 U8.8 | length 153.9
  L8 BOTTOM w7.75: R143.2@1838.39,3919.29 1858.89,3939.79 ; R142.2@1838.39,3960.29 1858.89,3939.79 ; U8.8@1908.9,3880.96 1891.48,3880.96 1878.81,3893.62 1878.81,3930.31 1869.34,3939.79 1858.89,3939.79
DIG_SYNCOUT_RS_1: R1_1.2 U1_1.P11 | length 158.7
  L1 TOP w4: R1_1.2@2131.9,2985 2135.9,2981 2202,2981 2224.77,2958.23 2261.85,2958.23 U1_1.P11@2274.35,2970.72
DIG_SYNCOUT_RS_2: R1_2.2 U1_2.P11 | length 158.7
  L1 TOP w4: 4471.36,2884 4522,2884 4541.77,2864.23 4579.85,2864.23 U1_2.P11@4592.35,2876.73
  L1 TOP w6: R1_2.2@4449.9,2891 4456.9,2884 4471.36,2884
DIG_SYNCOUT_RS_3: R1_3.2 U1_3.P11 | length 158.7
  L1 TOP w4: R1_3.2@3446.9,2985 3466,2985 3472,2979 3515,2979 3535.77,2958.23 3576.85,2958.23 U1_3.P11@3589.35,2970.72
DIG_SYNCOUT_RS_4: R1_4.2 U1_4.P11 | length 158.7
  L1 TOP w4: R1_4.2@961.9,2891 966.06,2886.84 1028.16,2886.84 1050.77,2864.23 1091.85,2864.23 U1_4.P11@1104.35,2876.72
EXT_40M_BUF_AWR_1_RS: R115.2 R116.1 R117.2 | length 5103.7
  L1 TOP w10.5: v2(2736.01,5118.34) 2736.01,5132.28 2739.95,5136.23 2755.17,5136.23 ; R116.1@2787.39,2687.68 v2(2787.39,2716.2) ; R117.2@2798.8,5110.83 2792.1,5117.53 2773.86,5117.53 2755.17,5136.23 ; R115.2@2798.8,5161.63 2792.1,5154.92 2773.86,5154.92 2755.17,5136.23
  L5 SIGNAL 2 w12: v2(2736.01,5118.34) 2736.01,5082.94 2688.92,5035.85 2325.79,5035.85 2203.61,4913.67 1647.48,4913.67 1621.64,4887.83 1621.64,4846.51 1643.5,4824.64 1935.89,4824.64 1981.39,4779.15 1981.39,4704.99 1948.57,4672.17 1703.22,4672.17 1669.07,4638.03 1669.07,4503.97 1700.69,4472.35 1996.53,4472.35 2026.88,4442 2026.88,4040.78 2343.82,3723.84 2343.82,3674.27 2405.7,3612.4 2698.66,3612.4 2916.05,3395.01 2916.05,2943.41 2761.03,2788.4 2761.03,2742.56 v2(2787.39,2716.2)
EXT_40MHZ_CLK_1V8: J4.74 R115.1 | length 5346.8
  L1 TOP w10.5: R115.1@2846.05,5161.63 2964.52,5161.63 2998.97,5127.18 v2(2998.97,5079.18)
  L5 SIGNAL 2 w12: v2(2963,672) 2963,879.16 2928.83,913.32 2928.83,939.35 2850.75,1017.44 2850.75,1135.48 2922.54,1207.28 2922.54,2714.26 3040.77,2832.49 3040.77,3438.97 2525.51,3954.23 2525.51,4022.96 2383.71,4164.76 2383.71,4386.29 2620.11,4622.69 2620.11,4679.15 2998.97,5058 v2(2998.97,5079.18)
  L8 BOTTOM w7.75: J4.74@2960.12,743.02 2960.12,674.88 v2(2963,672)
EXT_DIG_SYNC: J4.64 R142.1 | length 4659.5
  L5 SIGNAL 2 w12: v2(1617.95,3978.76) 1654.84,4015.65 1916.04,4015.65 2382.45,3549.24 2651.16,3549.24 2765.25,3435.16 2765.25,3329.43 2866.54,3228.13 2866.54,2963.13 2717.14,2813.73 2717.14,2702.79 2743.58,2676.34 2743.58,2323.96 2558.87,2139.25 v2(2558.87,2104.18)
  L6 SIGNAL 3 w6.9: v2(2558.87,2104.18) 2567.52,2095.53 2567.52,1300.82 2763.82,1104.52 2813.76,1104.52 2853.47,1064.81 2853.47,1008.41 2796.02,950.96 2796.02,912.03 v2(2759,875)
  L8 BOTTOM w7.75: v2(1617.95,3978.76) 1743.32,3978.76 1761.79,3960.29 R142.1@1791.14,3960.29 ; v2(2759,875) 2759,837 2763.27,832.73 J4.64@2763.27,743.02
